VERSION 5.8 ;
BUSBITCHARS "[]" ;
DIVIDERCHAR "/" ;
UNITS
    DATABASE MICRONS 1000 ;
END UNITS

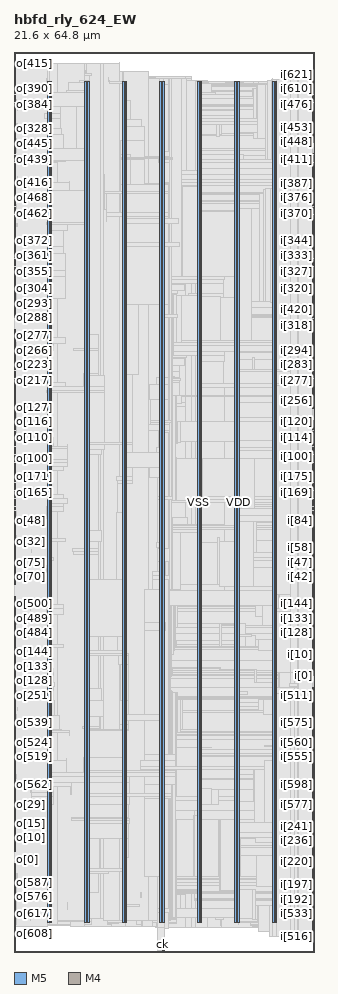
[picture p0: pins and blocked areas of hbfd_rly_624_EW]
MACRO hbfd_rly_624_EW
  FOREIGN hbfd_rly_624_EW 0 0 ;
  CLASS BLOCK ;
  SIZE 21.6 BY 64.8 ;
  PIN ck
    DIRECTION INPUT ;
    USE SIGNAL ;
    PORT
      LAYER M5 ;
        RECT  10.704 0 10.728 0.084 ;
    END
  END ck
  PIN i[0]
    DIRECTION INPUT ;
    USE SIGNAL ;
    PORT
      LAYER M4 ;
        RECT  21.516 19.92 21.6 19.944 ;
    END
  END i[0]
  PIN i[100]
    DIRECTION INPUT ;
    USE SIGNAL ;
    PORT
      LAYER M4 ;
        RECT  21.516 35.664 21.6 35.688 ;
    END
  END i[100]
  PIN i[101]
    DIRECTION INPUT ;
    USE SIGNAL ;
    PORT
      LAYER M4 ;
        RECT  21.516 35.76 21.6 35.784 ;
    END
  END i[101]
  PIN i[102]
    DIRECTION INPUT ;
    USE SIGNAL ;
    PORT
      LAYER M4 ;
        RECT  21.516 35.856 21.6 35.88 ;
    END
  END i[102]
  PIN i[103]
    DIRECTION INPUT ;
    USE SIGNAL ;
    PORT
      LAYER M4 ;
        RECT  21.516 35.952 21.6 35.976 ;
    END
  END i[103]
  PIN i[104]
    DIRECTION INPUT ;
    USE SIGNAL ;
    PORT
      LAYER M4 ;
        RECT  21.516 36.048 21.6 36.072 ;
    END
  END i[104]
  PIN i[105]
    DIRECTION INPUT ;
    USE SIGNAL ;
    PORT
      LAYER M4 ;
        RECT  21.516 36.144 21.6 36.168 ;
    END
  END i[105]
  PIN i[106]
    DIRECTION INPUT ;
    USE SIGNAL ;
    PORT
      LAYER M4 ;
        RECT  21.516 36.24 21.6 36.264 ;
    END
  END i[106]
  PIN i[107]
    DIRECTION INPUT ;
    USE SIGNAL ;
    PORT
      LAYER M4 ;
        RECT  21.516 36.336 21.6 36.36 ;
    END
  END i[107]
  PIN i[108]
    DIRECTION INPUT ;
    USE SIGNAL ;
    PORT
      LAYER M4 ;
        RECT  21.516 36.432 21.6 36.456 ;
    END
  END i[108]
  PIN i[109]
    DIRECTION INPUT ;
    USE SIGNAL ;
    PORT
      LAYER M4 ;
        RECT  21.516 36.528 21.6 36.552 ;
    END
  END i[109]
  PIN i[10]
    DIRECTION INPUT ;
    USE SIGNAL ;
    PORT
      LAYER M4 ;
        RECT  21.516 20.88 21.6 20.904 ;
    END
  END i[10]
  PIN i[110]
    DIRECTION INPUT ;
    USE SIGNAL ;
    PORT
      LAYER M4 ;
        RECT  21.516 36.624 21.6 36.648 ;
    END
  END i[110]
  PIN i[111]
    DIRECTION INPUT ;
    USE SIGNAL ;
    PORT
      LAYER M4 ;
        RECT  21.516 36.72 21.6 36.744 ;
    END
  END i[111]
  PIN i[112]
    DIRECTION INPUT ;
    USE SIGNAL ;
    PORT
      LAYER M4 ;
        RECT  21.516 36.816 21.6 36.84 ;
    END
  END i[112]
  PIN i[113]
    DIRECTION INPUT ;
    USE SIGNAL ;
    PORT
      LAYER M4 ;
        RECT  21.516 36.912 21.6 36.936 ;
    END
  END i[113]
  PIN i[114]
    DIRECTION INPUT ;
    USE SIGNAL ;
    PORT
      LAYER M4 ;
        RECT  21.516 37.008 21.6 37.032 ;
    END
  END i[114]
  PIN i[115]
    DIRECTION INPUT ;
    USE SIGNAL ;
    PORT
      LAYER M4 ;
        RECT  21.516 37.104 21.6 37.128 ;
    END
  END i[115]
  PIN i[116]
    DIRECTION INPUT ;
    USE SIGNAL ;
    PORT
      LAYER M4 ;
        RECT  21.516 37.2 21.6 37.224 ;
    END
  END i[116]
  PIN i[117]
    DIRECTION INPUT ;
    USE SIGNAL ;
    PORT
      LAYER M4 ;
        RECT  21.516 37.296 21.6 37.32 ;
    END
  END i[117]
  PIN i[118]
    DIRECTION INPUT ;
    USE SIGNAL ;
    PORT
      LAYER M4 ;
        RECT  21.516 37.392 21.6 37.416 ;
    END
  END i[118]
  PIN i[119]
    DIRECTION INPUT ;
    USE SIGNAL ;
    PORT
      LAYER M4 ;
        RECT  21.516 37.488 21.6 37.512 ;
    END
  END i[119]
  PIN i[11]
    DIRECTION INPUT ;
    USE SIGNAL ;
    PORT
      LAYER M4 ;
        RECT  21.516 20.976 21.6 21 ;
    END
  END i[11]
  PIN i[120]
    DIRECTION INPUT ;
    USE SIGNAL ;
    PORT
      LAYER M4 ;
        RECT  21.516 37.584 21.6 37.608 ;
    END
  END i[120]
  PIN i[121]
    DIRECTION INPUT ;
    USE SIGNAL ;
    PORT
      LAYER M4 ;
        RECT  21.516 37.68 21.6 37.704 ;
    END
  END i[121]
  PIN i[122]
    DIRECTION INPUT ;
    USE SIGNAL ;
    PORT
      LAYER M4 ;
        RECT  21.516 37.776 21.6 37.8 ;
    END
  END i[122]
  PIN i[123]
    DIRECTION INPUT ;
    USE SIGNAL ;
    PORT
      LAYER M4 ;
        RECT  21.516 37.872 21.6 37.896 ;
    END
  END i[123]
  PIN i[124]
    DIRECTION INPUT ;
    USE SIGNAL ;
    PORT
      LAYER M4 ;
        RECT  21.516 37.968 21.6 37.992 ;
    END
  END i[124]
  PIN i[125]
    DIRECTION INPUT ;
    USE SIGNAL ;
    PORT
      LAYER M4 ;
        RECT  21.516 38.064 21.6 38.088 ;
    END
  END i[125]
  PIN i[126]
    DIRECTION INPUT ;
    USE SIGNAL ;
    PORT
      LAYER M4 ;
        RECT  21.516 38.16 21.6 38.184 ;
    END
  END i[126]
  PIN i[127]
    DIRECTION INPUT ;
    USE SIGNAL ;
    PORT
      LAYER M4 ;
        RECT  21.516 38.256 21.6 38.28 ;
    END
  END i[127]
  PIN i[128]
    DIRECTION INPUT ;
    USE SIGNAL ;
    PORT
      LAYER M4 ;
        RECT  21.516 22.992 21.6 23.016 ;
    END
  END i[128]
  PIN i[129]
    DIRECTION INPUT ;
    USE SIGNAL ;
    PORT
      LAYER M4 ;
        RECT  21.516 23.088 21.6 23.112 ;
    END
  END i[129]
  PIN i[12]
    DIRECTION INPUT ;
    USE SIGNAL ;
    PORT
      LAYER M4 ;
        RECT  21.516 21.072 21.6 21.096 ;
    END
  END i[12]
  PIN i[130]
    DIRECTION INPUT ;
    USE SIGNAL ;
    PORT
      LAYER M4 ;
        RECT  21.516 23.184 21.6 23.208 ;
    END
  END i[130]
  PIN i[131]
    DIRECTION INPUT ;
    USE SIGNAL ;
    PORT
      LAYER M4 ;
        RECT  21.516 23.28 21.6 23.304 ;
    END
  END i[131]
  PIN i[132]
    DIRECTION INPUT ;
    USE SIGNAL ;
    PORT
      LAYER M4 ;
        RECT  21.516 23.376 21.6 23.4 ;
    END
  END i[132]
  PIN i[133]
    DIRECTION INPUT ;
    USE SIGNAL ;
    PORT
      LAYER M4 ;
        RECT  21.516 23.472 21.6 23.496 ;
    END
  END i[133]
  PIN i[134]
    DIRECTION INPUT ;
    USE SIGNAL ;
    PORT
      LAYER M4 ;
        RECT  21.516 23.568 21.6 23.592 ;
    END
  END i[134]
  PIN i[135]
    DIRECTION INPUT ;
    USE SIGNAL ;
    PORT
      LAYER M4 ;
        RECT  21.516 23.664 21.6 23.688 ;
    END
  END i[135]
  PIN i[136]
    DIRECTION INPUT ;
    USE SIGNAL ;
    PORT
      LAYER M4 ;
        RECT  21.516 23.76 21.6 23.784 ;
    END
  END i[136]
  PIN i[137]
    DIRECTION INPUT ;
    USE SIGNAL ;
    PORT
      LAYER M4 ;
        RECT  21.516 23.856 21.6 23.88 ;
    END
  END i[137]
  PIN i[138]
    DIRECTION INPUT ;
    USE SIGNAL ;
    PORT
      LAYER M4 ;
        RECT  21.516 23.952 21.6 23.976 ;
    END
  END i[138]
  PIN i[139]
    DIRECTION INPUT ;
    USE SIGNAL ;
    PORT
      LAYER M4 ;
        RECT  21.516 24.048 21.6 24.072 ;
    END
  END i[139]
  PIN i[13]
    DIRECTION INPUT ;
    USE SIGNAL ;
    PORT
      LAYER M4 ;
        RECT  21.516 21.168 21.6 21.192 ;
    END
  END i[13]
  PIN i[140]
    DIRECTION INPUT ;
    USE SIGNAL ;
    PORT
      LAYER M4 ;
        RECT  21.516 24.144 21.6 24.168 ;
    END
  END i[140]
  PIN i[141]
    DIRECTION INPUT ;
    USE SIGNAL ;
    PORT
      LAYER M4 ;
        RECT  21.516 24.24 21.6 24.264 ;
    END
  END i[141]
  PIN i[142]
    DIRECTION INPUT ;
    USE SIGNAL ;
    PORT
      LAYER M4 ;
        RECT  21.516 24.336 21.6 24.36 ;
    END
  END i[142]
  PIN i[143]
    DIRECTION INPUT ;
    USE SIGNAL ;
    PORT
      LAYER M4 ;
        RECT  21.516 24.432 21.6 24.456 ;
    END
  END i[143]
  PIN i[144]
    DIRECTION INPUT ;
    USE SIGNAL ;
    PORT
      LAYER M4 ;
        RECT  21.516 24.528 21.6 24.552 ;
    END
  END i[144]
  PIN i[145]
    DIRECTION INPUT ;
    USE SIGNAL ;
    PORT
      LAYER M4 ;
        RECT  21.516 24.624 21.6 24.648 ;
    END
  END i[145]
  PIN i[146]
    DIRECTION INPUT ;
    USE SIGNAL ;
    PORT
      LAYER M4 ;
        RECT  21.516 24.72 21.6 24.744 ;
    END
  END i[146]
  PIN i[147]
    DIRECTION INPUT ;
    USE SIGNAL ;
    PORT
      LAYER M4 ;
        RECT  21.516 24.816 21.6 24.84 ;
    END
  END i[147]
  PIN i[148]
    DIRECTION INPUT ;
    USE SIGNAL ;
    PORT
      LAYER M4 ;
        RECT  21.516 24.912 21.6 24.936 ;
    END
  END i[148]
  PIN i[149]
    DIRECTION INPUT ;
    USE SIGNAL ;
    PORT
      LAYER M4 ;
        RECT  21.516 25.008 21.6 25.032 ;
    END
  END i[149]
  PIN i[14]
    DIRECTION INPUT ;
    USE SIGNAL ;
    PORT
      LAYER M4 ;
        RECT  21.516 21.264 21.6 21.288 ;
    END
  END i[14]
  PIN i[150]
    DIRECTION INPUT ;
    USE SIGNAL ;
    PORT
      LAYER M4 ;
        RECT  21.516 25.104 21.6 25.128 ;
    END
  END i[150]
  PIN i[151]
    DIRECTION INPUT ;
    USE SIGNAL ;
    PORT
      LAYER M4 ;
        RECT  21.516 25.2 21.6 25.224 ;
    END
  END i[151]
  PIN i[152]
    DIRECTION INPUT ;
    USE SIGNAL ;
    PORT
      LAYER M4 ;
        RECT  21.516 25.296 21.6 25.32 ;
    END
  END i[152]
  PIN i[153]
    DIRECTION INPUT ;
    USE SIGNAL ;
    PORT
      LAYER M4 ;
        RECT  21.516 25.392 21.6 25.416 ;
    END
  END i[153]
  PIN i[154]
    DIRECTION INPUT ;
    USE SIGNAL ;
    PORT
      LAYER M4 ;
        RECT  21.516 25.488 21.6 25.512 ;
    END
  END i[154]
  PIN i[155]
    DIRECTION INPUT ;
    USE SIGNAL ;
    PORT
      LAYER M4 ;
        RECT  21.516 25.584 21.6 25.608 ;
    END
  END i[155]
  PIN i[156]
    DIRECTION INPUT ;
    USE SIGNAL ;
    PORT
      LAYER M4 ;
        RECT  21.516 25.68 21.6 25.704 ;
    END
  END i[156]
  PIN i[157]
    DIRECTION INPUT ;
    USE SIGNAL ;
    PORT
      LAYER M4 ;
        RECT  21.516 25.776 21.6 25.8 ;
    END
  END i[157]
  PIN i[158]
    DIRECTION INPUT ;
    USE SIGNAL ;
    PORT
      LAYER M4 ;
        RECT  21.516 25.872 21.6 25.896 ;
    END
  END i[158]
  PIN i[159]
    DIRECTION INPUT ;
    USE SIGNAL ;
    PORT
      LAYER M4 ;
        RECT  21.516 25.968 21.6 25.992 ;
    END
  END i[159]
  PIN i[15]
    DIRECTION INPUT ;
    USE SIGNAL ;
    PORT
      LAYER M4 ;
        RECT  21.516 21.36 21.6 21.384 ;
    END
  END i[15]
  PIN i[160]
    DIRECTION INPUT ;
    USE SIGNAL ;
    PORT
      LAYER M4 ;
        RECT  21.516 32.208 21.6 32.232 ;
    END
  END i[160]
  PIN i[161]
    DIRECTION INPUT ;
    USE SIGNAL ;
    PORT
      LAYER M4 ;
        RECT  21.516 32.304 21.6 32.328 ;
    END
  END i[161]
  PIN i[162]
    DIRECTION INPUT ;
    USE SIGNAL ;
    PORT
      LAYER M4 ;
        RECT  21.516 32.4 21.6 32.424 ;
    END
  END i[162]
  PIN i[163]
    DIRECTION INPUT ;
    USE SIGNAL ;
    PORT
      LAYER M4 ;
        RECT  21.516 32.496 21.6 32.52 ;
    END
  END i[163]
  PIN i[164]
    DIRECTION INPUT ;
    USE SIGNAL ;
    PORT
      LAYER M4 ;
        RECT  21.516 32.592 21.6 32.616 ;
    END
  END i[164]
  PIN i[165]
    DIRECTION INPUT ;
    USE SIGNAL ;
    PORT
      LAYER M4 ;
        RECT  21.516 32.688 21.6 32.712 ;
    END
  END i[165]
  PIN i[166]
    DIRECTION INPUT ;
    USE SIGNAL ;
    PORT
      LAYER M4 ;
        RECT  21.516 32.784 21.6 32.808 ;
    END
  END i[166]
  PIN i[167]
    DIRECTION INPUT ;
    USE SIGNAL ;
    PORT
      LAYER M4 ;
        RECT  21.516 32.88 21.6 32.904 ;
    END
  END i[167]
  PIN i[168]
    DIRECTION INPUT ;
    USE SIGNAL ;
    PORT
      LAYER M4 ;
        RECT  21.516 32.976 21.6 33 ;
    END
  END i[168]
  PIN i[169]
    DIRECTION INPUT ;
    USE SIGNAL ;
    PORT
      LAYER M4 ;
        RECT  21.516 33.072 21.6 33.096 ;
    END
  END i[169]
  PIN i[16]
    DIRECTION INPUT ;
    USE SIGNAL ;
    PORT
      LAYER M4 ;
        RECT  21.516 21.456 21.6 21.48 ;
    END
  END i[16]
  PIN i[170]
    DIRECTION INPUT ;
    USE SIGNAL ;
    PORT
      LAYER M4 ;
        RECT  21.516 33.168 21.6 33.192 ;
    END
  END i[170]
  PIN i[171]
    DIRECTION INPUT ;
    USE SIGNAL ;
    PORT
      LAYER M4 ;
        RECT  21.516 33.264 21.6 33.288 ;
    END
  END i[171]
  PIN i[172]
    DIRECTION INPUT ;
    USE SIGNAL ;
    PORT
      LAYER M4 ;
        RECT  21.516 33.36 21.6 33.384 ;
    END
  END i[172]
  PIN i[173]
    DIRECTION INPUT ;
    USE SIGNAL ;
    PORT
      LAYER M4 ;
        RECT  21.516 33.456 21.6 33.48 ;
    END
  END i[173]
  PIN i[174]
    DIRECTION INPUT ;
    USE SIGNAL ;
    PORT
      LAYER M4 ;
        RECT  21.516 33.552 21.6 33.576 ;
    END
  END i[174]
  PIN i[175]
    DIRECTION INPUT ;
    USE SIGNAL ;
    PORT
      LAYER M4 ;
        RECT  21.516 33.648 21.6 33.672 ;
    END
  END i[175]
  PIN i[176]
    DIRECTION INPUT ;
    USE SIGNAL ;
    PORT
      LAYER M4 ;
        RECT  21.516 33.744 21.6 33.768 ;
    END
  END i[176]
  PIN i[177]
    DIRECTION INPUT ;
    USE SIGNAL ;
    PORT
      LAYER M4 ;
        RECT  21.516 33.84 21.6 33.864 ;
    END
  END i[177]
  PIN i[178]
    DIRECTION INPUT ;
    USE SIGNAL ;
    PORT
      LAYER M4 ;
        RECT  21.516 33.936 21.6 33.96 ;
    END
  END i[178]
  PIN i[179]
    DIRECTION INPUT ;
    USE SIGNAL ;
    PORT
      LAYER M4 ;
        RECT  21.516 34.032 21.6 34.056 ;
    END
  END i[179]
  PIN i[17]
    DIRECTION INPUT ;
    USE SIGNAL ;
    PORT
      LAYER M4 ;
        RECT  21.516 21.552 21.6 21.576 ;
    END
  END i[17]
  PIN i[180]
    DIRECTION INPUT ;
    USE SIGNAL ;
    PORT
      LAYER M4 ;
        RECT  21.516 34.128 21.6 34.152 ;
    END
  END i[180]
  PIN i[181]
    DIRECTION INPUT ;
    USE SIGNAL ;
    PORT
      LAYER M4 ;
        RECT  21.516 34.224 21.6 34.248 ;
    END
  END i[181]
  PIN i[182]
    DIRECTION INPUT ;
    USE SIGNAL ;
    PORT
      LAYER M4 ;
        RECT  21.516 34.32 21.6 34.344 ;
    END
  END i[182]
  PIN i[183]
    DIRECTION INPUT ;
    USE SIGNAL ;
    PORT
      LAYER M4 ;
        RECT  21.516 34.416 21.6 34.44 ;
    END
  END i[183]
  PIN i[184]
    DIRECTION INPUT ;
    USE SIGNAL ;
    PORT
      LAYER M4 ;
        RECT  21.516 34.512 21.6 34.536 ;
    END
  END i[184]
  PIN i[185]
    DIRECTION INPUT ;
    USE SIGNAL ;
    PORT
      LAYER M4 ;
        RECT  21.516 34.608 21.6 34.632 ;
    END
  END i[185]
  PIN i[186]
    DIRECTION INPUT ;
    USE SIGNAL ;
    PORT
      LAYER M4 ;
        RECT  21.516 34.704 21.6 34.728 ;
    END
  END i[186]
  PIN i[187]
    DIRECTION INPUT ;
    USE SIGNAL ;
    PORT
      LAYER M4 ;
        RECT  21.516 34.8 21.6 34.824 ;
    END
  END i[187]
  PIN i[188]
    DIRECTION INPUT ;
    USE SIGNAL ;
    PORT
      LAYER M4 ;
        RECT  21.516 34.896 21.6 34.92 ;
    END
  END i[188]
  PIN i[189]
    DIRECTION INPUT ;
    USE SIGNAL ;
    PORT
      LAYER M4 ;
        RECT  21.516 34.992 21.6 35.016 ;
    END
  END i[189]
  PIN i[18]
    DIRECTION INPUT ;
    USE SIGNAL ;
    PORT
      LAYER M4 ;
        RECT  21.516 21.648 21.6 21.672 ;
    END
  END i[18]
  PIN i[190]
    DIRECTION INPUT ;
    USE SIGNAL ;
    PORT
      LAYER M4 ;
        RECT  21.516 35.088 21.6 35.112 ;
    END
  END i[190]
  PIN i[191]
    DIRECTION INPUT ;
    USE SIGNAL ;
    PORT
      LAYER M4 ;
        RECT  21.516 35.184 21.6 35.208 ;
    END
  END i[191]
  PIN i[192]
    DIRECTION INPUT ;
    USE SIGNAL ;
    PORT
      LAYER M4 ;
        RECT  21.516 3.792 21.6 3.816 ;
    END
  END i[192]
  PIN i[193]
    DIRECTION INPUT ;
    USE SIGNAL ;
    PORT
      LAYER M4 ;
        RECT  21.516 3.888 21.6 3.912 ;
    END
  END i[193]
  PIN i[194]
    DIRECTION INPUT ;
    USE SIGNAL ;
    PORT
      LAYER M4 ;
        RECT  21.516 3.984 21.6 4.008 ;
    END
  END i[194]
  PIN i[195]
    DIRECTION INPUT ;
    USE SIGNAL ;
    PORT
      LAYER M4 ;
        RECT  21.516 4.08 21.6 4.104 ;
    END
  END i[195]
  PIN i[196]
    DIRECTION INPUT ;
    USE SIGNAL ;
    PORT
      LAYER M4 ;
        RECT  21.516 4.176 21.6 4.2 ;
    END
  END i[196]
  PIN i[197]
    DIRECTION INPUT ;
    USE SIGNAL ;
    PORT
      LAYER M4 ;
        RECT  21.516 4.272 21.6 4.296 ;
    END
  END i[197]
  PIN i[198]
    DIRECTION INPUT ;
    USE SIGNAL ;
    PORT
      LAYER M4 ;
        RECT  21.516 4.368 21.6 4.392 ;
    END
  END i[198]
  PIN i[199]
    DIRECTION INPUT ;
    USE SIGNAL ;
    PORT
      LAYER M4 ;
        RECT  21.516 4.464 21.6 4.488 ;
    END
  END i[199]
  PIN i[19]
    DIRECTION INPUT ;
    USE SIGNAL ;
    PORT
      LAYER M4 ;
        RECT  21.516 21.744 21.6 21.768 ;
    END
  END i[19]
  PIN i[1]
    DIRECTION INPUT ;
    USE SIGNAL ;
    PORT
      LAYER M4 ;
        RECT  21.516 20.016 21.6 20.04 ;
    END
  END i[1]
  PIN i[200]
    DIRECTION INPUT ;
    USE SIGNAL ;
    PORT
      LAYER M4 ;
        RECT  21.516 4.56 21.6 4.584 ;
    END
  END i[200]
  PIN i[201]
    DIRECTION INPUT ;
    USE SIGNAL ;
    PORT
      LAYER M4 ;
        RECT  21.516 4.656 21.6 4.68 ;
    END
  END i[201]
  PIN i[202]
    DIRECTION INPUT ;
    USE SIGNAL ;
    PORT
      LAYER M4 ;
        RECT  21.516 4.752 21.6 4.776 ;
    END
  END i[202]
  PIN i[203]
    DIRECTION INPUT ;
    USE SIGNAL ;
    PORT
      LAYER M4 ;
        RECT  21.516 4.848 21.6 4.872 ;
    END
  END i[203]
  PIN i[204]
    DIRECTION INPUT ;
    USE SIGNAL ;
    PORT
      LAYER M4 ;
        RECT  21.516 4.944 21.6 4.968 ;
    END
  END i[204]
  PIN i[205]
    DIRECTION INPUT ;
    USE SIGNAL ;
    PORT
      LAYER M4 ;
        RECT  21.516 5.04 21.6 5.064 ;
    END
  END i[205]
  PIN i[206]
    DIRECTION INPUT ;
    USE SIGNAL ;
    PORT
      LAYER M4 ;
        RECT  21.516 5.136 21.6 5.16 ;
    END
  END i[206]
  PIN i[207]
    DIRECTION INPUT ;
    USE SIGNAL ;
    PORT
      LAYER M4 ;
        RECT  21.516 5.232 21.6 5.256 ;
    END
  END i[207]
  PIN i[208]
    DIRECTION INPUT ;
    USE SIGNAL ;
    PORT
      LAYER M4 ;
        RECT  21.516 5.328 21.6 5.352 ;
    END
  END i[208]
  PIN i[209]
    DIRECTION INPUT ;
    USE SIGNAL ;
    PORT
      LAYER M4 ;
        RECT  21.516 5.424 21.6 5.448 ;
    END
  END i[209]
  PIN i[20]
    DIRECTION INPUT ;
    USE SIGNAL ;
    PORT
      LAYER M4 ;
        RECT  21.516 21.84 21.6 21.864 ;
    END
  END i[20]
  PIN i[210]
    DIRECTION INPUT ;
    USE SIGNAL ;
    PORT
      LAYER M4 ;
        RECT  21.516 5.52 21.6 5.544 ;
    END
  END i[210]
  PIN i[211]
    DIRECTION INPUT ;
    USE SIGNAL ;
    PORT
      LAYER M4 ;
        RECT  21.516 5.616 21.6 5.64 ;
    END
  END i[211]
  PIN i[212]
    DIRECTION INPUT ;
    USE SIGNAL ;
    PORT
      LAYER M4 ;
        RECT  21.516 5.712 21.6 5.736 ;
    END
  END i[212]
  PIN i[213]
    DIRECTION INPUT ;
    USE SIGNAL ;
    PORT
      LAYER M4 ;
        RECT  21.516 5.808 21.6 5.832 ;
    END
  END i[213]
  PIN i[214]
    DIRECTION INPUT ;
    USE SIGNAL ;
    PORT
      LAYER M4 ;
        RECT  21.516 5.904 21.6 5.928 ;
    END
  END i[214]
  PIN i[215]
    DIRECTION INPUT ;
    USE SIGNAL ;
    PORT
      LAYER M4 ;
        RECT  21.516 6 21.6 6.024 ;
    END
  END i[215]
  PIN i[216]
    DIRECTION INPUT ;
    USE SIGNAL ;
    PORT
      LAYER M4 ;
        RECT  21.516 6.096 21.6 6.12 ;
    END
  END i[216]
  PIN i[217]
    DIRECTION INPUT ;
    USE SIGNAL ;
    PORT
      LAYER M4 ;
        RECT  21.516 6.192 21.6 6.216 ;
    END
  END i[217]
  PIN i[218]
    DIRECTION INPUT ;
    USE SIGNAL ;
    PORT
      LAYER M4 ;
        RECT  21.516 6.288 21.6 6.312 ;
    END
  END i[218]
  PIN i[219]
    DIRECTION INPUT ;
    USE SIGNAL ;
    PORT
      LAYER M4 ;
        RECT  21.516 6.384 21.6 6.408 ;
    END
  END i[219]
  PIN i[21]
    DIRECTION INPUT ;
    USE SIGNAL ;
    PORT
      LAYER M4 ;
        RECT  21.516 21.936 21.6 21.96 ;
    END
  END i[21]
  PIN i[220]
    DIRECTION INPUT ;
    USE SIGNAL ;
    PORT
      LAYER M4 ;
        RECT  21.516 6.48 21.6 6.504 ;
    END
  END i[220]
  PIN i[221]
    DIRECTION INPUT ;
    USE SIGNAL ;
    PORT
      LAYER M4 ;
        RECT  21.516 6.576 21.6 6.6 ;
    END
  END i[221]
  PIN i[222]
    DIRECTION INPUT ;
    USE SIGNAL ;
    PORT
      LAYER M4 ;
        RECT  21.516 6.672 21.6 6.696 ;
    END
  END i[222]
  PIN i[223]
    DIRECTION INPUT ;
    USE SIGNAL ;
    PORT
      LAYER M4 ;
        RECT  21.516 6.768 21.6 6.792 ;
    END
  END i[223]
  PIN i[224]
    DIRECTION INPUT ;
    USE SIGNAL ;
    PORT
      LAYER M4 ;
        RECT  21.516 6.864 21.6 6.888 ;
    END
  END i[224]
  PIN i[225]
    DIRECTION INPUT ;
    USE SIGNAL ;
    PORT
      LAYER M4 ;
        RECT  21.516 6.96 21.6 6.984 ;
    END
  END i[225]
  PIN i[226]
    DIRECTION INPUT ;
    USE SIGNAL ;
    PORT
      LAYER M4 ;
        RECT  21.516 7.056 21.6 7.08 ;
    END
  END i[226]
  PIN i[227]
    DIRECTION INPUT ;
    USE SIGNAL ;
    PORT
      LAYER M4 ;
        RECT  21.516 7.152 21.6 7.176 ;
    END
  END i[227]
  PIN i[228]
    DIRECTION INPUT ;
    USE SIGNAL ;
    PORT
      LAYER M4 ;
        RECT  21.516 7.248 21.6 7.272 ;
    END
  END i[228]
  PIN i[229]
    DIRECTION INPUT ;
    USE SIGNAL ;
    PORT
      LAYER M4 ;
        RECT  21.516 7.344 21.6 7.368 ;
    END
  END i[229]
  PIN i[22]
    DIRECTION INPUT ;
    USE SIGNAL ;
    PORT
      LAYER M4 ;
        RECT  21.516 22.032 21.6 22.056 ;
    END
  END i[22]
  PIN i[230]
    DIRECTION INPUT ;
    USE SIGNAL ;
    PORT
      LAYER M4 ;
        RECT  21.516 7.44 21.6 7.464 ;
    END
  END i[230]
  PIN i[231]
    DIRECTION INPUT ;
    USE SIGNAL ;
    PORT
      LAYER M4 ;
        RECT  21.516 7.536 21.6 7.56 ;
    END
  END i[231]
  PIN i[232]
    DIRECTION INPUT ;
    USE SIGNAL ;
    PORT
      LAYER M4 ;
        RECT  21.516 7.632 21.6 7.656 ;
    END
  END i[232]
  PIN i[233]
    DIRECTION INPUT ;
    USE SIGNAL ;
    PORT
      LAYER M4 ;
        RECT  21.516 7.728 21.6 7.752 ;
    END
  END i[233]
  PIN i[234]
    DIRECTION INPUT ;
    USE SIGNAL ;
    PORT
      LAYER M4 ;
        RECT  21.516 7.824 21.6 7.848 ;
    END
  END i[234]
  PIN i[235]
    DIRECTION INPUT ;
    USE SIGNAL ;
    PORT
      LAYER M4 ;
        RECT  21.516 7.92 21.6 7.944 ;
    END
  END i[235]
  PIN i[236]
    DIRECTION INPUT ;
    USE SIGNAL ;
    PORT
      LAYER M4 ;
        RECT  21.516 8.016 21.6 8.04 ;
    END
  END i[236]
  PIN i[237]
    DIRECTION INPUT ;
    USE SIGNAL ;
    PORT
      LAYER M4 ;
        RECT  21.516 8.112 21.6 8.136 ;
    END
  END i[237]
  PIN i[238]
    DIRECTION INPUT ;
    USE SIGNAL ;
    PORT
      LAYER M4 ;
        RECT  21.516 8.208 21.6 8.232 ;
    END
  END i[238]
  PIN i[239]
    DIRECTION INPUT ;
    USE SIGNAL ;
    PORT
      LAYER M4 ;
        RECT  21.516 8.304 21.6 8.328 ;
    END
  END i[239]
  PIN i[23]
    DIRECTION INPUT ;
    USE SIGNAL ;
    PORT
      LAYER M4 ;
        RECT  21.516 22.128 21.6 22.152 ;
    END
  END i[23]
  PIN i[240]
    DIRECTION INPUT ;
    USE SIGNAL ;
    PORT
      LAYER M4 ;
        RECT  21.516 8.4 21.6 8.424 ;
    END
  END i[240]
  PIN i[241]
    DIRECTION INPUT ;
    USE SIGNAL ;
    PORT
      LAYER M4 ;
        RECT  21.516 8.496 21.6 8.52 ;
    END
  END i[241]
  PIN i[242]
    DIRECTION INPUT ;
    USE SIGNAL ;
    PORT
      LAYER M4 ;
        RECT  21.516 8.592 21.6 8.616 ;
    END
  END i[242]
  PIN i[243]
    DIRECTION INPUT ;
    USE SIGNAL ;
    PORT
      LAYER M4 ;
        RECT  21.516 8.688 21.6 8.712 ;
    END
  END i[243]
  PIN i[244]
    DIRECTION INPUT ;
    USE SIGNAL ;
    PORT
      LAYER M4 ;
        RECT  21.516 8.784 21.6 8.808 ;
    END
  END i[244]
  PIN i[245]
    DIRECTION INPUT ;
    USE SIGNAL ;
    PORT
      LAYER M4 ;
        RECT  21.516 8.88 21.6 8.904 ;
    END
  END i[245]
  PIN i[246]
    DIRECTION INPUT ;
    USE SIGNAL ;
    PORT
      LAYER M4 ;
        RECT  21.516 8.976 21.6 9 ;
    END
  END i[246]
  PIN i[247]
    DIRECTION INPUT ;
    USE SIGNAL ;
    PORT
      LAYER M4 ;
        RECT  21.516 9.072 21.6 9.096 ;
    END
  END i[247]
  PIN i[248]
    DIRECTION INPUT ;
    USE SIGNAL ;
    PORT
      LAYER M4 ;
        RECT  21.516 9.168 21.6 9.192 ;
    END
  END i[248]
  PIN i[249]
    DIRECTION INPUT ;
    USE SIGNAL ;
    PORT
      LAYER M4 ;
        RECT  21.516 9.264 21.6 9.288 ;
    END
  END i[249]
  PIN i[24]
    DIRECTION INPUT ;
    USE SIGNAL ;
    PORT
      LAYER M4 ;
        RECT  21.516 22.224 21.6 22.248 ;
    END
  END i[24]
  PIN i[250]
    DIRECTION INPUT ;
    USE SIGNAL ;
    PORT
      LAYER M4 ;
        RECT  21.516 9.36 21.6 9.384 ;
    END
  END i[250]
  PIN i[251]
    DIRECTION INPUT ;
    USE SIGNAL ;
    PORT
      LAYER M4 ;
        RECT  21.516 9.456 21.6 9.48 ;
    END
  END i[251]
  PIN i[252]
    DIRECTION INPUT ;
    USE SIGNAL ;
    PORT
      LAYER M4 ;
        RECT  21.516 9.552 21.6 9.576 ;
    END
  END i[252]
  PIN i[253]
    DIRECTION INPUT ;
    USE SIGNAL ;
    PORT
      LAYER M4 ;
        RECT  21.516 9.648 21.6 9.672 ;
    END
  END i[253]
  PIN i[254]
    DIRECTION INPUT ;
    USE SIGNAL ;
    PORT
      LAYER M4 ;
        RECT  21.516 9.744 21.6 9.768 ;
    END
  END i[254]
  PIN i[255]
    DIRECTION INPUT ;
    USE SIGNAL ;
    PORT
      LAYER M4 ;
        RECT  21.516 9.84 21.6 9.864 ;
    END
  END i[255]
  PIN i[256]
    DIRECTION INPUT ;
    USE SIGNAL ;
    PORT
      LAYER M4 ;
        RECT  21.516 39.12 21.6 39.144 ;
    END
  END i[256]
  PIN i[257]
    DIRECTION INPUT ;
    USE SIGNAL ;
    PORT
      LAYER M4 ;
        RECT  21.516 39.216 21.6 39.24 ;
    END
  END i[257]
  PIN i[258]
    DIRECTION INPUT ;
    USE SIGNAL ;
    PORT
      LAYER M4 ;
        RECT  21.516 39.312 21.6 39.336 ;
    END
  END i[258]
  PIN i[259]
    DIRECTION INPUT ;
    USE SIGNAL ;
    PORT
      LAYER M4 ;
        RECT  21.516 39.408 21.6 39.432 ;
    END
  END i[259]
  PIN i[25]
    DIRECTION INPUT ;
    USE SIGNAL ;
    PORT
      LAYER M4 ;
        RECT  21.516 22.32 21.6 22.344 ;
    END
  END i[25]
  PIN i[260]
    DIRECTION INPUT ;
    USE SIGNAL ;
    PORT
      LAYER M4 ;
        RECT  21.516 39.504 21.6 39.528 ;
    END
  END i[260]
  PIN i[261]
    DIRECTION INPUT ;
    USE SIGNAL ;
    PORT
      LAYER M4 ;
        RECT  21.516 39.6 21.6 39.624 ;
    END
  END i[261]
  PIN i[262]
    DIRECTION INPUT ;
    USE SIGNAL ;
    PORT
      LAYER M4 ;
        RECT  21.516 39.696 21.6 39.72 ;
    END
  END i[262]
  PIN i[263]
    DIRECTION INPUT ;
    USE SIGNAL ;
    PORT
      LAYER M4 ;
        RECT  21.516 39.792 21.6 39.816 ;
    END
  END i[263]
  PIN i[264]
    DIRECTION INPUT ;
    USE SIGNAL ;
    PORT
      LAYER M4 ;
        RECT  21.516 39.888 21.6 39.912 ;
    END
  END i[264]
  PIN i[265]
    DIRECTION INPUT ;
    USE SIGNAL ;
    PORT
      LAYER M4 ;
        RECT  21.516 39.984 21.6 40.008 ;
    END
  END i[265]
  PIN i[266]
    DIRECTION INPUT ;
    USE SIGNAL ;
    PORT
      LAYER M4 ;
        RECT  21.516 40.08 21.6 40.104 ;
    END
  END i[266]
  PIN i[267]
    DIRECTION INPUT ;
    USE SIGNAL ;
    PORT
      LAYER M4 ;
        RECT  21.516 40.176 21.6 40.2 ;
    END
  END i[267]
  PIN i[268]
    DIRECTION INPUT ;
    USE SIGNAL ;
    PORT
      LAYER M4 ;
        RECT  21.516 40.272 21.6 40.296 ;
    END
  END i[268]
  PIN i[269]
    DIRECTION INPUT ;
    USE SIGNAL ;
    PORT
      LAYER M4 ;
        RECT  21.516 40.368 21.6 40.392 ;
    END
  END i[269]
  PIN i[26]
    DIRECTION INPUT ;
    USE SIGNAL ;
    PORT
      LAYER M4 ;
        RECT  21.516 22.416 21.6 22.44 ;
    END
  END i[26]
  PIN i[270]
    DIRECTION INPUT ;
    USE SIGNAL ;
    PORT
      LAYER M4 ;
        RECT  21.516 40.464 21.6 40.488 ;
    END
  END i[270]
  PIN i[271]
    DIRECTION INPUT ;
    USE SIGNAL ;
    PORT
      LAYER M4 ;
        RECT  21.516 40.56 21.6 40.584 ;
    END
  END i[271]
  PIN i[272]
    DIRECTION INPUT ;
    USE SIGNAL ;
    PORT
      LAYER M4 ;
        RECT  21.516 40.656 21.6 40.68 ;
    END
  END i[272]
  PIN i[273]
    DIRECTION INPUT ;
    USE SIGNAL ;
    PORT
      LAYER M4 ;
        RECT  21.516 40.752 21.6 40.776 ;
    END
  END i[273]
  PIN i[274]
    DIRECTION INPUT ;
    USE SIGNAL ;
    PORT
      LAYER M4 ;
        RECT  21.516 40.848 21.6 40.872 ;
    END
  END i[274]
  PIN i[275]
    DIRECTION INPUT ;
    USE SIGNAL ;
    PORT
      LAYER M4 ;
        RECT  21.516 40.944 21.6 40.968 ;
    END
  END i[275]
  PIN i[276]
    DIRECTION INPUT ;
    USE SIGNAL ;
    PORT
      LAYER M4 ;
        RECT  21.516 41.04 21.6 41.064 ;
    END
  END i[276]
  PIN i[277]
    DIRECTION INPUT ;
    USE SIGNAL ;
    PORT
      LAYER M4 ;
        RECT  21.516 41.136 21.6 41.16 ;
    END
  END i[277]
  PIN i[278]
    DIRECTION INPUT ;
    USE SIGNAL ;
    PORT
      LAYER M4 ;
        RECT  21.516 41.232 21.6 41.256 ;
    END
  END i[278]
  PIN i[279]
    DIRECTION INPUT ;
    USE SIGNAL ;
    PORT
      LAYER M4 ;
        RECT  21.516 41.328 21.6 41.352 ;
    END
  END i[279]
  PIN i[27]
    DIRECTION INPUT ;
    USE SIGNAL ;
    PORT
      LAYER M4 ;
        RECT  21.516 22.512 21.6 22.536 ;
    END
  END i[27]
  PIN i[280]
    DIRECTION INPUT ;
    USE SIGNAL ;
    PORT
      LAYER M4 ;
        RECT  21.516 41.424 21.6 41.448 ;
    END
  END i[280]
  PIN i[281]
    DIRECTION INPUT ;
    USE SIGNAL ;
    PORT
      LAYER M4 ;
        RECT  21.516 41.52 21.6 41.544 ;
    END
  END i[281]
  PIN i[282]
    DIRECTION INPUT ;
    USE SIGNAL ;
    PORT
      LAYER M4 ;
        RECT  21.516 41.616 21.6 41.64 ;
    END
  END i[282]
  PIN i[283]
    DIRECTION INPUT ;
    USE SIGNAL ;
    PORT
      LAYER M4 ;
        RECT  21.516 41.712 21.6 41.736 ;
    END
  END i[283]
  PIN i[284]
    DIRECTION INPUT ;
    USE SIGNAL ;
    PORT
      LAYER M4 ;
        RECT  21.516 41.808 21.6 41.832 ;
    END
  END i[284]
  PIN i[285]
    DIRECTION INPUT ;
    USE SIGNAL ;
    PORT
      LAYER M4 ;
        RECT  21.516 41.904 21.6 41.928 ;
    END
  END i[285]
  PIN i[286]
    DIRECTION INPUT ;
    USE SIGNAL ;
    PORT
      LAYER M4 ;
        RECT  21.516 42 21.6 42.024 ;
    END
  END i[286]
  PIN i[287]
    DIRECTION INPUT ;
    USE SIGNAL ;
    PORT
      LAYER M4 ;
        RECT  21.516 42.096 21.6 42.12 ;
    END
  END i[287]
  PIN i[288]
    DIRECTION INPUT ;
    USE SIGNAL ;
    PORT
      LAYER M4 ;
        RECT  21.516 42.192 21.6 42.216 ;
    END
  END i[288]
  PIN i[289]
    DIRECTION INPUT ;
    USE SIGNAL ;
    PORT
      LAYER M4 ;
        RECT  21.516 42.288 21.6 42.312 ;
    END
  END i[289]
  PIN i[28]
    DIRECTION INPUT ;
    USE SIGNAL ;
    PORT
      LAYER M4 ;
        RECT  21.516 22.608 21.6 22.632 ;
    END
  END i[28]
  PIN i[290]
    DIRECTION INPUT ;
    USE SIGNAL ;
    PORT
      LAYER M4 ;
        RECT  21.516 42.384 21.6 42.408 ;
    END
  END i[290]
  PIN i[291]
    DIRECTION INPUT ;
    USE SIGNAL ;
    PORT
      LAYER M4 ;
        RECT  21.516 42.48 21.6 42.504 ;
    END
  END i[291]
  PIN i[292]
    DIRECTION INPUT ;
    USE SIGNAL ;
    PORT
      LAYER M4 ;
        RECT  21.516 42.576 21.6 42.6 ;
    END
  END i[292]
  PIN i[293]
    DIRECTION INPUT ;
    USE SIGNAL ;
    PORT
      LAYER M4 ;
        RECT  21.516 42.672 21.6 42.696 ;
    END
  END i[293]
  PIN i[294]
    DIRECTION INPUT ;
    USE SIGNAL ;
    PORT
      LAYER M4 ;
        RECT  21.516 42.768 21.6 42.792 ;
    END
  END i[294]
  PIN i[295]
    DIRECTION INPUT ;
    USE SIGNAL ;
    PORT
      LAYER M4 ;
        RECT  21.516 42.864 21.6 42.888 ;
    END
  END i[295]
  PIN i[296]
    DIRECTION INPUT ;
    USE SIGNAL ;
    PORT
      LAYER M4 ;
        RECT  21.516 42.96 21.6 42.984 ;
    END
  END i[296]
  PIN i[297]
    DIRECTION INPUT ;
    USE SIGNAL ;
    PORT
      LAYER M4 ;
        RECT  21.516 43.056 21.6 43.08 ;
    END
  END i[297]
  PIN i[298]
    DIRECTION INPUT ;
    USE SIGNAL ;
    PORT
      LAYER M4 ;
        RECT  21.516 43.152 21.6 43.176 ;
    END
  END i[298]
  PIN i[299]
    DIRECTION INPUT ;
    USE SIGNAL ;
    PORT
      LAYER M4 ;
        RECT  21.516 43.248 21.6 43.272 ;
    END
  END i[299]
  PIN i[29]
    DIRECTION INPUT ;
    USE SIGNAL ;
    PORT
      LAYER M4 ;
        RECT  21.516 22.704 21.6 22.728 ;
    END
  END i[29]
  PIN i[2]
    DIRECTION INPUT ;
    USE SIGNAL ;
    PORT
      LAYER M4 ;
        RECT  21.516 20.112 21.6 20.136 ;
    END
  END i[2]
  PIN i[300]
    DIRECTION INPUT ;
    USE SIGNAL ;
    PORT
      LAYER M4 ;
        RECT  21.516 43.344 21.6 43.368 ;
    END
  END i[300]
  PIN i[301]
    DIRECTION INPUT ;
    USE SIGNAL ;
    PORT
      LAYER M4 ;
        RECT  21.516 43.44 21.6 43.464 ;
    END
  END i[301]
  PIN i[302]
    DIRECTION INPUT ;
    USE SIGNAL ;
    PORT
      LAYER M4 ;
        RECT  21.516 43.536 21.6 43.56 ;
    END
  END i[302]
  PIN i[303]
    DIRECTION INPUT ;
    USE SIGNAL ;
    PORT
      LAYER M4 ;
        RECT  21.516 43.632 21.6 43.656 ;
    END
  END i[303]
  PIN i[304]
    DIRECTION INPUT ;
    USE SIGNAL ;
    PORT
      LAYER M4 ;
        RECT  21.516 43.728 21.6 43.752 ;
    END
  END i[304]
  PIN i[305]
    DIRECTION INPUT ;
    USE SIGNAL ;
    PORT
      LAYER M4 ;
        RECT  21.516 43.824 21.6 43.848 ;
    END
  END i[305]
  PIN i[306]
    DIRECTION INPUT ;
    USE SIGNAL ;
    PORT
      LAYER M4 ;
        RECT  21.516 43.92 21.6 43.944 ;
    END
  END i[306]
  PIN i[307]
    DIRECTION INPUT ;
    USE SIGNAL ;
    PORT
      LAYER M4 ;
        RECT  21.516 44.016 21.6 44.04 ;
    END
  END i[307]
  PIN i[308]
    DIRECTION INPUT ;
    USE SIGNAL ;
    PORT
      LAYER M4 ;
        RECT  21.516 44.112 21.6 44.136 ;
    END
  END i[308]
  PIN i[309]
    DIRECTION INPUT ;
    USE SIGNAL ;
    PORT
      LAYER M4 ;
        RECT  21.516 44.208 21.6 44.232 ;
    END
  END i[309]
  PIN i[30]
    DIRECTION INPUT ;
    USE SIGNAL ;
    PORT
      LAYER M4 ;
        RECT  21.516 22.8 21.6 22.824 ;
    END
  END i[30]
  PIN i[310]
    DIRECTION INPUT ;
    USE SIGNAL ;
    PORT
      LAYER M4 ;
        RECT  21.516 44.304 21.6 44.328 ;
    END
  END i[310]
  PIN i[311]
    DIRECTION INPUT ;
    USE SIGNAL ;
    PORT
      LAYER M4 ;
        RECT  21.516 44.4 21.6 44.424 ;
    END
  END i[311]
  PIN i[312]
    DIRECTION INPUT ;
    USE SIGNAL ;
    PORT
      LAYER M4 ;
        RECT  21.516 44.496 21.6 44.52 ;
    END
  END i[312]
  PIN i[313]
    DIRECTION INPUT ;
    USE SIGNAL ;
    PORT
      LAYER M4 ;
        RECT  21.516 44.592 21.6 44.616 ;
    END
  END i[313]
  PIN i[314]
    DIRECTION INPUT ;
    USE SIGNAL ;
    PORT
      LAYER M4 ;
        RECT  21.516 44.688 21.6 44.712 ;
    END
  END i[314]
  PIN i[315]
    DIRECTION INPUT ;
    USE SIGNAL ;
    PORT
      LAYER M4 ;
        RECT  21.516 44.784 21.6 44.808 ;
    END
  END i[315]
  PIN i[316]
    DIRECTION INPUT ;
    USE SIGNAL ;
    PORT
      LAYER M4 ;
        RECT  21.516 44.88 21.6 44.904 ;
    END
  END i[316]
  PIN i[317]
    DIRECTION INPUT ;
    USE SIGNAL ;
    PORT
      LAYER M4 ;
        RECT  21.516 44.976 21.6 45 ;
    END
  END i[317]
  PIN i[318]
    DIRECTION INPUT ;
    USE SIGNAL ;
    PORT
      LAYER M4 ;
        RECT  21.516 45.072 21.6 45.096 ;
    END
  END i[318]
  PIN i[319]
    DIRECTION INPUT ;
    USE SIGNAL ;
    PORT
      LAYER M4 ;
        RECT  21.516 45.168 21.6 45.192 ;
    END
  END i[319]
  PIN i[31]
    DIRECTION INPUT ;
    USE SIGNAL ;
    PORT
      LAYER M4 ;
        RECT  21.516 22.896 21.6 22.92 ;
    END
  END i[31]
  PIN i[320]
    DIRECTION INPUT ;
    USE SIGNAL ;
    PORT
      LAYER M4 ;
        RECT  21.516 48.336 21.6 48.36 ;
    END
  END i[320]
  PIN i[321]
    DIRECTION INPUT ;
    USE SIGNAL ;
    PORT
      LAYER M4 ;
        RECT  21.516 48.432 21.6 48.456 ;
    END
  END i[321]
  PIN i[322]
    DIRECTION INPUT ;
    USE SIGNAL ;
    PORT
      LAYER M4 ;
        RECT  21.516 48.528 21.6 48.552 ;
    END
  END i[322]
  PIN i[323]
    DIRECTION INPUT ;
    USE SIGNAL ;
    PORT
      LAYER M4 ;
        RECT  21.516 48.624 21.6 48.648 ;
    END
  END i[323]
  PIN i[324]
    DIRECTION INPUT ;
    USE SIGNAL ;
    PORT
      LAYER M4 ;
        RECT  21.516 48.72 21.6 48.744 ;
    END
  END i[324]
  PIN i[325]
    DIRECTION INPUT ;
    USE SIGNAL ;
    PORT
      LAYER M4 ;
        RECT  21.516 48.816 21.6 48.84 ;
    END
  END i[325]
  PIN i[326]
    DIRECTION INPUT ;
    USE SIGNAL ;
    PORT
      LAYER M4 ;
        RECT  21.516 48.912 21.6 48.936 ;
    END
  END i[326]
  PIN i[327]
    DIRECTION INPUT ;
    USE SIGNAL ;
    PORT
      LAYER M4 ;
        RECT  21.516 49.008 21.6 49.032 ;
    END
  END i[327]
  PIN i[328]
    DIRECTION INPUT ;
    USE SIGNAL ;
    PORT
      LAYER M4 ;
        RECT  21.516 49.104 21.6 49.128 ;
    END
  END i[328]
  PIN i[329]
    DIRECTION INPUT ;
    USE SIGNAL ;
    PORT
      LAYER M4 ;
        RECT  21.516 49.2 21.6 49.224 ;
    END
  END i[329]
  PIN i[32]
    DIRECTION INPUT ;
    USE SIGNAL ;
    PORT
      LAYER M4 ;
        RECT  21.516 26.064 21.6 26.088 ;
    END
  END i[32]
  PIN i[330]
    DIRECTION INPUT ;
    USE SIGNAL ;
    PORT
      LAYER M4 ;
        RECT  21.516 49.296 21.6 49.32 ;
    END
  END i[330]
  PIN i[331]
    DIRECTION INPUT ;
    USE SIGNAL ;
    PORT
      LAYER M4 ;
        RECT  21.516 49.392 21.6 49.416 ;
    END
  END i[331]
  PIN i[332]
    DIRECTION INPUT ;
    USE SIGNAL ;
    PORT
      LAYER M4 ;
        RECT  21.516 49.488 21.6 49.512 ;
    END
  END i[332]
  PIN i[333]
    DIRECTION INPUT ;
    USE SIGNAL ;
    PORT
      LAYER M4 ;
        RECT  21.516 49.584 21.6 49.608 ;
    END
  END i[333]
  PIN i[334]
    DIRECTION INPUT ;
    USE SIGNAL ;
    PORT
      LAYER M4 ;
        RECT  21.516 49.68 21.6 49.704 ;
    END
  END i[334]
  PIN i[335]
    DIRECTION INPUT ;
    USE SIGNAL ;
    PORT
      LAYER M4 ;
        RECT  21.516 49.776 21.6 49.8 ;
    END
  END i[335]
  PIN i[336]
    DIRECTION INPUT ;
    USE SIGNAL ;
    PORT
      LAYER M4 ;
        RECT  21.516 49.872 21.6 49.896 ;
    END
  END i[336]
  PIN i[337]
    DIRECTION INPUT ;
    USE SIGNAL ;
    PORT
      LAYER M4 ;
        RECT  21.516 49.968 21.6 49.992 ;
    END
  END i[337]
  PIN i[338]
    DIRECTION INPUT ;
    USE SIGNAL ;
    PORT
      LAYER M4 ;
        RECT  21.516 50.064 21.6 50.088 ;
    END
  END i[338]
  PIN i[339]
    DIRECTION INPUT ;
    USE SIGNAL ;
    PORT
      LAYER M4 ;
        RECT  21.516 50.16 21.6 50.184 ;
    END
  END i[339]
  PIN i[33]
    DIRECTION INPUT ;
    USE SIGNAL ;
    PORT
      LAYER M4 ;
        RECT  21.516 26.16 21.6 26.184 ;
    END
  END i[33]
  PIN i[340]
    DIRECTION INPUT ;
    USE SIGNAL ;
    PORT
      LAYER M4 ;
        RECT  21.516 50.256 21.6 50.28 ;
    END
  END i[340]
  PIN i[341]
    DIRECTION INPUT ;
    USE SIGNAL ;
    PORT
      LAYER M4 ;
        RECT  21.516 50.352 21.6 50.376 ;
    END
  END i[341]
  PIN i[342]
    DIRECTION INPUT ;
    USE SIGNAL ;
    PORT
      LAYER M4 ;
        RECT  21.516 50.448 21.6 50.472 ;
    END
  END i[342]
  PIN i[343]
    DIRECTION INPUT ;
    USE SIGNAL ;
    PORT
      LAYER M4 ;
        RECT  21.516 50.544 21.6 50.568 ;
    END
  END i[343]
  PIN i[344]
    DIRECTION INPUT ;
    USE SIGNAL ;
    PORT
      LAYER M4 ;
        RECT  21.516 50.64 21.6 50.664 ;
    END
  END i[344]
  PIN i[345]
    DIRECTION INPUT ;
    USE SIGNAL ;
    PORT
      LAYER M4 ;
        RECT  21.516 50.736 21.6 50.76 ;
    END
  END i[345]
  PIN i[346]
    DIRECTION INPUT ;
    USE SIGNAL ;
    PORT
      LAYER M4 ;
        RECT  21.516 50.832 21.6 50.856 ;
    END
  END i[346]
  PIN i[347]
    DIRECTION INPUT ;
    USE SIGNAL ;
    PORT
      LAYER M4 ;
        RECT  21.516 50.928 21.6 50.952 ;
    END
  END i[347]
  PIN i[348]
    DIRECTION INPUT ;
    USE SIGNAL ;
    PORT
      LAYER M4 ;
        RECT  21.516 51.024 21.6 51.048 ;
    END
  END i[348]
  PIN i[349]
    DIRECTION INPUT ;
    USE SIGNAL ;
    PORT
      LAYER M4 ;
        RECT  21.516 51.12 21.6 51.144 ;
    END
  END i[349]
  PIN i[34]
    DIRECTION INPUT ;
    USE SIGNAL ;
    PORT
      LAYER M4 ;
        RECT  21.516 26.256 21.6 26.28 ;
    END
  END i[34]
  PIN i[350]
    DIRECTION INPUT ;
    USE SIGNAL ;
    PORT
      LAYER M4 ;
        RECT  21.516 51.216 21.6 51.24 ;
    END
  END i[350]
  PIN i[351]
    DIRECTION INPUT ;
    USE SIGNAL ;
    PORT
      LAYER M4 ;
        RECT  21.516 51.312 21.6 51.336 ;
    END
  END i[351]
  PIN i[352]
    DIRECTION INPUT ;
    USE SIGNAL ;
    PORT
      LAYER M4 ;
        RECT  21.516 51.408 21.6 51.432 ;
    END
  END i[352]
  PIN i[353]
    DIRECTION INPUT ;
    USE SIGNAL ;
    PORT
      LAYER M4 ;
        RECT  21.516 51.504 21.6 51.528 ;
    END
  END i[353]
  PIN i[354]
    DIRECTION INPUT ;
    USE SIGNAL ;
    PORT
      LAYER M4 ;
        RECT  21.516 51.6 21.6 51.624 ;
    END
  END i[354]
  PIN i[355]
    DIRECTION INPUT ;
    USE SIGNAL ;
    PORT
      LAYER M4 ;
        RECT  21.516 51.696 21.6 51.72 ;
    END
  END i[355]
  PIN i[356]
    DIRECTION INPUT ;
    USE SIGNAL ;
    PORT
      LAYER M4 ;
        RECT  21.516 51.792 21.6 51.816 ;
    END
  END i[356]
  PIN i[357]
    DIRECTION INPUT ;
    USE SIGNAL ;
    PORT
      LAYER M4 ;
        RECT  21.516 51.888 21.6 51.912 ;
    END
  END i[357]
  PIN i[358]
    DIRECTION INPUT ;
    USE SIGNAL ;
    PORT
      LAYER M4 ;
        RECT  21.516 51.984 21.6 52.008 ;
    END
  END i[358]
  PIN i[359]
    DIRECTION INPUT ;
    USE SIGNAL ;
    PORT
      LAYER M4 ;
        RECT  21.516 52.08 21.6 52.104 ;
    END
  END i[359]
  PIN i[35]
    DIRECTION INPUT ;
    USE SIGNAL ;
    PORT
      LAYER M4 ;
        RECT  21.516 26.352 21.6 26.376 ;
    END
  END i[35]
  PIN i[360]
    DIRECTION INPUT ;
    USE SIGNAL ;
    PORT
      LAYER M4 ;
        RECT  21.516 52.176 21.6 52.2 ;
    END
  END i[360]
  PIN i[361]
    DIRECTION INPUT ;
    USE SIGNAL ;
    PORT
      LAYER M4 ;
        RECT  21.516 52.272 21.6 52.296 ;
    END
  END i[361]
  PIN i[362]
    DIRECTION INPUT ;
    USE SIGNAL ;
    PORT
      LAYER M4 ;
        RECT  21.516 52.368 21.6 52.392 ;
    END
  END i[362]
  PIN i[363]
    DIRECTION INPUT ;
    USE SIGNAL ;
    PORT
      LAYER M4 ;
        RECT  21.516 52.464 21.6 52.488 ;
    END
  END i[363]
  PIN i[364]
    DIRECTION INPUT ;
    USE SIGNAL ;
    PORT
      LAYER M4 ;
        RECT  21.516 52.56 21.6 52.584 ;
    END
  END i[364]
  PIN i[365]
    DIRECTION INPUT ;
    USE SIGNAL ;
    PORT
      LAYER M4 ;
        RECT  21.516 52.656 21.6 52.68 ;
    END
  END i[365]
  PIN i[366]
    DIRECTION INPUT ;
    USE SIGNAL ;
    PORT
      LAYER M4 ;
        RECT  21.516 52.752 21.6 52.776 ;
    END
  END i[366]
  PIN i[367]
    DIRECTION INPUT ;
    USE SIGNAL ;
    PORT
      LAYER M4 ;
        RECT  21.516 52.848 21.6 52.872 ;
    END
  END i[367]
  PIN i[368]
    DIRECTION INPUT ;
    USE SIGNAL ;
    PORT
      LAYER M4 ;
        RECT  21.516 52.944 21.6 52.968 ;
    END
  END i[368]
  PIN i[369]
    DIRECTION INPUT ;
    USE SIGNAL ;
    PORT
      LAYER M4 ;
        RECT  21.516 53.04 21.6 53.064 ;
    END
  END i[369]
  PIN i[36]
    DIRECTION INPUT ;
    USE SIGNAL ;
    PORT
      LAYER M4 ;
        RECT  21.516 26.448 21.6 26.472 ;
    END
  END i[36]
  PIN i[370]
    DIRECTION INPUT ;
    USE SIGNAL ;
    PORT
      LAYER M4 ;
        RECT  21.516 53.136 21.6 53.16 ;
    END
  END i[370]
  PIN i[371]
    DIRECTION INPUT ;
    USE SIGNAL ;
    PORT
      LAYER M4 ;
        RECT  21.516 53.232 21.6 53.256 ;
    END
  END i[371]
  PIN i[372]
    DIRECTION INPUT ;
    USE SIGNAL ;
    PORT
      LAYER M4 ;
        RECT  21.516 53.328 21.6 53.352 ;
    END
  END i[372]
  PIN i[373]
    DIRECTION INPUT ;
    USE SIGNAL ;
    PORT
      LAYER M4 ;
        RECT  21.516 53.424 21.6 53.448 ;
    END
  END i[373]
  PIN i[374]
    DIRECTION INPUT ;
    USE SIGNAL ;
    PORT
      LAYER M4 ;
        RECT  21.516 53.52 21.6 53.544 ;
    END
  END i[374]
  PIN i[375]
    DIRECTION INPUT ;
    USE SIGNAL ;
    PORT
      LAYER M4 ;
        RECT  21.516 53.616 21.6 53.64 ;
    END
  END i[375]
  PIN i[376]
    DIRECTION INPUT ;
    USE SIGNAL ;
    PORT
      LAYER M4 ;
        RECT  21.516 53.712 21.6 53.736 ;
    END
  END i[376]
  PIN i[377]
    DIRECTION INPUT ;
    USE SIGNAL ;
    PORT
      LAYER M4 ;
        RECT  21.516 53.808 21.6 53.832 ;
    END
  END i[377]
  PIN i[378]
    DIRECTION INPUT ;
    USE SIGNAL ;
    PORT
      LAYER M4 ;
        RECT  21.516 53.904 21.6 53.928 ;
    END
  END i[378]
  PIN i[379]
    DIRECTION INPUT ;
    USE SIGNAL ;
    PORT
      LAYER M4 ;
        RECT  21.516 54 21.6 54.024 ;
    END
  END i[379]
  PIN i[37]
    DIRECTION INPUT ;
    USE SIGNAL ;
    PORT
      LAYER M4 ;
        RECT  21.516 26.544 21.6 26.568 ;
    END
  END i[37]
  PIN i[380]
    DIRECTION INPUT ;
    USE SIGNAL ;
    PORT
      LAYER M4 ;
        RECT  21.516 54.096 21.6 54.12 ;
    END
  END i[380]
  PIN i[381]
    DIRECTION INPUT ;
    USE SIGNAL ;
    PORT
      LAYER M4 ;
        RECT  21.516 54.192 21.6 54.216 ;
    END
  END i[381]
  PIN i[382]
    DIRECTION INPUT ;
    USE SIGNAL ;
    PORT
      LAYER M4 ;
        RECT  21.516 54.288 21.6 54.312 ;
    END
  END i[382]
  PIN i[383]
    DIRECTION INPUT ;
    USE SIGNAL ;
    PORT
      LAYER M4 ;
        RECT  21.516 54.384 21.6 54.408 ;
    END
  END i[383]
  PIN i[384]
    DIRECTION INPUT ;
    USE SIGNAL ;
    PORT
      LAYER M4 ;
        RECT  21.516 54.48 21.6 54.504 ;
    END
  END i[384]
  PIN i[385]
    DIRECTION INPUT ;
    USE SIGNAL ;
    PORT
      LAYER M4 ;
        RECT  21.516 54.576 21.6 54.6 ;
    END
  END i[385]
  PIN i[386]
    DIRECTION INPUT ;
    USE SIGNAL ;
    PORT
      LAYER M4 ;
        RECT  21.516 54.672 21.6 54.696 ;
    END
  END i[386]
  PIN i[387]
    DIRECTION INPUT ;
    USE SIGNAL ;
    PORT
      LAYER M4 ;
        RECT  21.516 54.768 21.6 54.792 ;
    END
  END i[387]
  PIN i[388]
    DIRECTION INPUT ;
    USE SIGNAL ;
    PORT
      LAYER M4 ;
        RECT  21.516 54.864 21.6 54.888 ;
    END
  END i[388]
  PIN i[389]
    DIRECTION INPUT ;
    USE SIGNAL ;
    PORT
      LAYER M4 ;
        RECT  21.516 54.96 21.6 54.984 ;
    END
  END i[389]
  PIN i[38]
    DIRECTION INPUT ;
    USE SIGNAL ;
    PORT
      LAYER M4 ;
        RECT  21.516 26.64 21.6 26.664 ;
    END
  END i[38]
  PIN i[390]
    DIRECTION INPUT ;
    USE SIGNAL ;
    PORT
      LAYER M4 ;
        RECT  21.516 55.056 21.6 55.08 ;
    END
  END i[390]
  PIN i[391]
    DIRECTION INPUT ;
    USE SIGNAL ;
    PORT
      LAYER M4 ;
        RECT  21.516 55.152 21.6 55.176 ;
    END
  END i[391]
  PIN i[392]
    DIRECTION INPUT ;
    USE SIGNAL ;
    PORT
      LAYER M4 ;
        RECT  21.516 55.248 21.6 55.272 ;
    END
  END i[392]
  PIN i[393]
    DIRECTION INPUT ;
    USE SIGNAL ;
    PORT
      LAYER M4 ;
        RECT  21.516 55.344 21.6 55.368 ;
    END
  END i[393]
  PIN i[394]
    DIRECTION INPUT ;
    USE SIGNAL ;
    PORT
      LAYER M4 ;
        RECT  21.516 55.44 21.6 55.464 ;
    END
  END i[394]
  PIN i[395]
    DIRECTION INPUT ;
    USE SIGNAL ;
    PORT
      LAYER M4 ;
        RECT  21.516 55.536 21.6 55.56 ;
    END
  END i[395]
  PIN i[396]
    DIRECTION INPUT ;
    USE SIGNAL ;
    PORT
      LAYER M4 ;
        RECT  21.516 55.632 21.6 55.656 ;
    END
  END i[396]
  PIN i[397]
    DIRECTION INPUT ;
    USE SIGNAL ;
    PORT
      LAYER M4 ;
        RECT  21.516 55.728 21.6 55.752 ;
    END
  END i[397]
  PIN i[398]
    DIRECTION INPUT ;
    USE SIGNAL ;
    PORT
      LAYER M4 ;
        RECT  21.516 55.824 21.6 55.848 ;
    END
  END i[398]
  PIN i[399]
    DIRECTION INPUT ;
    USE SIGNAL ;
    PORT
      LAYER M4 ;
        RECT  21.516 55.92 21.6 55.944 ;
    END
  END i[399]
  PIN i[39]
    DIRECTION INPUT ;
    USE SIGNAL ;
    PORT
      LAYER M4 ;
        RECT  21.516 26.736 21.6 26.76 ;
    END
  END i[39]
  PIN i[3]
    DIRECTION INPUT ;
    USE SIGNAL ;
    PORT
      LAYER M4 ;
        RECT  21.516 20.208 21.6 20.232 ;
    END
  END i[3]
  PIN i[400]
    DIRECTION INPUT ;
    USE SIGNAL ;
    PORT
      LAYER M4 ;
        RECT  21.516 56.016 21.6 56.04 ;
    END
  END i[400]
  PIN i[401]
    DIRECTION INPUT ;
    USE SIGNAL ;
    PORT
      LAYER M4 ;
        RECT  21.516 56.112 21.6 56.136 ;
    END
  END i[401]
  PIN i[402]
    DIRECTION INPUT ;
    USE SIGNAL ;
    PORT
      LAYER M4 ;
        RECT  21.516 56.208 21.6 56.232 ;
    END
  END i[402]
  PIN i[403]
    DIRECTION INPUT ;
    USE SIGNAL ;
    PORT
      LAYER M4 ;
        RECT  21.516 56.304 21.6 56.328 ;
    END
  END i[403]
  PIN i[404]
    DIRECTION INPUT ;
    USE SIGNAL ;
    PORT
      LAYER M4 ;
        RECT  21.516 56.4 21.6 56.424 ;
    END
  END i[404]
  PIN i[405]
    DIRECTION INPUT ;
    USE SIGNAL ;
    PORT
      LAYER M4 ;
        RECT  21.516 56.496 21.6 56.52 ;
    END
  END i[405]
  PIN i[406]
    DIRECTION INPUT ;
    USE SIGNAL ;
    PORT
      LAYER M4 ;
        RECT  21.516 56.592 21.6 56.616 ;
    END
  END i[406]
  PIN i[407]
    DIRECTION INPUT ;
    USE SIGNAL ;
    PORT
      LAYER M4 ;
        RECT  21.516 56.688 21.6 56.712 ;
    END
  END i[407]
  PIN i[408]
    DIRECTION INPUT ;
    USE SIGNAL ;
    PORT
      LAYER M4 ;
        RECT  21.516 56.784 21.6 56.808 ;
    END
  END i[408]
  PIN i[409]
    DIRECTION INPUT ;
    USE SIGNAL ;
    PORT
      LAYER M4 ;
        RECT  21.516 56.88 21.6 56.904 ;
    END
  END i[409]
  PIN i[40]
    DIRECTION INPUT ;
    USE SIGNAL ;
    PORT
      LAYER M4 ;
        RECT  21.516 26.832 21.6 26.856 ;
    END
  END i[40]
  PIN i[410]
    DIRECTION INPUT ;
    USE SIGNAL ;
    PORT
      LAYER M4 ;
        RECT  21.516 56.976 21.6 57 ;
    END
  END i[410]
  PIN i[411]
    DIRECTION INPUT ;
    USE SIGNAL ;
    PORT
      LAYER M4 ;
        RECT  21.516 57.072 21.6 57.096 ;
    END
  END i[411]
  PIN i[412]
    DIRECTION INPUT ;
    USE SIGNAL ;
    PORT
      LAYER M4 ;
        RECT  21.516 57.168 21.6 57.192 ;
    END
  END i[412]
  PIN i[413]
    DIRECTION INPUT ;
    USE SIGNAL ;
    PORT
      LAYER M4 ;
        RECT  21.516 57.264 21.6 57.288 ;
    END
  END i[413]
  PIN i[414]
    DIRECTION INPUT ;
    USE SIGNAL ;
    PORT
      LAYER M4 ;
        RECT  21.516 57.36 21.6 57.384 ;
    END
  END i[414]
  PIN i[415]
    DIRECTION INPUT ;
    USE SIGNAL ;
    PORT
      LAYER M4 ;
        RECT  21.516 57.456 21.6 57.48 ;
    END
  END i[415]
  PIN i[416]
    DIRECTION INPUT ;
    USE SIGNAL ;
    PORT
      LAYER M4 ;
        RECT  21.516 45.264 21.6 45.288 ;
    END
  END i[416]
  PIN i[417]
    DIRECTION INPUT ;
    USE SIGNAL ;
    PORT
      LAYER M4 ;
        RECT  21.516 45.36 21.6 45.384 ;
    END
  END i[417]
  PIN i[418]
    DIRECTION INPUT ;
    USE SIGNAL ;
    PORT
      LAYER M4 ;
        RECT  21.516 45.456 21.6 45.48 ;
    END
  END i[418]
  PIN i[419]
    DIRECTION INPUT ;
    USE SIGNAL ;
    PORT
      LAYER M4 ;
        RECT  21.516 45.552 21.6 45.576 ;
    END
  END i[419]
  PIN i[41]
    DIRECTION INPUT ;
    USE SIGNAL ;
    PORT
      LAYER M4 ;
        RECT  21.516 26.928 21.6 26.952 ;
    END
  END i[41]
  PIN i[420]
    DIRECTION INPUT ;
    USE SIGNAL ;
    PORT
      LAYER M4 ;
        RECT  21.516 45.648 21.6 45.672 ;
    END
  END i[420]
  PIN i[421]
    DIRECTION INPUT ;
    USE SIGNAL ;
    PORT
      LAYER M4 ;
        RECT  21.516 45.744 21.6 45.768 ;
    END
  END i[421]
  PIN i[422]
    DIRECTION INPUT ;
    USE SIGNAL ;
    PORT
      LAYER M4 ;
        RECT  21.516 45.84 21.6 45.864 ;
    END
  END i[422]
  PIN i[423]
    DIRECTION INPUT ;
    USE SIGNAL ;
    PORT
      LAYER M4 ;
        RECT  21.516 45.936 21.6 45.96 ;
    END
  END i[423]
  PIN i[424]
    DIRECTION INPUT ;
    USE SIGNAL ;
    PORT
      LAYER M4 ;
        RECT  21.516 46.032 21.6 46.056 ;
    END
  END i[424]
  PIN i[425]
    DIRECTION INPUT ;
    USE SIGNAL ;
    PORT
      LAYER M4 ;
        RECT  21.516 46.128 21.6 46.152 ;
    END
  END i[425]
  PIN i[426]
    DIRECTION INPUT ;
    USE SIGNAL ;
    PORT
      LAYER M4 ;
        RECT  21.516 46.224 21.6 46.248 ;
    END
  END i[426]
  PIN i[427]
    DIRECTION INPUT ;
    USE SIGNAL ;
    PORT
      LAYER M4 ;
        RECT  21.516 46.32 21.6 46.344 ;
    END
  END i[427]
  PIN i[428]
    DIRECTION INPUT ;
    USE SIGNAL ;
    PORT
      LAYER M4 ;
        RECT  21.516 46.416 21.6 46.44 ;
    END
  END i[428]
  PIN i[429]
    DIRECTION INPUT ;
    USE SIGNAL ;
    PORT
      LAYER M4 ;
        RECT  21.516 46.512 21.6 46.536 ;
    END
  END i[429]
  PIN i[42]
    DIRECTION INPUT ;
    USE SIGNAL ;
    PORT
      LAYER M4 ;
        RECT  21.516 27.024 21.6 27.048 ;
    END
  END i[42]
  PIN i[430]
    DIRECTION INPUT ;
    USE SIGNAL ;
    PORT
      LAYER M4 ;
        RECT  21.516 46.608 21.6 46.632 ;
    END
  END i[430]
  PIN i[431]
    DIRECTION INPUT ;
    USE SIGNAL ;
    PORT
      LAYER M4 ;
        RECT  21.516 46.704 21.6 46.728 ;
    END
  END i[431]
  PIN i[432]
    DIRECTION INPUT ;
    USE SIGNAL ;
    PORT
      LAYER M4 ;
        RECT  21.516 46.8 21.6 46.824 ;
    END
  END i[432]
  PIN i[433]
    DIRECTION INPUT ;
    USE SIGNAL ;
    PORT
      LAYER M4 ;
        RECT  21.516 46.896 21.6 46.92 ;
    END
  END i[433]
  PIN i[434]
    DIRECTION INPUT ;
    USE SIGNAL ;
    PORT
      LAYER M4 ;
        RECT  21.516 46.992 21.6 47.016 ;
    END
  END i[434]
  PIN i[435]
    DIRECTION INPUT ;
    USE SIGNAL ;
    PORT
      LAYER M4 ;
        RECT  21.516 47.088 21.6 47.112 ;
    END
  END i[435]
  PIN i[436]
    DIRECTION INPUT ;
    USE SIGNAL ;
    PORT
      LAYER M4 ;
        RECT  21.516 47.184 21.6 47.208 ;
    END
  END i[436]
  PIN i[437]
    DIRECTION INPUT ;
    USE SIGNAL ;
    PORT
      LAYER M4 ;
        RECT  21.516 47.28 21.6 47.304 ;
    END
  END i[437]
  PIN i[438]
    DIRECTION INPUT ;
    USE SIGNAL ;
    PORT
      LAYER M4 ;
        RECT  21.516 47.376 21.6 47.4 ;
    END
  END i[438]
  PIN i[439]
    DIRECTION INPUT ;
    USE SIGNAL ;
    PORT
      LAYER M4 ;
        RECT  21.516 47.472 21.6 47.496 ;
    END
  END i[439]
  PIN i[43]
    DIRECTION INPUT ;
    USE SIGNAL ;
    PORT
      LAYER M4 ;
        RECT  21.516 27.12 21.6 27.144 ;
    END
  END i[43]
  PIN i[440]
    DIRECTION INPUT ;
    USE SIGNAL ;
    PORT
      LAYER M4 ;
        RECT  21.516 47.568 21.6 47.592 ;
    END
  END i[440]
  PIN i[441]
    DIRECTION INPUT ;
    USE SIGNAL ;
    PORT
      LAYER M4 ;
        RECT  21.516 47.664 21.6 47.688 ;
    END
  END i[441]
  PIN i[442]
    DIRECTION INPUT ;
    USE SIGNAL ;
    PORT
      LAYER M4 ;
        RECT  21.516 47.76 21.6 47.784 ;
    END
  END i[442]
  PIN i[443]
    DIRECTION INPUT ;
    USE SIGNAL ;
    PORT
      LAYER M4 ;
        RECT  21.516 47.856 21.6 47.88 ;
    END
  END i[443]
  PIN i[444]
    DIRECTION INPUT ;
    USE SIGNAL ;
    PORT
      LAYER M4 ;
        RECT  21.516 47.952 21.6 47.976 ;
    END
  END i[444]
  PIN i[445]
    DIRECTION INPUT ;
    USE SIGNAL ;
    PORT
      LAYER M4 ;
        RECT  21.516 48.048 21.6 48.072 ;
    END
  END i[445]
  PIN i[446]
    DIRECTION INPUT ;
    USE SIGNAL ;
    PORT
      LAYER M4 ;
        RECT  21.516 48.144 21.6 48.168 ;
    END
  END i[446]
  PIN i[447]
    DIRECTION INPUT ;
    USE SIGNAL ;
    PORT
      LAYER M4 ;
        RECT  21.516 48.24 21.6 48.264 ;
    END
  END i[447]
  PIN i[448]
    DIRECTION INPUT ;
    USE SIGNAL ;
    PORT
      LAYER M4 ;
        RECT  21.516 58.32 21.6 58.344 ;
    END
  END i[448]
  PIN i[449]
    DIRECTION INPUT ;
    USE SIGNAL ;
    PORT
      LAYER M4 ;
        RECT  21.516 58.416 21.6 58.44 ;
    END
  END i[449]
  PIN i[44]
    DIRECTION INPUT ;
    USE SIGNAL ;
    PORT
      LAYER M4 ;
        RECT  21.516 27.216 21.6 27.24 ;
    END
  END i[44]
  PIN i[450]
    DIRECTION INPUT ;
    USE SIGNAL ;
    PORT
      LAYER M4 ;
        RECT  21.516 58.512 21.6 58.536 ;
    END
  END i[450]
  PIN i[451]
    DIRECTION INPUT ;
    USE SIGNAL ;
    PORT
      LAYER M4 ;
        RECT  21.516 58.608 21.6 58.632 ;
    END
  END i[451]
  PIN i[452]
    DIRECTION INPUT ;
    USE SIGNAL ;
    PORT
      LAYER M4 ;
        RECT  21.516 58.704 21.6 58.728 ;
    END
  END i[452]
  PIN i[453]
    DIRECTION INPUT ;
    USE SIGNAL ;
    PORT
      LAYER M4 ;
        RECT  21.516 58.8 21.6 58.824 ;
    END
  END i[453]
  PIN i[454]
    DIRECTION INPUT ;
    USE SIGNAL ;
    PORT
      LAYER M4 ;
        RECT  21.516 58.896 21.6 58.92 ;
    END
  END i[454]
  PIN i[455]
    DIRECTION INPUT ;
    USE SIGNAL ;
    PORT
      LAYER M4 ;
        RECT  21.516 58.992 21.6 59.016 ;
    END
  END i[455]
  PIN i[456]
    DIRECTION INPUT ;
    USE SIGNAL ;
    PORT
      LAYER M4 ;
        RECT  21.516 59.088 21.6 59.112 ;
    END
  END i[456]
  PIN i[457]
    DIRECTION INPUT ;
    USE SIGNAL ;
    PORT
      LAYER M4 ;
        RECT  21.516 59.184 21.6 59.208 ;
    END
  END i[457]
  PIN i[458]
    DIRECTION INPUT ;
    USE SIGNAL ;
    PORT
      LAYER M4 ;
        RECT  21.516 59.28 21.6 59.304 ;
    END
  END i[458]
  PIN i[459]
    DIRECTION INPUT ;
    USE SIGNAL ;
    PORT
      LAYER M4 ;
        RECT  21.516 59.376 21.6 59.4 ;
    END
  END i[459]
  PIN i[45]
    DIRECTION INPUT ;
    USE SIGNAL ;
    PORT
      LAYER M4 ;
        RECT  21.516 27.312 21.6 27.336 ;
    END
  END i[45]
  PIN i[460]
    DIRECTION INPUT ;
    USE SIGNAL ;
    PORT
      LAYER M4 ;
        RECT  21.516 59.472 21.6 59.496 ;
    END
  END i[460]
  PIN i[461]
    DIRECTION INPUT ;
    USE SIGNAL ;
    PORT
      LAYER M4 ;
        RECT  21.516 59.568 21.6 59.592 ;
    END
  END i[461]
  PIN i[462]
    DIRECTION INPUT ;
    USE SIGNAL ;
    PORT
      LAYER M4 ;
        RECT  21.516 59.664 21.6 59.688 ;
    END
  END i[462]
  PIN i[463]
    DIRECTION INPUT ;
    USE SIGNAL ;
    PORT
      LAYER M4 ;
        RECT  21.516 59.76 21.6 59.784 ;
    END
  END i[463]
  PIN i[464]
    DIRECTION INPUT ;
    USE SIGNAL ;
    PORT
      LAYER M4 ;
        RECT  21.516 59.856 21.6 59.88 ;
    END
  END i[464]
  PIN i[465]
    DIRECTION INPUT ;
    USE SIGNAL ;
    PORT
      LAYER M4 ;
        RECT  21.516 59.952 21.6 59.976 ;
    END
  END i[465]
  PIN i[466]
    DIRECTION INPUT ;
    USE SIGNAL ;
    PORT
      LAYER M4 ;
        RECT  21.516 60.048 21.6 60.072 ;
    END
  END i[466]
  PIN i[467]
    DIRECTION INPUT ;
    USE SIGNAL ;
    PORT
      LAYER M4 ;
        RECT  21.516 60.144 21.6 60.168 ;
    END
  END i[467]
  PIN i[468]
    DIRECTION INPUT ;
    USE SIGNAL ;
    PORT
      LAYER M4 ;
        RECT  21.516 60.24 21.6 60.264 ;
    END
  END i[468]
  PIN i[469]
    DIRECTION INPUT ;
    USE SIGNAL ;
    PORT
      LAYER M4 ;
        RECT  21.516 60.336 21.6 60.36 ;
    END
  END i[469]
  PIN i[46]
    DIRECTION INPUT ;
    USE SIGNAL ;
    PORT
      LAYER M4 ;
        RECT  21.516 27.408 21.6 27.432 ;
    END
  END i[46]
  PIN i[470]
    DIRECTION INPUT ;
    USE SIGNAL ;
    PORT
      LAYER M4 ;
        RECT  21.516 60.432 21.6 60.456 ;
    END
  END i[470]
  PIN i[471]
    DIRECTION INPUT ;
    USE SIGNAL ;
    PORT
      LAYER M4 ;
        RECT  21.516 60.528 21.6 60.552 ;
    END
  END i[471]
  PIN i[472]
    DIRECTION INPUT ;
    USE SIGNAL ;
    PORT
      LAYER M4 ;
        RECT  21.516 60.624 21.6 60.648 ;
    END
  END i[472]
  PIN i[473]
    DIRECTION INPUT ;
    USE SIGNAL ;
    PORT
      LAYER M4 ;
        RECT  21.516 60.72 21.6 60.744 ;
    END
  END i[473]
  PIN i[474]
    DIRECTION INPUT ;
    USE SIGNAL ;
    PORT
      LAYER M4 ;
        RECT  21.516 60.816 21.6 60.84 ;
    END
  END i[474]
  PIN i[475]
    DIRECTION INPUT ;
    USE SIGNAL ;
    PORT
      LAYER M4 ;
        RECT  21.516 60.912 21.6 60.936 ;
    END
  END i[475]
  PIN i[476]
    DIRECTION INPUT ;
    USE SIGNAL ;
    PORT
      LAYER M4 ;
        RECT  21.516 61.008 21.6 61.032 ;
    END
  END i[476]
  PIN i[477]
    DIRECTION INPUT ;
    USE SIGNAL ;
    PORT
      LAYER M4 ;
        RECT  21.516 61.104 21.6 61.128 ;
    END
  END i[477]
  PIN i[478]
    DIRECTION INPUT ;
    USE SIGNAL ;
    PORT
      LAYER M4 ;
        RECT  21.516 61.2 21.6 61.224 ;
    END
  END i[478]
  PIN i[479]
    DIRECTION INPUT ;
    USE SIGNAL ;
    PORT
      LAYER M4 ;
        RECT  21.516 61.296 21.6 61.32 ;
    END
  END i[479]
  PIN i[47]
    DIRECTION INPUT ;
    USE SIGNAL ;
    PORT
      LAYER M4 ;
        RECT  21.516 27.504 21.6 27.528 ;
    END
  END i[47]
  PIN i[480]
    DIRECTION INPUT ;
    USE SIGNAL ;
    PORT
      LAYER M4 ;
        RECT  21.516 16.08 21.6 16.104 ;
    END
  END i[480]
  PIN i[481]
    DIRECTION INPUT ;
    USE SIGNAL ;
    PORT
      LAYER M4 ;
        RECT  21.516 16.176 21.6 16.2 ;
    END
  END i[481]
  PIN i[482]
    DIRECTION INPUT ;
    USE SIGNAL ;
    PORT
      LAYER M4 ;
        RECT  21.516 16.272 21.6 16.296 ;
    END
  END i[482]
  PIN i[483]
    DIRECTION INPUT ;
    USE SIGNAL ;
    PORT
      LAYER M4 ;
        RECT  21.516 16.368 21.6 16.392 ;
    END
  END i[483]
  PIN i[484]
    DIRECTION INPUT ;
    USE SIGNAL ;
    PORT
      LAYER M4 ;
        RECT  21.516 16.464 21.6 16.488 ;
    END
  END i[484]
  PIN i[485]
    DIRECTION INPUT ;
    USE SIGNAL ;
    PORT
      LAYER M4 ;
        RECT  21.516 16.56 21.6 16.584 ;
    END
  END i[485]
  PIN i[486]
    DIRECTION INPUT ;
    USE SIGNAL ;
    PORT
      LAYER M4 ;
        RECT  21.516 16.656 21.6 16.68 ;
    END
  END i[486]
  PIN i[487]
    DIRECTION INPUT ;
    USE SIGNAL ;
    PORT
      LAYER M4 ;
        RECT  21.516 16.752 21.6 16.776 ;
    END
  END i[487]
  PIN i[488]
    DIRECTION INPUT ;
    USE SIGNAL ;
    PORT
      LAYER M4 ;
        RECT  21.516 16.848 21.6 16.872 ;
    END
  END i[488]
  PIN i[489]
    DIRECTION INPUT ;
    USE SIGNAL ;
    PORT
      LAYER M4 ;
        RECT  21.516 16.944 21.6 16.968 ;
    END
  END i[489]
  PIN i[48]
    DIRECTION INPUT ;
    USE SIGNAL ;
    PORT
      LAYER M4 ;
        RECT  21.516 27.6 21.6 27.624 ;
    END
  END i[48]
  PIN i[490]
    DIRECTION INPUT ;
    USE SIGNAL ;
    PORT
      LAYER M4 ;
        RECT  21.516 17.04 21.6 17.064 ;
    END
  END i[490]
  PIN i[491]
    DIRECTION INPUT ;
    USE SIGNAL ;
    PORT
      LAYER M4 ;
        RECT  21.516 17.136 21.6 17.16 ;
    END
  END i[491]
  PIN i[492]
    DIRECTION INPUT ;
    USE SIGNAL ;
    PORT
      LAYER M4 ;
        RECT  21.516 17.232 21.6 17.256 ;
    END
  END i[492]
  PIN i[493]
    DIRECTION INPUT ;
    USE SIGNAL ;
    PORT
      LAYER M4 ;
        RECT  21.516 17.328 21.6 17.352 ;
    END
  END i[493]
  PIN i[494]
    DIRECTION INPUT ;
    USE SIGNAL ;
    PORT
      LAYER M4 ;
        RECT  21.516 17.424 21.6 17.448 ;
    END
  END i[494]
  PIN i[495]
    DIRECTION INPUT ;
    USE SIGNAL ;
    PORT
      LAYER M4 ;
        RECT  21.516 17.52 21.6 17.544 ;
    END
  END i[495]
  PIN i[496]
    DIRECTION INPUT ;
    USE SIGNAL ;
    PORT
      LAYER M4 ;
        RECT  21.516 17.616 21.6 17.64 ;
    END
  END i[496]
  PIN i[497]
    DIRECTION INPUT ;
    USE SIGNAL ;
    PORT
      LAYER M4 ;
        RECT  21.516 17.712 21.6 17.736 ;
    END
  END i[497]
  PIN i[498]
    DIRECTION INPUT ;
    USE SIGNAL ;
    PORT
      LAYER M4 ;
        RECT  21.516 17.808 21.6 17.832 ;
    END
  END i[498]
  PIN i[499]
    DIRECTION INPUT ;
    USE SIGNAL ;
    PORT
      LAYER M4 ;
        RECT  21.516 17.904 21.6 17.928 ;
    END
  END i[499]
  PIN i[49]
    DIRECTION INPUT ;
    USE SIGNAL ;
    PORT
      LAYER M4 ;
        RECT  21.516 27.696 21.6 27.72 ;
    END
  END i[49]
  PIN i[4]
    DIRECTION INPUT ;
    USE SIGNAL ;
    PORT
      LAYER M4 ;
        RECT  21.516 20.304 21.6 20.328 ;
    END
  END i[4]
  PIN i[500]
    DIRECTION INPUT ;
    USE SIGNAL ;
    PORT
      LAYER M4 ;
        RECT  21.516 18 21.6 18.024 ;
    END
  END i[500]
  PIN i[501]
    DIRECTION INPUT ;
    USE SIGNAL ;
    PORT
      LAYER M4 ;
        RECT  21.516 18.096 21.6 18.12 ;
    END
  END i[501]
  PIN i[502]
    DIRECTION INPUT ;
    USE SIGNAL ;
    PORT
      LAYER M4 ;
        RECT  21.516 18.192 21.6 18.216 ;
    END
  END i[502]
  PIN i[503]
    DIRECTION INPUT ;
    USE SIGNAL ;
    PORT
      LAYER M4 ;
        RECT  21.516 18.288 21.6 18.312 ;
    END
  END i[503]
  PIN i[504]
    DIRECTION INPUT ;
    USE SIGNAL ;
    PORT
      LAYER M4 ;
        RECT  21.516 18.384 21.6 18.408 ;
    END
  END i[504]
  PIN i[505]
    DIRECTION INPUT ;
    USE SIGNAL ;
    PORT
      LAYER M4 ;
        RECT  21.516 18.48 21.6 18.504 ;
    END
  END i[505]
  PIN i[506]
    DIRECTION INPUT ;
    USE SIGNAL ;
    PORT
      LAYER M4 ;
        RECT  21.516 18.576 21.6 18.6 ;
    END
  END i[506]
  PIN i[507]
    DIRECTION INPUT ;
    USE SIGNAL ;
    PORT
      LAYER M4 ;
        RECT  21.516 18.672 21.6 18.696 ;
    END
  END i[507]
  PIN i[508]
    DIRECTION INPUT ;
    USE SIGNAL ;
    PORT
      LAYER M4 ;
        RECT  21.516 18.768 21.6 18.792 ;
    END
  END i[508]
  PIN i[509]
    DIRECTION INPUT ;
    USE SIGNAL ;
    PORT
      LAYER M4 ;
        RECT  21.516 18.864 21.6 18.888 ;
    END
  END i[509]
  PIN i[50]
    DIRECTION INPUT ;
    USE SIGNAL ;
    PORT
      LAYER M4 ;
        RECT  21.516 27.792 21.6 27.816 ;
    END
  END i[50]
  PIN i[510]
    DIRECTION INPUT ;
    USE SIGNAL ;
    PORT
      LAYER M4 ;
        RECT  21.516 18.96 21.6 18.984 ;
    END
  END i[510]
  PIN i[511]
    DIRECTION INPUT ;
    USE SIGNAL ;
    PORT
      LAYER M4 ;
        RECT  21.516 19.056 21.6 19.08 ;
    END
  END i[511]
  PIN i[512]
    DIRECTION INPUT ;
    USE SIGNAL ;
    PORT
      LAYER M4 ;
        RECT  21.516 0.72 21.6 0.744 ;
    END
  END i[512]
  PIN i[513]
    DIRECTION INPUT ;
    USE SIGNAL ;
    PORT
      LAYER M4 ;
        RECT  21.516 0.816 21.6 0.84 ;
    END
  END i[513]
  PIN i[514]
    DIRECTION INPUT ;
    USE SIGNAL ;
    PORT
      LAYER M4 ;
        RECT  21.516 0.912 21.6 0.936 ;
    END
  END i[514]
  PIN i[515]
    DIRECTION INPUT ;
    USE SIGNAL ;
    PORT
      LAYER M4 ;
        RECT  21.516 1.008 21.6 1.032 ;
    END
  END i[515]
  PIN i[516]
    DIRECTION INPUT ;
    USE SIGNAL ;
    PORT
      LAYER M4 ;
        RECT  21.516 1.104 21.6 1.128 ;
    END
  END i[516]
  PIN i[517]
    DIRECTION INPUT ;
    USE SIGNAL ;
    PORT
      LAYER M4 ;
        RECT  21.516 1.2 21.6 1.224 ;
    END
  END i[517]
  PIN i[518]
    DIRECTION INPUT ;
    USE SIGNAL ;
    PORT
      LAYER M4 ;
        RECT  21.516 1.296 21.6 1.32 ;
    END
  END i[518]
  PIN i[519]
    DIRECTION INPUT ;
    USE SIGNAL ;
    PORT
      LAYER M4 ;
        RECT  21.516 1.392 21.6 1.416 ;
    END
  END i[519]
  PIN i[51]
    DIRECTION INPUT ;
    USE SIGNAL ;
    PORT
      LAYER M4 ;
        RECT  21.516 27.888 21.6 27.912 ;
    END
  END i[51]
  PIN i[520]
    DIRECTION INPUT ;
    USE SIGNAL ;
    PORT
      LAYER M4 ;
        RECT  21.516 1.488 21.6 1.512 ;
    END
  END i[520]
  PIN i[521]
    DIRECTION INPUT ;
    USE SIGNAL ;
    PORT
      LAYER M4 ;
        RECT  21.516 1.584 21.6 1.608 ;
    END
  END i[521]
  PIN i[522]
    DIRECTION INPUT ;
    USE SIGNAL ;
    PORT
      LAYER M4 ;
        RECT  21.516 1.68 21.6 1.704 ;
    END
  END i[522]
  PIN i[523]
    DIRECTION INPUT ;
    USE SIGNAL ;
    PORT
      LAYER M4 ;
        RECT  21.516 1.776 21.6 1.8 ;
    END
  END i[523]
  PIN i[524]
    DIRECTION INPUT ;
    USE SIGNAL ;
    PORT
      LAYER M4 ;
        RECT  21.516 1.872 21.6 1.896 ;
    END
  END i[524]
  PIN i[525]
    DIRECTION INPUT ;
    USE SIGNAL ;
    PORT
      LAYER M4 ;
        RECT  21.516 1.968 21.6 1.992 ;
    END
  END i[525]
  PIN i[526]
    DIRECTION INPUT ;
    USE SIGNAL ;
    PORT
      LAYER M4 ;
        RECT  21.516 2.064 21.6 2.088 ;
    END
  END i[526]
  PIN i[527]
    DIRECTION INPUT ;
    USE SIGNAL ;
    PORT
      LAYER M4 ;
        RECT  21.516 2.16 21.6 2.184 ;
    END
  END i[527]
  PIN i[528]
    DIRECTION INPUT ;
    USE SIGNAL ;
    PORT
      LAYER M4 ;
        RECT  21.516 2.256 21.6 2.28 ;
    END
  END i[528]
  PIN i[529]
    DIRECTION INPUT ;
    USE SIGNAL ;
    PORT
      LAYER M4 ;
        RECT  21.516 2.352 21.6 2.376 ;
    END
  END i[529]
  PIN i[52]
    DIRECTION INPUT ;
    USE SIGNAL ;
    PORT
      LAYER M4 ;
        RECT  21.516 27.984 21.6 28.008 ;
    END
  END i[52]
  PIN i[530]
    DIRECTION INPUT ;
    USE SIGNAL ;
    PORT
      LAYER M4 ;
        RECT  21.516 2.448 21.6 2.472 ;
    END
  END i[530]
  PIN i[531]
    DIRECTION INPUT ;
    USE SIGNAL ;
    PORT
      LAYER M4 ;
        RECT  21.516 2.544 21.6 2.568 ;
    END
  END i[531]
  PIN i[532]
    DIRECTION INPUT ;
    USE SIGNAL ;
    PORT
      LAYER M4 ;
        RECT  21.516 2.64 21.6 2.664 ;
    END
  END i[532]
  PIN i[533]
    DIRECTION INPUT ;
    USE SIGNAL ;
    PORT
      LAYER M4 ;
        RECT  21.516 2.736 21.6 2.76 ;
    END
  END i[533]
  PIN i[534]
    DIRECTION INPUT ;
    USE SIGNAL ;
    PORT
      LAYER M4 ;
        RECT  21.516 2.832 21.6 2.856 ;
    END
  END i[534]
  PIN i[535]
    DIRECTION INPUT ;
    USE SIGNAL ;
    PORT
      LAYER M4 ;
        RECT  21.516 2.928 21.6 2.952 ;
    END
  END i[535]
  PIN i[536]
    DIRECTION INPUT ;
    USE SIGNAL ;
    PORT
      LAYER M4 ;
        RECT  21.516 3.024 21.6 3.048 ;
    END
  END i[536]
  PIN i[537]
    DIRECTION INPUT ;
    USE SIGNAL ;
    PORT
      LAYER M4 ;
        RECT  21.516 3.12 21.6 3.144 ;
    END
  END i[537]
  PIN i[538]
    DIRECTION INPUT ;
    USE SIGNAL ;
    PORT
      LAYER M4 ;
        RECT  21.516 3.216 21.6 3.24 ;
    END
  END i[538]
  PIN i[539]
    DIRECTION INPUT ;
    USE SIGNAL ;
    PORT
      LAYER M4 ;
        RECT  21.516 3.312 21.6 3.336 ;
    END
  END i[539]
  PIN i[53]
    DIRECTION INPUT ;
    USE SIGNAL ;
    PORT
      LAYER M4 ;
        RECT  21.516 28.08 21.6 28.104 ;
    END
  END i[53]
  PIN i[540]
    DIRECTION INPUT ;
    USE SIGNAL ;
    PORT
      LAYER M4 ;
        RECT  21.516 3.408 21.6 3.432 ;
    END
  END i[540]
  PIN i[541]
    DIRECTION INPUT ;
    USE SIGNAL ;
    PORT
      LAYER M4 ;
        RECT  21.516 3.504 21.6 3.528 ;
    END
  END i[541]
  PIN i[542]
    DIRECTION INPUT ;
    USE SIGNAL ;
    PORT
      LAYER M4 ;
        RECT  21.516 3.6 21.6 3.624 ;
    END
  END i[542]
  PIN i[543]
    DIRECTION INPUT ;
    USE SIGNAL ;
    PORT
      LAYER M4 ;
        RECT  21.516 3.696 21.6 3.72 ;
    END
  END i[543]
  PIN i[544]
    DIRECTION INPUT ;
    USE SIGNAL ;
    PORT
      LAYER M4 ;
        RECT  21.516 13.008 21.6 13.032 ;
    END
  END i[544]
  PIN i[545]
    DIRECTION INPUT ;
    USE SIGNAL ;
    PORT
      LAYER M4 ;
        RECT  21.516 13.104 21.6 13.128 ;
    END
  END i[545]
  PIN i[546]
    DIRECTION INPUT ;
    USE SIGNAL ;
    PORT
      LAYER M4 ;
        RECT  21.516 13.2 21.6 13.224 ;
    END
  END i[546]
  PIN i[547]
    DIRECTION INPUT ;
    USE SIGNAL ;
    PORT
      LAYER M4 ;
        RECT  21.516 13.296 21.6 13.32 ;
    END
  END i[547]
  PIN i[548]
    DIRECTION INPUT ;
    USE SIGNAL ;
    PORT
      LAYER M4 ;
        RECT  21.516 13.392 21.6 13.416 ;
    END
  END i[548]
  PIN i[549]
    DIRECTION INPUT ;
    USE SIGNAL ;
    PORT
      LAYER M4 ;
        RECT  21.516 13.488 21.6 13.512 ;
    END
  END i[549]
  PIN i[54]
    DIRECTION INPUT ;
    USE SIGNAL ;
    PORT
      LAYER M4 ;
        RECT  21.516 28.176 21.6 28.2 ;
    END
  END i[54]
  PIN i[550]
    DIRECTION INPUT ;
    USE SIGNAL ;
    PORT
      LAYER M4 ;
        RECT  21.516 13.584 21.6 13.608 ;
    END
  END i[550]
  PIN i[551]
    DIRECTION INPUT ;
    USE SIGNAL ;
    PORT
      LAYER M4 ;
        RECT  21.516 13.68 21.6 13.704 ;
    END
  END i[551]
  PIN i[552]
    DIRECTION INPUT ;
    USE SIGNAL ;
    PORT
      LAYER M4 ;
        RECT  21.516 13.776 21.6 13.8 ;
    END
  END i[552]
  PIN i[553]
    DIRECTION INPUT ;
    USE SIGNAL ;
    PORT
      LAYER M4 ;
        RECT  21.516 13.872 21.6 13.896 ;
    END
  END i[553]
  PIN i[554]
    DIRECTION INPUT ;
    USE SIGNAL ;
    PORT
      LAYER M4 ;
        RECT  21.516 13.968 21.6 13.992 ;
    END
  END i[554]
  PIN i[555]
    DIRECTION INPUT ;
    USE SIGNAL ;
    PORT
      LAYER M4 ;
        RECT  21.516 14.064 21.6 14.088 ;
    END
  END i[555]
  PIN i[556]
    DIRECTION INPUT ;
    USE SIGNAL ;
    PORT
      LAYER M4 ;
        RECT  21.516 14.16 21.6 14.184 ;
    END
  END i[556]
  PIN i[557]
    DIRECTION INPUT ;
    USE SIGNAL ;
    PORT
      LAYER M4 ;
        RECT  21.516 14.256 21.6 14.28 ;
    END
  END i[557]
  PIN i[558]
    DIRECTION INPUT ;
    USE SIGNAL ;
    PORT
      LAYER M4 ;
        RECT  21.516 14.352 21.6 14.376 ;
    END
  END i[558]
  PIN i[559]
    DIRECTION INPUT ;
    USE SIGNAL ;
    PORT
      LAYER M4 ;
        RECT  21.516 14.448 21.6 14.472 ;
    END
  END i[559]
  PIN i[55]
    DIRECTION INPUT ;
    USE SIGNAL ;
    PORT
      LAYER M4 ;
        RECT  21.516 28.272 21.6 28.296 ;
    END
  END i[55]
  PIN i[560]
    DIRECTION INPUT ;
    USE SIGNAL ;
    PORT
      LAYER M4 ;
        RECT  21.516 14.544 21.6 14.568 ;
    END
  END i[560]
  PIN i[561]
    DIRECTION INPUT ;
    USE SIGNAL ;
    PORT
      LAYER M4 ;
        RECT  21.516 14.64 21.6 14.664 ;
    END
  END i[561]
  PIN i[562]
    DIRECTION INPUT ;
    USE SIGNAL ;
    PORT
      LAYER M4 ;
        RECT  21.516 14.736 21.6 14.76 ;
    END
  END i[562]
  PIN i[563]
    DIRECTION INPUT ;
    USE SIGNAL ;
    PORT
      LAYER M4 ;
        RECT  21.516 14.832 21.6 14.856 ;
    END
  END i[563]
  PIN i[564]
    DIRECTION INPUT ;
    USE SIGNAL ;
    PORT
      LAYER M4 ;
        RECT  21.516 14.928 21.6 14.952 ;
    END
  END i[564]
  PIN i[565]
    DIRECTION INPUT ;
    USE SIGNAL ;
    PORT
      LAYER M4 ;
        RECT  21.516 15.024 21.6 15.048 ;
    END
  END i[565]
  PIN i[566]
    DIRECTION INPUT ;
    USE SIGNAL ;
    PORT
      LAYER M4 ;
        RECT  21.516 15.12 21.6 15.144 ;
    END
  END i[566]
  PIN i[567]
    DIRECTION INPUT ;
    USE SIGNAL ;
    PORT
      LAYER M4 ;
        RECT  21.516 15.216 21.6 15.24 ;
    END
  END i[567]
  PIN i[568]
    DIRECTION INPUT ;
    USE SIGNAL ;
    PORT
      LAYER M4 ;
        RECT  21.516 15.312 21.6 15.336 ;
    END
  END i[568]
  PIN i[569]
    DIRECTION INPUT ;
    USE SIGNAL ;
    PORT
      LAYER M4 ;
        RECT  21.516 15.408 21.6 15.432 ;
    END
  END i[569]
  PIN i[56]
    DIRECTION INPUT ;
    USE SIGNAL ;
    PORT
      LAYER M4 ;
        RECT  21.516 28.368 21.6 28.392 ;
    END
  END i[56]
  PIN i[570]
    DIRECTION INPUT ;
    USE SIGNAL ;
    PORT
      LAYER M4 ;
        RECT  21.516 15.504 21.6 15.528 ;
    END
  END i[570]
  PIN i[571]
    DIRECTION INPUT ;
    USE SIGNAL ;
    PORT
      LAYER M4 ;
        RECT  21.516 15.6 21.6 15.624 ;
    END
  END i[571]
  PIN i[572]
    DIRECTION INPUT ;
    USE SIGNAL ;
    PORT
      LAYER M4 ;
        RECT  21.516 15.696 21.6 15.72 ;
    END
  END i[572]
  PIN i[573]
    DIRECTION INPUT ;
    USE SIGNAL ;
    PORT
      LAYER M4 ;
        RECT  21.516 15.792 21.6 15.816 ;
    END
  END i[573]
  PIN i[574]
    DIRECTION INPUT ;
    USE SIGNAL ;
    PORT
      LAYER M4 ;
        RECT  21.516 15.888 21.6 15.912 ;
    END
  END i[574]
  PIN i[575]
    DIRECTION INPUT ;
    USE SIGNAL ;
    PORT
      LAYER M4 ;
        RECT  21.516 15.984 21.6 16.008 ;
    END
  END i[575]
  PIN i[576]
    DIRECTION INPUT ;
    USE SIGNAL ;
    PORT
      LAYER M4 ;
        RECT  21.516 9.936 21.6 9.96 ;
    END
  END i[576]
  PIN i[577]
    DIRECTION INPUT ;
    USE SIGNAL ;
    PORT
      LAYER M4 ;
        RECT  21.516 10.032 21.6 10.056 ;
    END
  END i[577]
  PIN i[578]
    DIRECTION INPUT ;
    USE SIGNAL ;
    PORT
      LAYER M4 ;
        RECT  21.516 10.128 21.6 10.152 ;
    END
  END i[578]
  PIN i[579]
    DIRECTION INPUT ;
    USE SIGNAL ;
    PORT
      LAYER M4 ;
        RECT  21.516 10.224 21.6 10.248 ;
    END
  END i[579]
  PIN i[57]
    DIRECTION INPUT ;
    USE SIGNAL ;
    PORT
      LAYER M4 ;
        RECT  21.516 28.464 21.6 28.488 ;
    END
  END i[57]
  PIN i[580]
    DIRECTION INPUT ;
    USE SIGNAL ;
    PORT
      LAYER M4 ;
        RECT  21.516 10.32 21.6 10.344 ;
    END
  END i[580]
  PIN i[581]
    DIRECTION INPUT ;
    USE SIGNAL ;
    PORT
      LAYER M4 ;
        RECT  21.516 10.416 21.6 10.44 ;
    END
  END i[581]
  PIN i[582]
    DIRECTION INPUT ;
    USE SIGNAL ;
    PORT
      LAYER M4 ;
        RECT  21.516 10.512 21.6 10.536 ;
    END
  END i[582]
  PIN i[583]
    DIRECTION INPUT ;
    USE SIGNAL ;
    PORT
      LAYER M4 ;
        RECT  21.516 10.608 21.6 10.632 ;
    END
  END i[583]
  PIN i[584]
    DIRECTION INPUT ;
    USE SIGNAL ;
    PORT
      LAYER M4 ;
        RECT  21.516 10.704 21.6 10.728 ;
    END
  END i[584]
  PIN i[585]
    DIRECTION INPUT ;
    USE SIGNAL ;
    PORT
      LAYER M4 ;
        RECT  21.516 10.8 21.6 10.824 ;
    END
  END i[585]
  PIN i[586]
    DIRECTION INPUT ;
    USE SIGNAL ;
    PORT
      LAYER M4 ;
        RECT  21.516 10.896 21.6 10.92 ;
    END
  END i[586]
  PIN i[587]
    DIRECTION INPUT ;
    USE SIGNAL ;
    PORT
      LAYER M4 ;
        RECT  21.516 10.992 21.6 11.016 ;
    END
  END i[587]
  PIN i[588]
    DIRECTION INPUT ;
    USE SIGNAL ;
    PORT
      LAYER M4 ;
        RECT  21.516 11.088 21.6 11.112 ;
    END
  END i[588]
  PIN i[589]
    DIRECTION INPUT ;
    USE SIGNAL ;
    PORT
      LAYER M4 ;
        RECT  21.516 11.184 21.6 11.208 ;
    END
  END i[589]
  PIN i[58]
    DIRECTION INPUT ;
    USE SIGNAL ;
    PORT
      LAYER M4 ;
        RECT  21.516 28.56 21.6 28.584 ;
    END
  END i[58]
  PIN i[590]
    DIRECTION INPUT ;
    USE SIGNAL ;
    PORT
      LAYER M4 ;
        RECT  21.516 11.28 21.6 11.304 ;
    END
  END i[590]
  PIN i[591]
    DIRECTION INPUT ;
    USE SIGNAL ;
    PORT
      LAYER M4 ;
        RECT  21.516 11.376 21.6 11.4 ;
    END
  END i[591]
  PIN i[592]
    DIRECTION INPUT ;
    USE SIGNAL ;
    PORT
      LAYER M4 ;
        RECT  21.516 11.472 21.6 11.496 ;
    END
  END i[592]
  PIN i[593]
    DIRECTION INPUT ;
    USE SIGNAL ;
    PORT
      LAYER M4 ;
        RECT  21.516 11.568 21.6 11.592 ;
    END
  END i[593]
  PIN i[594]
    DIRECTION INPUT ;
    USE SIGNAL ;
    PORT
      LAYER M4 ;
        RECT  21.516 11.664 21.6 11.688 ;
    END
  END i[594]
  PIN i[595]
    DIRECTION INPUT ;
    USE SIGNAL ;
    PORT
      LAYER M4 ;
        RECT  21.516 11.76 21.6 11.784 ;
    END
  END i[595]
  PIN i[596]
    DIRECTION INPUT ;
    USE SIGNAL ;
    PORT
      LAYER M4 ;
        RECT  21.516 11.856 21.6 11.88 ;
    END
  END i[596]
  PIN i[597]
    DIRECTION INPUT ;
    USE SIGNAL ;
    PORT
      LAYER M4 ;
        RECT  21.516 11.952 21.6 11.976 ;
    END
  END i[597]
  PIN i[598]
    DIRECTION INPUT ;
    USE SIGNAL ;
    PORT
      LAYER M4 ;
        RECT  21.516 12.048 21.6 12.072 ;
    END
  END i[598]
  PIN i[599]
    DIRECTION INPUT ;
    USE SIGNAL ;
    PORT
      LAYER M4 ;
        RECT  21.516 12.144 21.6 12.168 ;
    END
  END i[599]
  PIN i[59]
    DIRECTION INPUT ;
    USE SIGNAL ;
    PORT
      LAYER M4 ;
        RECT  21.516 28.656 21.6 28.68 ;
    END
  END i[59]
  PIN i[5]
    DIRECTION INPUT ;
    USE SIGNAL ;
    PORT
      LAYER M4 ;
        RECT  21.516 20.4 21.6 20.424 ;
    END
  END i[5]
  PIN i[600]
    DIRECTION INPUT ;
    USE SIGNAL ;
    PORT
      LAYER M4 ;
        RECT  21.516 12.24 21.6 12.264 ;
    END
  END i[600]
  PIN i[601]
    DIRECTION INPUT ;
    USE SIGNAL ;
    PORT
      LAYER M4 ;
        RECT  21.516 12.336 21.6 12.36 ;
    END
  END i[601]
  PIN i[602]
    DIRECTION INPUT ;
    USE SIGNAL ;
    PORT
      LAYER M4 ;
        RECT  21.516 12.432 21.6 12.456 ;
    END
  END i[602]
  PIN i[603]
    DIRECTION INPUT ;
    USE SIGNAL ;
    PORT
      LAYER M4 ;
        RECT  21.516 12.528 21.6 12.552 ;
    END
  END i[603]
  PIN i[604]
    DIRECTION INPUT ;
    USE SIGNAL ;
    PORT
      LAYER M4 ;
        RECT  21.516 12.624 21.6 12.648 ;
    END
  END i[604]
  PIN i[605]
    DIRECTION INPUT ;
    USE SIGNAL ;
    PORT
      LAYER M4 ;
        RECT  21.516 12.72 21.6 12.744 ;
    END
  END i[605]
  PIN i[606]
    DIRECTION INPUT ;
    USE SIGNAL ;
    PORT
      LAYER M4 ;
        RECT  21.516 12.816 21.6 12.84 ;
    END
  END i[606]
  PIN i[607]
    DIRECTION INPUT ;
    USE SIGNAL ;
    PORT
      LAYER M4 ;
        RECT  21.516 12.912 21.6 12.936 ;
    END
  END i[607]
  PIN i[608]
    DIRECTION INPUT ;
    USE SIGNAL ;
    PORT
      LAYER M4 ;
        RECT  21.516 61.392 21.6 61.416 ;
    END
  END i[608]
  PIN i[609]
    DIRECTION INPUT ;
    USE SIGNAL ;
    PORT
      LAYER M4 ;
        RECT  21.516 61.488 21.6 61.512 ;
    END
  END i[609]
  PIN i[60]
    DIRECTION INPUT ;
    USE SIGNAL ;
    PORT
      LAYER M4 ;
        RECT  21.516 28.752 21.6 28.776 ;
    END
  END i[60]
  PIN i[610]
    DIRECTION INPUT ;
    USE SIGNAL ;
    PORT
      LAYER M4 ;
        RECT  21.516 61.584 21.6 61.608 ;
    END
  END i[610]
  PIN i[611]
    DIRECTION INPUT ;
    USE SIGNAL ;
    PORT
      LAYER M4 ;
        RECT  21.516 61.68 21.6 61.704 ;
    END
  END i[611]
  PIN i[612]
    DIRECTION INPUT ;
    USE SIGNAL ;
    PORT
      LAYER M4 ;
        RECT  21.516 61.776 21.6 61.8 ;
    END
  END i[612]
  PIN i[613]
    DIRECTION INPUT ;
    USE SIGNAL ;
    PORT
      LAYER M4 ;
        RECT  21.516 61.872 21.6 61.896 ;
    END
  END i[613]
  PIN i[614]
    DIRECTION INPUT ;
    USE SIGNAL ;
    PORT
      LAYER M4 ;
        RECT  21.516 61.968 21.6 61.992 ;
    END
  END i[614]
  PIN i[615]
    DIRECTION INPUT ;
    USE SIGNAL ;
    PORT
      LAYER M4 ;
        RECT  21.516 62.064 21.6 62.088 ;
    END
  END i[615]
  PIN i[616]
    DIRECTION INPUT ;
    USE SIGNAL ;
    PORT
      LAYER M4 ;
        RECT  21.516 62.16 21.6 62.184 ;
    END
  END i[616]
  PIN i[617]
    DIRECTION INPUT ;
    USE SIGNAL ;
    PORT
      LAYER M4 ;
        RECT  21.516 62.256 21.6 62.28 ;
    END
  END i[617]
  PIN i[618]
    DIRECTION INPUT ;
    USE SIGNAL ;
    PORT
      LAYER M4 ;
        RECT  21.516 62.352 21.6 62.376 ;
    END
  END i[618]
  PIN i[619]
    DIRECTION INPUT ;
    USE SIGNAL ;
    PORT
      LAYER M4 ;
        RECT  21.516 62.448 21.6 62.472 ;
    END
  END i[619]
  PIN i[61]
    DIRECTION INPUT ;
    USE SIGNAL ;
    PORT
      LAYER M4 ;
        RECT  21.516 28.848 21.6 28.872 ;
    END
  END i[61]
  PIN i[620]
    DIRECTION INPUT ;
    USE SIGNAL ;
    PORT
      LAYER M4 ;
        RECT  21.516 62.544 21.6 62.568 ;
    END
  END i[620]
  PIN i[621]
    DIRECTION INPUT ;
    USE SIGNAL ;
    PORT
      LAYER M4 ;
        RECT  21.516 62.64 21.6 62.664 ;
    END
  END i[621]
  PIN i[622]
    DIRECTION INPUT ;
    USE SIGNAL ;
    PORT
      LAYER M4 ;
        RECT  21.516 62.736 21.6 62.76 ;
    END
  END i[622]
  PIN i[623]
    DIRECTION INPUT ;
    USE SIGNAL ;
    PORT
      LAYER M4 ;
        RECT  21.516 62.832 21.6 62.856 ;
    END
  END i[623]
  PIN i[62]
    DIRECTION INPUT ;
    USE SIGNAL ;
    PORT
      LAYER M4 ;
        RECT  21.516 28.944 21.6 28.968 ;
    END
  END i[62]
  PIN i[63]
    DIRECTION INPUT ;
    USE SIGNAL ;
    PORT
      LAYER M4 ;
        RECT  21.516 29.04 21.6 29.064 ;
    END
  END i[63]
  PIN i[64]
    DIRECTION INPUT ;
    USE SIGNAL ;
    PORT
      LAYER M4 ;
        RECT  21.516 29.136 21.6 29.16 ;
    END
  END i[64]
  PIN i[65]
    DIRECTION INPUT ;
    USE SIGNAL ;
    PORT
      LAYER M4 ;
        RECT  21.516 29.232 21.6 29.256 ;
    END
  END i[65]
  PIN i[66]
    DIRECTION INPUT ;
    USE SIGNAL ;
    PORT
      LAYER M4 ;
        RECT  21.516 29.328 21.6 29.352 ;
    END
  END i[66]
  PIN i[67]
    DIRECTION INPUT ;
    USE SIGNAL ;
    PORT
      LAYER M4 ;
        RECT  21.516 29.424 21.6 29.448 ;
    END
  END i[67]
  PIN i[68]
    DIRECTION INPUT ;
    USE SIGNAL ;
    PORT
      LAYER M4 ;
        RECT  21.516 29.52 21.6 29.544 ;
    END
  END i[68]
  PIN i[69]
    DIRECTION INPUT ;
    USE SIGNAL ;
    PORT
      LAYER M4 ;
        RECT  21.516 29.616 21.6 29.64 ;
    END
  END i[69]
  PIN i[6]
    DIRECTION INPUT ;
    USE SIGNAL ;
    PORT
      LAYER M4 ;
        RECT  21.516 20.496 21.6 20.52 ;
    END
  END i[6]
  PIN i[70]
    DIRECTION INPUT ;
    USE SIGNAL ;
    PORT
      LAYER M4 ;
        RECT  21.516 29.712 21.6 29.736 ;
    END
  END i[70]
  PIN i[71]
    DIRECTION INPUT ;
    USE SIGNAL ;
    PORT
      LAYER M4 ;
        RECT  21.516 29.808 21.6 29.832 ;
    END
  END i[71]
  PIN i[72]
    DIRECTION INPUT ;
    USE SIGNAL ;
    PORT
      LAYER M4 ;
        RECT  21.516 29.904 21.6 29.928 ;
    END
  END i[72]
  PIN i[73]
    DIRECTION INPUT ;
    USE SIGNAL ;
    PORT
      LAYER M4 ;
        RECT  21.516 30 21.6 30.024 ;
    END
  END i[73]
  PIN i[74]
    DIRECTION INPUT ;
    USE SIGNAL ;
    PORT
      LAYER M4 ;
        RECT  21.516 30.096 21.6 30.12 ;
    END
  END i[74]
  PIN i[75]
    DIRECTION INPUT ;
    USE SIGNAL ;
    PORT
      LAYER M4 ;
        RECT  21.516 30.192 21.6 30.216 ;
    END
  END i[75]
  PIN i[76]
    DIRECTION INPUT ;
    USE SIGNAL ;
    PORT
      LAYER M4 ;
        RECT  21.516 30.288 21.6 30.312 ;
    END
  END i[76]
  PIN i[77]
    DIRECTION INPUT ;
    USE SIGNAL ;
    PORT
      LAYER M4 ;
        RECT  21.516 30.384 21.6 30.408 ;
    END
  END i[77]
  PIN i[78]
    DIRECTION INPUT ;
    USE SIGNAL ;
    PORT
      LAYER M4 ;
        RECT  21.516 30.48 21.6 30.504 ;
    END
  END i[78]
  PIN i[79]
    DIRECTION INPUT ;
    USE SIGNAL ;
    PORT
      LAYER M4 ;
        RECT  21.516 30.576 21.6 30.6 ;
    END
  END i[79]
  PIN i[7]
    DIRECTION INPUT ;
    USE SIGNAL ;
    PORT
      LAYER M4 ;
        RECT  21.516 20.592 21.6 20.616 ;
    END
  END i[7]
  PIN i[80]
    DIRECTION INPUT ;
    USE SIGNAL ;
    PORT
      LAYER M4 ;
        RECT  21.516 30.672 21.6 30.696 ;
    END
  END i[80]
  PIN i[81]
    DIRECTION INPUT ;
    USE SIGNAL ;
    PORT
      LAYER M4 ;
        RECT  21.516 30.768 21.6 30.792 ;
    END
  END i[81]
  PIN i[82]
    DIRECTION INPUT ;
    USE SIGNAL ;
    PORT
      LAYER M4 ;
        RECT  21.516 30.864 21.6 30.888 ;
    END
  END i[82]
  PIN i[83]
    DIRECTION INPUT ;
    USE SIGNAL ;
    PORT
      LAYER M4 ;
        RECT  21.516 30.96 21.6 30.984 ;
    END
  END i[83]
  PIN i[84]
    DIRECTION INPUT ;
    USE SIGNAL ;
    PORT
      LAYER M4 ;
        RECT  21.516 31.056 21.6 31.08 ;
    END
  END i[84]
  PIN i[85]
    DIRECTION INPUT ;
    USE SIGNAL ;
    PORT
      LAYER M4 ;
        RECT  21.516 31.152 21.6 31.176 ;
    END
  END i[85]
  PIN i[86]
    DIRECTION INPUT ;
    USE SIGNAL ;
    PORT
      LAYER M4 ;
        RECT  21.516 31.248 21.6 31.272 ;
    END
  END i[86]
  PIN i[87]
    DIRECTION INPUT ;
    USE SIGNAL ;
    PORT
      LAYER M4 ;
        RECT  21.516 31.344 21.6 31.368 ;
    END
  END i[87]
  PIN i[88]
    DIRECTION INPUT ;
    USE SIGNAL ;
    PORT
      LAYER M4 ;
        RECT  21.516 31.44 21.6 31.464 ;
    END
  END i[88]
  PIN i[89]
    DIRECTION INPUT ;
    USE SIGNAL ;
    PORT
      LAYER M4 ;
        RECT  21.516 31.536 21.6 31.56 ;
    END
  END i[89]
  PIN i[8]
    DIRECTION INPUT ;
    USE SIGNAL ;
    PORT
      LAYER M4 ;
        RECT  21.516 20.688 21.6 20.712 ;
    END
  END i[8]
  PIN i[90]
    DIRECTION INPUT ;
    USE SIGNAL ;
    PORT
      LAYER M4 ;
        RECT  21.516 31.632 21.6 31.656 ;
    END
  END i[90]
  PIN i[91]
    DIRECTION INPUT ;
    USE SIGNAL ;
    PORT
      LAYER M4 ;
        RECT  21.516 31.728 21.6 31.752 ;
    END
  END i[91]
  PIN i[92]
    DIRECTION INPUT ;
    USE SIGNAL ;
    PORT
      LAYER M4 ;
        RECT  21.516 31.824 21.6 31.848 ;
    END
  END i[92]
  PIN i[93]
    DIRECTION INPUT ;
    USE SIGNAL ;
    PORT
      LAYER M4 ;
        RECT  21.516 31.92 21.6 31.944 ;
    END
  END i[93]
  PIN i[94]
    DIRECTION INPUT ;
    USE SIGNAL ;
    PORT
      LAYER M4 ;
        RECT  21.516 32.016 21.6 32.04 ;
    END
  END i[94]
  PIN i[95]
    DIRECTION INPUT ;
    USE SIGNAL ;
    PORT
      LAYER M4 ;
        RECT  21.516 32.112 21.6 32.136 ;
    END
  END i[95]
  PIN i[96]
    DIRECTION INPUT ;
    USE SIGNAL ;
    PORT
      LAYER M4 ;
        RECT  21.516 35.28 21.6 35.304 ;
    END
  END i[96]
  PIN i[97]
    DIRECTION INPUT ;
    USE SIGNAL ;
    PORT
      LAYER M4 ;
        RECT  21.516 35.376 21.6 35.4 ;
    END
  END i[97]
  PIN i[98]
    DIRECTION INPUT ;
    USE SIGNAL ;
    PORT
      LAYER M4 ;
        RECT  21.516 35.472 21.6 35.496 ;
    END
  END i[98]
  PIN i[99]
    DIRECTION INPUT ;
    USE SIGNAL ;
    PORT
      LAYER M4 ;
        RECT  21.516 35.568 21.6 35.592 ;
    END
  END i[99]
  PIN i[9]
    DIRECTION INPUT ;
    USE SIGNAL ;
    PORT
      LAYER M4 ;
        RECT  21.516 20.784 21.6 20.808 ;
    END
  END i[9]
  PIN o[0]
    DIRECTION OUTPUT ;
    USE SIGNAL ;
    PORT
      LAYER M4 ;
        RECT  0 7.248 0.084 7.272 ;
    END
  END o[0]
  PIN o[100]
    DIRECTION OUTPUT ;
    USE SIGNAL ;
    PORT
      LAYER M4 ;
        RECT  0 36.048 0.084 36.072 ;
    END
  END o[100]
  PIN o[101]
    DIRECTION OUTPUT ;
    USE SIGNAL ;
    PORT
      LAYER M4 ;
        RECT  0 36.144 0.084 36.168 ;
    END
  END o[101]
  PIN o[102]
    DIRECTION OUTPUT ;
    USE SIGNAL ;
    PORT
      LAYER M4 ;
        RECT  0 36.24 0.084 36.264 ;
    END
  END o[102]
  PIN o[103]
    DIRECTION OUTPUT ;
    USE SIGNAL ;
    PORT
      LAYER M4 ;
        RECT  0 36.336 0.084 36.36 ;
    END
  END o[103]
  PIN o[104]
    DIRECTION OUTPUT ;
    USE SIGNAL ;
    PORT
      LAYER M4 ;
        RECT  0 36.432 0.084 36.456 ;
    END
  END o[104]
  PIN o[105]
    DIRECTION OUTPUT ;
    USE SIGNAL ;
    PORT
      LAYER M4 ;
        RECT  0 36.528 0.084 36.552 ;
    END
  END o[105]
  PIN o[106]
    DIRECTION OUTPUT ;
    USE SIGNAL ;
    PORT
      LAYER M4 ;
        RECT  0 36.624 0.084 36.648 ;
    END
  END o[106]
  PIN o[107]
    DIRECTION OUTPUT ;
    USE SIGNAL ;
    PORT
      LAYER M4 ;
        RECT  0 36.72 0.084 36.744 ;
    END
  END o[107]
  PIN o[108]
    DIRECTION OUTPUT ;
    USE SIGNAL ;
    PORT
      LAYER M4 ;
        RECT  0 36.816 0.084 36.84 ;
    END
  END o[108]
  PIN o[109]
    DIRECTION OUTPUT ;
    USE SIGNAL ;
    PORT
      LAYER M4 ;
        RECT  0 36.912 0.084 36.936 ;
    END
  END o[109]
  PIN o[10]
    DIRECTION OUTPUT ;
    USE SIGNAL ;
    PORT
      LAYER M4 ;
        RECT  0 8.208 0.084 8.232 ;
    END
  END o[10]
  PIN o[110]
    DIRECTION OUTPUT ;
    USE SIGNAL ;
    PORT
      LAYER M4 ;
        RECT  0 37.008 0.084 37.032 ;
    END
  END o[110]
  PIN o[111]
    DIRECTION OUTPUT ;
    USE SIGNAL ;
    PORT
      LAYER M4 ;
        RECT  0 37.104 0.084 37.128 ;
    END
  END o[111]
  PIN o[112]
    DIRECTION OUTPUT ;
    USE SIGNAL ;
    PORT
      LAYER M4 ;
        RECT  0 37.2 0.084 37.224 ;
    END
  END o[112]
  PIN o[113]
    DIRECTION OUTPUT ;
    USE SIGNAL ;
    PORT
      LAYER M4 ;
        RECT  0 37.296 0.084 37.32 ;
    END
  END o[113]
  PIN o[114]
    DIRECTION OUTPUT ;
    USE SIGNAL ;
    PORT
      LAYER M4 ;
        RECT  0 37.392 0.084 37.416 ;
    END
  END o[114]
  PIN o[115]
    DIRECTION OUTPUT ;
    USE SIGNAL ;
    PORT
      LAYER M4 ;
        RECT  0 37.488 0.084 37.512 ;
    END
  END o[115]
  PIN o[116]
    DIRECTION OUTPUT ;
    USE SIGNAL ;
    PORT
      LAYER M4 ;
        RECT  0 37.584 0.084 37.608 ;
    END
  END o[116]
  PIN o[117]
    DIRECTION OUTPUT ;
    USE SIGNAL ;
    PORT
      LAYER M4 ;
        RECT  0 37.68 0.084 37.704 ;
    END
  END o[117]
  PIN o[118]
    DIRECTION OUTPUT ;
    USE SIGNAL ;
    PORT
      LAYER M4 ;
        RECT  0 37.776 0.084 37.8 ;
    END
  END o[118]
  PIN o[119]
    DIRECTION OUTPUT ;
    USE SIGNAL ;
    PORT
      LAYER M4 ;
        RECT  0 37.872 0.084 37.896 ;
    END
  END o[119]
  PIN o[11]
    DIRECTION OUTPUT ;
    USE SIGNAL ;
    PORT
      LAYER M4 ;
        RECT  0 8.304 0.084 8.328 ;
    END
  END o[11]
  PIN o[120]
    DIRECTION OUTPUT ;
    USE SIGNAL ;
    PORT
      LAYER M4 ;
        RECT  0 37.968 0.084 37.992 ;
    END
  END o[120]
  PIN o[121]
    DIRECTION OUTPUT ;
    USE SIGNAL ;
    PORT
      LAYER M4 ;
        RECT  0 38.064 0.084 38.088 ;
    END
  END o[121]
  PIN o[122]
    DIRECTION OUTPUT ;
    USE SIGNAL ;
    PORT
      LAYER M4 ;
        RECT  0 38.16 0.084 38.184 ;
    END
  END o[122]
  PIN o[123]
    DIRECTION OUTPUT ;
    USE SIGNAL ;
    PORT
      LAYER M4 ;
        RECT  0 38.256 0.084 38.28 ;
    END
  END o[123]
  PIN o[124]
    DIRECTION OUTPUT ;
    USE SIGNAL ;
    PORT
      LAYER M4 ;
        RECT  0 38.352 0.084 38.376 ;
    END
  END o[124]
  PIN o[125]
    DIRECTION OUTPUT ;
    USE SIGNAL ;
    PORT
      LAYER M4 ;
        RECT  0 38.448 0.084 38.472 ;
    END
  END o[125]
  PIN o[126]
    DIRECTION OUTPUT ;
    USE SIGNAL ;
    PORT
      LAYER M4 ;
        RECT  0 38.544 0.084 38.568 ;
    END
  END o[126]
  PIN o[127]
    DIRECTION OUTPUT ;
    USE SIGNAL ;
    PORT
      LAYER M4 ;
        RECT  0 38.64 0.084 38.664 ;
    END
  END o[127]
  PIN o[128]
    DIRECTION OUTPUT ;
    USE SIGNAL ;
    PORT
      LAYER M4 ;
        RECT  0 19.536 0.084 19.56 ;
    END
  END o[128]
  PIN o[129]
    DIRECTION OUTPUT ;
    USE SIGNAL ;
    PORT
      LAYER M4 ;
        RECT  0 19.632 0.084 19.656 ;
    END
  END o[129]
  PIN o[12]
    DIRECTION OUTPUT ;
    USE SIGNAL ;
    PORT
      LAYER M4 ;
        RECT  0 8.4 0.084 8.424 ;
    END
  END o[12]
  PIN o[130]
    DIRECTION OUTPUT ;
    USE SIGNAL ;
    PORT
      LAYER M4 ;
        RECT  0 19.728 0.084 19.752 ;
    END
  END o[130]
  PIN o[131]
    DIRECTION OUTPUT ;
    USE SIGNAL ;
    PORT
      LAYER M4 ;
        RECT  0 19.824 0.084 19.848 ;
    END
  END o[131]
  PIN o[132]
    DIRECTION OUTPUT ;
    USE SIGNAL ;
    PORT
      LAYER M4 ;
        RECT  0 19.92 0.084 19.944 ;
    END
  END o[132]
  PIN o[133]
    DIRECTION OUTPUT ;
    USE SIGNAL ;
    PORT
      LAYER M4 ;
        RECT  0 20.016 0.084 20.04 ;
    END
  END o[133]
  PIN o[134]
    DIRECTION OUTPUT ;
    USE SIGNAL ;
    PORT
      LAYER M4 ;
        RECT  0 20.112 0.084 20.136 ;
    END
  END o[134]
  PIN o[135]
    DIRECTION OUTPUT ;
    USE SIGNAL ;
    PORT
      LAYER M4 ;
        RECT  0 20.208 0.084 20.232 ;
    END
  END o[135]
  PIN o[136]
    DIRECTION OUTPUT ;
    USE SIGNAL ;
    PORT
      LAYER M4 ;
        RECT  0 20.304 0.084 20.328 ;
    END
  END o[136]
  PIN o[137]
    DIRECTION OUTPUT ;
    USE SIGNAL ;
    PORT
      LAYER M4 ;
        RECT  0 20.4 0.084 20.424 ;
    END
  END o[137]
  PIN o[138]
    DIRECTION OUTPUT ;
    USE SIGNAL ;
    PORT
      LAYER M4 ;
        RECT  0 20.496 0.084 20.52 ;
    END
  END o[138]
  PIN o[139]
    DIRECTION OUTPUT ;
    USE SIGNAL ;
    PORT
      LAYER M4 ;
        RECT  0 20.592 0.084 20.616 ;
    END
  END o[139]
  PIN o[13]
    DIRECTION OUTPUT ;
    USE SIGNAL ;
    PORT
      LAYER M4 ;
        RECT  0 8.496 0.084 8.52 ;
    END
  END o[13]
  PIN o[140]
    DIRECTION OUTPUT ;
    USE SIGNAL ;
    PORT
      LAYER M4 ;
        RECT  0 20.688 0.084 20.712 ;
    END
  END o[140]
  PIN o[141]
    DIRECTION OUTPUT ;
    USE SIGNAL ;
    PORT
      LAYER M4 ;
        RECT  0 20.784 0.084 20.808 ;
    END
  END o[141]
  PIN o[142]
    DIRECTION OUTPUT ;
    USE SIGNAL ;
    PORT
      LAYER M4 ;
        RECT  0 20.88 0.084 20.904 ;
    END
  END o[142]
  PIN o[143]
    DIRECTION OUTPUT ;
    USE SIGNAL ;
    PORT
      LAYER M4 ;
        RECT  0 20.976 0.084 21 ;
    END
  END o[143]
  PIN o[144]
    DIRECTION OUTPUT ;
    USE SIGNAL ;
    PORT
      LAYER M4 ;
        RECT  0 21.072 0.084 21.096 ;
    END
  END o[144]
  PIN o[145]
    DIRECTION OUTPUT ;
    USE SIGNAL ;
    PORT
      LAYER M4 ;
        RECT  0 21.168 0.084 21.192 ;
    END
  END o[145]
  PIN o[146]
    DIRECTION OUTPUT ;
    USE SIGNAL ;
    PORT
      LAYER M4 ;
        RECT  0 21.264 0.084 21.288 ;
    END
  END o[146]
  PIN o[147]
    DIRECTION OUTPUT ;
    USE SIGNAL ;
    PORT
      LAYER M4 ;
        RECT  0 21.36 0.084 21.384 ;
    END
  END o[147]
  PIN o[148]
    DIRECTION OUTPUT ;
    USE SIGNAL ;
    PORT
      LAYER M4 ;
        RECT  0 21.456 0.084 21.48 ;
    END
  END o[148]
  PIN o[149]
    DIRECTION OUTPUT ;
    USE SIGNAL ;
    PORT
      LAYER M4 ;
        RECT  0 21.552 0.084 21.576 ;
    END
  END o[149]
  PIN o[14]
    DIRECTION OUTPUT ;
    USE SIGNAL ;
    PORT
      LAYER M4 ;
        RECT  0 8.592 0.084 8.616 ;
    END
  END o[14]
  PIN o[150]
    DIRECTION OUTPUT ;
    USE SIGNAL ;
    PORT
      LAYER M4 ;
        RECT  0 21.648 0.084 21.672 ;
    END
  END o[150]
  PIN o[151]
    DIRECTION OUTPUT ;
    USE SIGNAL ;
    PORT
      LAYER M4 ;
        RECT  0 21.744 0.084 21.768 ;
    END
  END o[151]
  PIN o[152]
    DIRECTION OUTPUT ;
    USE SIGNAL ;
    PORT
      LAYER M4 ;
        RECT  0 21.84 0.084 21.864 ;
    END
  END o[152]
  PIN o[153]
    DIRECTION OUTPUT ;
    USE SIGNAL ;
    PORT
      LAYER M4 ;
        RECT  0 21.936 0.084 21.96 ;
    END
  END o[153]
  PIN o[154]
    DIRECTION OUTPUT ;
    USE SIGNAL ;
    PORT
      LAYER M4 ;
        RECT  0 22.032 0.084 22.056 ;
    END
  END o[154]
  PIN o[155]
    DIRECTION OUTPUT ;
    USE SIGNAL ;
    PORT
      LAYER M4 ;
        RECT  0 22.128 0.084 22.152 ;
    END
  END o[155]
  PIN o[156]
    DIRECTION OUTPUT ;
    USE SIGNAL ;
    PORT
      LAYER M4 ;
        RECT  0 22.224 0.084 22.248 ;
    END
  END o[156]
  PIN o[157]
    DIRECTION OUTPUT ;
    USE SIGNAL ;
    PORT
      LAYER M4 ;
        RECT  0 22.32 0.084 22.344 ;
    END
  END o[157]
  PIN o[158]
    DIRECTION OUTPUT ;
    USE SIGNAL ;
    PORT
      LAYER M4 ;
        RECT  0 22.416 0.084 22.44 ;
    END
  END o[158]
  PIN o[159]
    DIRECTION OUTPUT ;
    USE SIGNAL ;
    PORT
      LAYER M4 ;
        RECT  0 22.512 0.084 22.536 ;
    END
  END o[159]
  PIN o[15]
    DIRECTION OUTPUT ;
    USE SIGNAL ;
    PORT
      LAYER M4 ;
        RECT  0 8.688 0.084 8.712 ;
    END
  END o[15]
  PIN o[160]
    DIRECTION OUTPUT ;
    USE SIGNAL ;
    PORT
      LAYER M4 ;
        RECT  0 32.592 0.084 32.616 ;
    END
  END o[160]
  PIN o[161]
    DIRECTION OUTPUT ;
    USE SIGNAL ;
    PORT
      LAYER M4 ;
        RECT  0 32.688 0.084 32.712 ;
    END
  END o[161]
  PIN o[162]
    DIRECTION OUTPUT ;
    USE SIGNAL ;
    PORT
      LAYER M4 ;
        RECT  0 32.784 0.084 32.808 ;
    END
  END o[162]
  PIN o[163]
    DIRECTION OUTPUT ;
    USE SIGNAL ;
    PORT
      LAYER M4 ;
        RECT  0 32.88 0.084 32.904 ;
    END
  END o[163]
  PIN o[164]
    DIRECTION OUTPUT ;
    USE SIGNAL ;
    PORT
      LAYER M4 ;
        RECT  0 32.976 0.084 33 ;
    END
  END o[164]
  PIN o[165]
    DIRECTION OUTPUT ;
    USE SIGNAL ;
    PORT
      LAYER M4 ;
        RECT  0 33.072 0.084 33.096 ;
    END
  END o[165]
  PIN o[166]
    DIRECTION OUTPUT ;
    USE SIGNAL ;
    PORT
      LAYER M4 ;
        RECT  0 33.168 0.084 33.192 ;
    END
  END o[166]
  PIN o[167]
    DIRECTION OUTPUT ;
    USE SIGNAL ;
    PORT
      LAYER M4 ;
        RECT  0 33.264 0.084 33.288 ;
    END
  END o[167]
  PIN o[168]
    DIRECTION OUTPUT ;
    USE SIGNAL ;
    PORT
      LAYER M4 ;
        RECT  0 33.36 0.084 33.384 ;
    END
  END o[168]
  PIN o[169]
    DIRECTION OUTPUT ;
    USE SIGNAL ;
    PORT
      LAYER M4 ;
        RECT  0 33.456 0.084 33.48 ;
    END
  END o[169]
  PIN o[16]
    DIRECTION OUTPUT ;
    USE SIGNAL ;
    PORT
      LAYER M4 ;
        RECT  0 8.784 0.084 8.808 ;
    END
  END o[16]
  PIN o[170]
    DIRECTION OUTPUT ;
    USE SIGNAL ;
    PORT
      LAYER M4 ;
        RECT  0 33.552 0.084 33.576 ;
    END
  END o[170]
  PIN o[171]
    DIRECTION OUTPUT ;
    USE SIGNAL ;
    PORT
      LAYER M4 ;
        RECT  0 33.648 0.084 33.672 ;
    END
  END o[171]
  PIN o[172]
    DIRECTION OUTPUT ;
    USE SIGNAL ;
    PORT
      LAYER M4 ;
        RECT  0 33.744 0.084 33.768 ;
    END
  END o[172]
  PIN o[173]
    DIRECTION OUTPUT ;
    USE SIGNAL ;
    PORT
      LAYER M4 ;
        RECT  0 33.84 0.084 33.864 ;
    END
  END o[173]
  PIN o[174]
    DIRECTION OUTPUT ;
    USE SIGNAL ;
    PORT
      LAYER M4 ;
        RECT  0 33.936 0.084 33.96 ;
    END
  END o[174]
  PIN o[175]
    DIRECTION OUTPUT ;
    USE SIGNAL ;
    PORT
      LAYER M4 ;
        RECT  0 34.032 0.084 34.056 ;
    END
  END o[175]
  PIN o[176]
    DIRECTION OUTPUT ;
    USE SIGNAL ;
    PORT
      LAYER M4 ;
        RECT  0 34.128 0.084 34.152 ;
    END
  END o[176]
  PIN o[177]
    DIRECTION OUTPUT ;
    USE SIGNAL ;
    PORT
      LAYER M4 ;
        RECT  0 34.224 0.084 34.248 ;
    END
  END o[177]
  PIN o[178]
    DIRECTION OUTPUT ;
    USE SIGNAL ;
    PORT
      LAYER M4 ;
        RECT  0 34.32 0.084 34.344 ;
    END
  END o[178]
  PIN o[179]
    DIRECTION OUTPUT ;
    USE SIGNAL ;
    PORT
      LAYER M4 ;
        RECT  0 34.416 0.084 34.44 ;
    END
  END o[179]
  PIN o[17]
    DIRECTION OUTPUT ;
    USE SIGNAL ;
    PORT
      LAYER M4 ;
        RECT  0 8.88 0.084 8.904 ;
    END
  END o[17]
  PIN o[180]
    DIRECTION OUTPUT ;
    USE SIGNAL ;
    PORT
      LAYER M4 ;
        RECT  0 34.512 0.084 34.536 ;
    END
  END o[180]
  PIN o[181]
    DIRECTION OUTPUT ;
    USE SIGNAL ;
    PORT
      LAYER M4 ;
        RECT  0 34.608 0.084 34.632 ;
    END
  END o[181]
  PIN o[182]
    DIRECTION OUTPUT ;
    USE SIGNAL ;
    PORT
      LAYER M4 ;
        RECT  0 34.704 0.084 34.728 ;
    END
  END o[182]
  PIN o[183]
    DIRECTION OUTPUT ;
    USE SIGNAL ;
    PORT
      LAYER M4 ;
        RECT  0 34.8 0.084 34.824 ;
    END
  END o[183]
  PIN o[184]
    DIRECTION OUTPUT ;
    USE SIGNAL ;
    PORT
      LAYER M4 ;
        RECT  0 34.896 0.084 34.92 ;
    END
  END o[184]
  PIN o[185]
    DIRECTION OUTPUT ;
    USE SIGNAL ;
    PORT
      LAYER M4 ;
        RECT  0 34.992 0.084 35.016 ;
    END
  END o[185]
  PIN o[186]
    DIRECTION OUTPUT ;
    USE SIGNAL ;
    PORT
      LAYER M4 ;
        RECT  0 35.088 0.084 35.112 ;
    END
  END o[186]
  PIN o[187]
    DIRECTION OUTPUT ;
    USE SIGNAL ;
    PORT
      LAYER M4 ;
        RECT  0 35.184 0.084 35.208 ;
    END
  END o[187]
  PIN o[188]
    DIRECTION OUTPUT ;
    USE SIGNAL ;
    PORT
      LAYER M4 ;
        RECT  0 35.28 0.084 35.304 ;
    END
  END o[188]
  PIN o[189]
    DIRECTION OUTPUT ;
    USE SIGNAL ;
    PORT
      LAYER M4 ;
        RECT  0 35.376 0.084 35.4 ;
    END
  END o[189]
  PIN o[18]
    DIRECTION OUTPUT ;
    USE SIGNAL ;
    PORT
      LAYER M4 ;
        RECT  0 8.976 0.084 9 ;
    END
  END o[18]
  PIN o[190]
    DIRECTION OUTPUT ;
    USE SIGNAL ;
    PORT
      LAYER M4 ;
        RECT  0 35.472 0.084 35.496 ;
    END
  END o[190]
  PIN o[191]
    DIRECTION OUTPUT ;
    USE SIGNAL ;
    PORT
      LAYER M4 ;
        RECT  0 35.568 0.084 35.592 ;
    END
  END o[191]
  PIN o[192]
    DIRECTION OUTPUT ;
    USE SIGNAL ;
    PORT
      LAYER M4 ;
        RECT  0 38.736 0.084 38.76 ;
    END
  END o[192]
  PIN o[193]
    DIRECTION OUTPUT ;
    USE SIGNAL ;
    PORT
      LAYER M4 ;
        RECT  0 38.832 0.084 38.856 ;
    END
  END o[193]
  PIN o[194]
    DIRECTION OUTPUT ;
    USE SIGNAL ;
    PORT
      LAYER M4 ;
        RECT  0 38.928 0.084 38.952 ;
    END
  END o[194]
  PIN o[195]
    DIRECTION OUTPUT ;
    USE SIGNAL ;
    PORT
      LAYER M4 ;
        RECT  0 39.024 0.084 39.048 ;
    END
  END o[195]
  PIN o[196]
    DIRECTION OUTPUT ;
    USE SIGNAL ;
    PORT
      LAYER M4 ;
        RECT  0 39.12 0.084 39.144 ;
    END
  END o[196]
  PIN o[197]
    DIRECTION OUTPUT ;
    USE SIGNAL ;
    PORT
      LAYER M4 ;
        RECT  0 39.216 0.084 39.24 ;
    END
  END o[197]
  PIN o[198]
    DIRECTION OUTPUT ;
    USE SIGNAL ;
    PORT
      LAYER M4 ;
        RECT  0 39.312 0.084 39.336 ;
    END
  END o[198]
  PIN o[199]
    DIRECTION OUTPUT ;
    USE SIGNAL ;
    PORT
      LAYER M4 ;
        RECT  0 39.408 0.084 39.432 ;
    END
  END o[199]
  PIN o[19]
    DIRECTION OUTPUT ;
    USE SIGNAL ;
    PORT
      LAYER M4 ;
        RECT  0 9.072 0.084 9.096 ;
    END
  END o[19]
  PIN o[1]
    DIRECTION OUTPUT ;
    USE SIGNAL ;
    PORT
      LAYER M4 ;
        RECT  0 7.344 0.084 7.368 ;
    END
  END o[1]
  PIN o[200]
    DIRECTION OUTPUT ;
    USE SIGNAL ;
    PORT
      LAYER M4 ;
        RECT  0 39.504 0.084 39.528 ;
    END
  END o[200]
  PIN o[201]
    DIRECTION OUTPUT ;
    USE SIGNAL ;
    PORT
      LAYER M4 ;
        RECT  0 39.6 0.084 39.624 ;
    END
  END o[201]
  PIN o[202]
    DIRECTION OUTPUT ;
    USE SIGNAL ;
    PORT
      LAYER M4 ;
        RECT  0 39.696 0.084 39.72 ;
    END
  END o[202]
  PIN o[203]
    DIRECTION OUTPUT ;
    USE SIGNAL ;
    PORT
      LAYER M4 ;
        RECT  0 39.792 0.084 39.816 ;
    END
  END o[203]
  PIN o[204]
    DIRECTION OUTPUT ;
    USE SIGNAL ;
    PORT
      LAYER M4 ;
        RECT  0 39.888 0.084 39.912 ;
    END
  END o[204]
  PIN o[205]
    DIRECTION OUTPUT ;
    USE SIGNAL ;
    PORT
      LAYER M4 ;
        RECT  0 39.984 0.084 40.008 ;
    END
  END o[205]
  PIN o[206]
    DIRECTION OUTPUT ;
    USE SIGNAL ;
    PORT
      LAYER M4 ;
        RECT  0 40.08 0.084 40.104 ;
    END
  END o[206]
  PIN o[207]
    DIRECTION OUTPUT ;
    USE SIGNAL ;
    PORT
      LAYER M4 ;
        RECT  0 40.176 0.084 40.2 ;
    END
  END o[207]
  PIN o[208]
    DIRECTION OUTPUT ;
    USE SIGNAL ;
    PORT
      LAYER M4 ;
        RECT  0 40.272 0.084 40.296 ;
    END
  END o[208]
  PIN o[209]
    DIRECTION OUTPUT ;
    USE SIGNAL ;
    PORT
      LAYER M4 ;
        RECT  0 40.368 0.084 40.392 ;
    END
  END o[209]
  PIN o[20]
    DIRECTION OUTPUT ;
    USE SIGNAL ;
    PORT
      LAYER M4 ;
        RECT  0 9.168 0.084 9.192 ;
    END
  END o[20]
  PIN o[210]
    DIRECTION OUTPUT ;
    USE SIGNAL ;
    PORT
      LAYER M4 ;
        RECT  0 40.464 0.084 40.488 ;
    END
  END o[210]
  PIN o[211]
    DIRECTION OUTPUT ;
    USE SIGNAL ;
    PORT
      LAYER M4 ;
        RECT  0 40.56 0.084 40.584 ;
    END
  END o[211]
  PIN o[212]
    DIRECTION OUTPUT ;
    USE SIGNAL ;
    PORT
      LAYER M4 ;
        RECT  0 40.656 0.084 40.68 ;
    END
  END o[212]
  PIN o[213]
    DIRECTION OUTPUT ;
    USE SIGNAL ;
    PORT
      LAYER M4 ;
        RECT  0 40.752 0.084 40.776 ;
    END
  END o[213]
  PIN o[214]
    DIRECTION OUTPUT ;
    USE SIGNAL ;
    PORT
      LAYER M4 ;
        RECT  0 40.848 0.084 40.872 ;
    END
  END o[214]
  PIN o[215]
    DIRECTION OUTPUT ;
    USE SIGNAL ;
    PORT
      LAYER M4 ;
        RECT  0 40.944 0.084 40.968 ;
    END
  END o[215]
  PIN o[216]
    DIRECTION OUTPUT ;
    USE SIGNAL ;
    PORT
      LAYER M4 ;
        RECT  0 41.04 0.084 41.064 ;
    END
  END o[216]
  PIN o[217]
    DIRECTION OUTPUT ;
    USE SIGNAL ;
    PORT
      LAYER M4 ;
        RECT  0 41.136 0.084 41.16 ;
    END
  END o[217]
  PIN o[218]
    DIRECTION OUTPUT ;
    USE SIGNAL ;
    PORT
      LAYER M4 ;
        RECT  0 41.232 0.084 41.256 ;
    END
  END o[218]
  PIN o[219]
    DIRECTION OUTPUT ;
    USE SIGNAL ;
    PORT
      LAYER M4 ;
        RECT  0 41.328 0.084 41.352 ;
    END
  END o[219]
  PIN o[21]
    DIRECTION OUTPUT ;
    USE SIGNAL ;
    PORT
      LAYER M4 ;
        RECT  0 9.264 0.084 9.288 ;
    END
  END o[21]
  PIN o[220]
    DIRECTION OUTPUT ;
    USE SIGNAL ;
    PORT
      LAYER M4 ;
        RECT  0 41.424 0.084 41.448 ;
    END
  END o[220]
  PIN o[221]
    DIRECTION OUTPUT ;
    USE SIGNAL ;
    PORT
      LAYER M4 ;
        RECT  0 41.52 0.084 41.544 ;
    END
  END o[221]
  PIN o[222]
    DIRECTION OUTPUT ;
    USE SIGNAL ;
    PORT
      LAYER M4 ;
        RECT  0 41.616 0.084 41.64 ;
    END
  END o[222]
  PIN o[223]
    DIRECTION OUTPUT ;
    USE SIGNAL ;
    PORT
      LAYER M4 ;
        RECT  0 41.712 0.084 41.736 ;
    END
  END o[223]
  PIN o[224]
    DIRECTION OUTPUT ;
    USE SIGNAL ;
    PORT
      LAYER M4 ;
        RECT  0 16.464 0.084 16.488 ;
    END
  END o[224]
  PIN o[225]
    DIRECTION OUTPUT ;
    USE SIGNAL ;
    PORT
      LAYER M4 ;
        RECT  0 16.56 0.084 16.584 ;
    END
  END o[225]
  PIN o[226]
    DIRECTION OUTPUT ;
    USE SIGNAL ;
    PORT
      LAYER M4 ;
        RECT  0 16.656 0.084 16.68 ;
    END
  END o[226]
  PIN o[227]
    DIRECTION OUTPUT ;
    USE SIGNAL ;
    PORT
      LAYER M4 ;
        RECT  0 16.752 0.084 16.776 ;
    END
  END o[227]
  PIN o[228]
    DIRECTION OUTPUT ;
    USE SIGNAL ;
    PORT
      LAYER M4 ;
        RECT  0 16.848 0.084 16.872 ;
    END
  END o[228]
  PIN o[229]
    DIRECTION OUTPUT ;
    USE SIGNAL ;
    PORT
      LAYER M4 ;
        RECT  0 16.944 0.084 16.968 ;
    END
  END o[229]
  PIN o[22]
    DIRECTION OUTPUT ;
    USE SIGNAL ;
    PORT
      LAYER M4 ;
        RECT  0 9.36 0.084 9.384 ;
    END
  END o[22]
  PIN o[230]
    DIRECTION OUTPUT ;
    USE SIGNAL ;
    PORT
      LAYER M4 ;
        RECT  0 17.04 0.084 17.064 ;
    END
  END o[230]
  PIN o[231]
    DIRECTION OUTPUT ;
    USE SIGNAL ;
    PORT
      LAYER M4 ;
        RECT  0 17.136 0.084 17.16 ;
    END
  END o[231]
  PIN o[232]
    DIRECTION OUTPUT ;
    USE SIGNAL ;
    PORT
      LAYER M4 ;
        RECT  0 17.232 0.084 17.256 ;
    END
  END o[232]
  PIN o[233]
    DIRECTION OUTPUT ;
    USE SIGNAL ;
    PORT
      LAYER M4 ;
        RECT  0 17.328 0.084 17.352 ;
    END
  END o[233]
  PIN o[234]
    DIRECTION OUTPUT ;
    USE SIGNAL ;
    PORT
      LAYER M4 ;
        RECT  0 17.424 0.084 17.448 ;
    END
  END o[234]
  PIN o[235]
    DIRECTION OUTPUT ;
    USE SIGNAL ;
    PORT
      LAYER M4 ;
        RECT  0 17.52 0.084 17.544 ;
    END
  END o[235]
  PIN o[236]
    DIRECTION OUTPUT ;
    USE SIGNAL ;
    PORT
      LAYER M4 ;
        RECT  0 17.616 0.084 17.64 ;
    END
  END o[236]
  PIN o[237]
    DIRECTION OUTPUT ;
    USE SIGNAL ;
    PORT
      LAYER M4 ;
        RECT  0 17.712 0.084 17.736 ;
    END
  END o[237]
  PIN o[238]
    DIRECTION OUTPUT ;
    USE SIGNAL ;
    PORT
      LAYER M4 ;
        RECT  0 17.808 0.084 17.832 ;
    END
  END o[238]
  PIN o[239]
    DIRECTION OUTPUT ;
    USE SIGNAL ;
    PORT
      LAYER M4 ;
        RECT  0 17.904 0.084 17.928 ;
    END
  END o[239]
  PIN o[23]
    DIRECTION OUTPUT ;
    USE SIGNAL ;
    PORT
      LAYER M4 ;
        RECT  0 9.456 0.084 9.48 ;
    END
  END o[23]
  PIN o[240]
    DIRECTION OUTPUT ;
    USE SIGNAL ;
    PORT
      LAYER M4 ;
        RECT  0 18 0.084 18.024 ;
    END
  END o[240]
  PIN o[241]
    DIRECTION OUTPUT ;
    USE SIGNAL ;
    PORT
      LAYER M4 ;
        RECT  0 18.096 0.084 18.12 ;
    END
  END o[241]
  PIN o[242]
    DIRECTION OUTPUT ;
    USE SIGNAL ;
    PORT
      LAYER M4 ;
        RECT  0 18.192 0.084 18.216 ;
    END
  END o[242]
  PIN o[243]
    DIRECTION OUTPUT ;
    USE SIGNAL ;
    PORT
      LAYER M4 ;
        RECT  0 18.288 0.084 18.312 ;
    END
  END o[243]
  PIN o[244]
    DIRECTION OUTPUT ;
    USE SIGNAL ;
    PORT
      LAYER M4 ;
        RECT  0 18.384 0.084 18.408 ;
    END
  END o[244]
  PIN o[245]
    DIRECTION OUTPUT ;
    USE SIGNAL ;
    PORT
      LAYER M4 ;
        RECT  0 18.48 0.084 18.504 ;
    END
  END o[245]
  PIN o[246]
    DIRECTION OUTPUT ;
    USE SIGNAL ;
    PORT
      LAYER M4 ;
        RECT  0 18.576 0.084 18.6 ;
    END
  END o[246]
  PIN o[247]
    DIRECTION OUTPUT ;
    USE SIGNAL ;
    PORT
      LAYER M4 ;
        RECT  0 18.672 0.084 18.696 ;
    END
  END o[247]
  PIN o[248]
    DIRECTION OUTPUT ;
    USE SIGNAL ;
    PORT
      LAYER M4 ;
        RECT  0 18.768 0.084 18.792 ;
    END
  END o[248]
  PIN o[249]
    DIRECTION OUTPUT ;
    USE SIGNAL ;
    PORT
      LAYER M4 ;
        RECT  0 18.864 0.084 18.888 ;
    END
  END o[249]
  PIN o[24]
    DIRECTION OUTPUT ;
    USE SIGNAL ;
    PORT
      LAYER M4 ;
        RECT  0 9.552 0.084 9.576 ;
    END
  END o[24]
  PIN o[250]
    DIRECTION OUTPUT ;
    USE SIGNAL ;
    PORT
      LAYER M4 ;
        RECT  0 18.96 0.084 18.984 ;
    END
  END o[250]
  PIN o[251]
    DIRECTION OUTPUT ;
    USE SIGNAL ;
    PORT
      LAYER M4 ;
        RECT  0 19.056 0.084 19.08 ;
    END
  END o[251]
  PIN o[252]
    DIRECTION OUTPUT ;
    USE SIGNAL ;
    PORT
      LAYER M4 ;
        RECT  0 19.152 0.084 19.176 ;
    END
  END o[252]
  PIN o[253]
    DIRECTION OUTPUT ;
    USE SIGNAL ;
    PORT
      LAYER M4 ;
        RECT  0 19.248 0.084 19.272 ;
    END
  END o[253]
  PIN o[254]
    DIRECTION OUTPUT ;
    USE SIGNAL ;
    PORT
      LAYER M4 ;
        RECT  0 19.344 0.084 19.368 ;
    END
  END o[254]
  PIN o[255]
    DIRECTION OUTPUT ;
    USE SIGNAL ;
    PORT
      LAYER M4 ;
        RECT  0 19.44 0.084 19.464 ;
    END
  END o[255]
  PIN o[256]
    DIRECTION OUTPUT ;
    USE SIGNAL ;
    PORT
      LAYER M4 ;
        RECT  0 41.808 0.084 41.832 ;
    END
  END o[256]
  PIN o[257]
    DIRECTION OUTPUT ;
    USE SIGNAL ;
    PORT
      LAYER M4 ;
        RECT  0 41.904 0.084 41.928 ;
    END
  END o[257]
  PIN o[258]
    DIRECTION OUTPUT ;
    USE SIGNAL ;
    PORT
      LAYER M4 ;
        RECT  0 42 0.084 42.024 ;
    END
  END o[258]
  PIN o[259]
    DIRECTION OUTPUT ;
    USE SIGNAL ;
    PORT
      LAYER M4 ;
        RECT  0 42.096 0.084 42.12 ;
    END
  END o[259]
  PIN o[25]
    DIRECTION OUTPUT ;
    USE SIGNAL ;
    PORT
      LAYER M4 ;
        RECT  0 9.648 0.084 9.672 ;
    END
  END o[25]
  PIN o[260]
    DIRECTION OUTPUT ;
    USE SIGNAL ;
    PORT
      LAYER M4 ;
        RECT  0 42.192 0.084 42.216 ;
    END
  END o[260]
  PIN o[261]
    DIRECTION OUTPUT ;
    USE SIGNAL ;
    PORT
      LAYER M4 ;
        RECT  0 42.288 0.084 42.312 ;
    END
  END o[261]
  PIN o[262]
    DIRECTION OUTPUT ;
    USE SIGNAL ;
    PORT
      LAYER M4 ;
        RECT  0 42.384 0.084 42.408 ;
    END
  END o[262]
  PIN o[263]
    DIRECTION OUTPUT ;
    USE SIGNAL ;
    PORT
      LAYER M4 ;
        RECT  0 42.48 0.084 42.504 ;
    END
  END o[263]
  PIN o[264]
    DIRECTION OUTPUT ;
    USE SIGNAL ;
    PORT
      LAYER M4 ;
        RECT  0 42.576 0.084 42.6 ;
    END
  END o[264]
  PIN o[265]
    DIRECTION OUTPUT ;
    USE SIGNAL ;
    PORT
      LAYER M4 ;
        RECT  0 42.672 0.084 42.696 ;
    END
  END o[265]
  PIN o[266]
    DIRECTION OUTPUT ;
    USE SIGNAL ;
    PORT
      LAYER M4 ;
        RECT  0 42.768 0.084 42.792 ;
    END
  END o[266]
  PIN o[267]
    DIRECTION OUTPUT ;
    USE SIGNAL ;
    PORT
      LAYER M4 ;
        RECT  0 42.864 0.084 42.888 ;
    END
  END o[267]
  PIN o[268]
    DIRECTION OUTPUT ;
    USE SIGNAL ;
    PORT
      LAYER M4 ;
        RECT  0 42.96 0.084 42.984 ;
    END
  END o[268]
  PIN o[269]
    DIRECTION OUTPUT ;
    USE SIGNAL ;
    PORT
      LAYER M4 ;
        RECT  0 43.056 0.084 43.08 ;
    END
  END o[269]
  PIN o[26]
    DIRECTION OUTPUT ;
    USE SIGNAL ;
    PORT
      LAYER M4 ;
        RECT  0 9.744 0.084 9.768 ;
    END
  END o[26]
  PIN o[270]
    DIRECTION OUTPUT ;
    USE SIGNAL ;
    PORT
      LAYER M4 ;
        RECT  0 43.152 0.084 43.176 ;
    END
  END o[270]
  PIN o[271]
    DIRECTION OUTPUT ;
    USE SIGNAL ;
    PORT
      LAYER M4 ;
        RECT  0 43.248 0.084 43.272 ;
    END
  END o[271]
  PIN o[272]
    DIRECTION OUTPUT ;
    USE SIGNAL ;
    PORT
      LAYER M4 ;
        RECT  0 43.344 0.084 43.368 ;
    END
  END o[272]
  PIN o[273]
    DIRECTION OUTPUT ;
    USE SIGNAL ;
    PORT
      LAYER M4 ;
        RECT  0 43.44 0.084 43.464 ;
    END
  END o[273]
  PIN o[274]
    DIRECTION OUTPUT ;
    USE SIGNAL ;
    PORT
      LAYER M4 ;
        RECT  0 43.536 0.084 43.56 ;
    END
  END o[274]
  PIN o[275]
    DIRECTION OUTPUT ;
    USE SIGNAL ;
    PORT
      LAYER M4 ;
        RECT  0 43.632 0.084 43.656 ;
    END
  END o[275]
  PIN o[276]
    DIRECTION OUTPUT ;
    USE SIGNAL ;
    PORT
      LAYER M4 ;
        RECT  0 43.728 0.084 43.752 ;
    END
  END o[276]
  PIN o[277]
    DIRECTION OUTPUT ;
    USE SIGNAL ;
    PORT
      LAYER M4 ;
        RECT  0 43.824 0.084 43.848 ;
    END
  END o[277]
  PIN o[278]
    DIRECTION OUTPUT ;
    USE SIGNAL ;
    PORT
      LAYER M4 ;
        RECT  0 43.92 0.084 43.944 ;
    END
  END o[278]
  PIN o[279]
    DIRECTION OUTPUT ;
    USE SIGNAL ;
    PORT
      LAYER M4 ;
        RECT  0 44.016 0.084 44.04 ;
    END
  END o[279]
  PIN o[27]
    DIRECTION OUTPUT ;
    USE SIGNAL ;
    PORT
      LAYER M4 ;
        RECT  0 9.84 0.084 9.864 ;
    END
  END o[27]
  PIN o[280]
    DIRECTION OUTPUT ;
    USE SIGNAL ;
    PORT
      LAYER M4 ;
        RECT  0 44.112 0.084 44.136 ;
    END
  END o[280]
  PIN o[281]
    DIRECTION OUTPUT ;
    USE SIGNAL ;
    PORT
      LAYER M4 ;
        RECT  0 44.208 0.084 44.232 ;
    END
  END o[281]
  PIN o[282]
    DIRECTION OUTPUT ;
    USE SIGNAL ;
    PORT
      LAYER M4 ;
        RECT  0 44.304 0.084 44.328 ;
    END
  END o[282]
  PIN o[283]
    DIRECTION OUTPUT ;
    USE SIGNAL ;
    PORT
      LAYER M4 ;
        RECT  0 44.4 0.084 44.424 ;
    END
  END o[283]
  PIN o[284]
    DIRECTION OUTPUT ;
    USE SIGNAL ;
    PORT
      LAYER M4 ;
        RECT  0 44.496 0.084 44.52 ;
    END
  END o[284]
  PIN o[285]
    DIRECTION OUTPUT ;
    USE SIGNAL ;
    PORT
      LAYER M4 ;
        RECT  0 44.592 0.084 44.616 ;
    END
  END o[285]
  PIN o[286]
    DIRECTION OUTPUT ;
    USE SIGNAL ;
    PORT
      LAYER M4 ;
        RECT  0 44.688 0.084 44.712 ;
    END
  END o[286]
  PIN o[287]
    DIRECTION OUTPUT ;
    USE SIGNAL ;
    PORT
      LAYER M4 ;
        RECT  0 44.784 0.084 44.808 ;
    END
  END o[287]
  PIN o[288]
    DIRECTION OUTPUT ;
    USE SIGNAL ;
    PORT
      LAYER M4 ;
        RECT  0 45.648 0.084 45.672 ;
    END
  END o[288]
  PIN o[289]
    DIRECTION OUTPUT ;
    USE SIGNAL ;
    PORT
      LAYER M4 ;
        RECT  0 45.744 0.084 45.768 ;
    END
  END o[289]
  PIN o[28]
    DIRECTION OUTPUT ;
    USE SIGNAL ;
    PORT
      LAYER M4 ;
        RECT  0 9.936 0.084 9.96 ;
    END
  END o[28]
  PIN o[290]
    DIRECTION OUTPUT ;
    USE SIGNAL ;
    PORT
      LAYER M4 ;
        RECT  0 45.84 0.084 45.864 ;
    END
  END o[290]
  PIN o[291]
    DIRECTION OUTPUT ;
    USE SIGNAL ;
    PORT
      LAYER M4 ;
        RECT  0 45.936 0.084 45.96 ;
    END
  END o[291]
  PIN o[292]
    DIRECTION OUTPUT ;
    USE SIGNAL ;
    PORT
      LAYER M4 ;
        RECT  0 46.032 0.084 46.056 ;
    END
  END o[292]
  PIN o[293]
    DIRECTION OUTPUT ;
    USE SIGNAL ;
    PORT
      LAYER M4 ;
        RECT  0 46.128 0.084 46.152 ;
    END
  END o[293]
  PIN o[294]
    DIRECTION OUTPUT ;
    USE SIGNAL ;
    PORT
      LAYER M4 ;
        RECT  0 46.224 0.084 46.248 ;
    END
  END o[294]
  PIN o[295]
    DIRECTION OUTPUT ;
    USE SIGNAL ;
    PORT
      LAYER M4 ;
        RECT  0 46.32 0.084 46.344 ;
    END
  END o[295]
  PIN o[296]
    DIRECTION OUTPUT ;
    USE SIGNAL ;
    PORT
      LAYER M4 ;
        RECT  0 46.416 0.084 46.44 ;
    END
  END o[296]
  PIN o[297]
    DIRECTION OUTPUT ;
    USE SIGNAL ;
    PORT
      LAYER M4 ;
        RECT  0 46.512 0.084 46.536 ;
    END
  END o[297]
  PIN o[298]
    DIRECTION OUTPUT ;
    USE SIGNAL ;
    PORT
      LAYER M4 ;
        RECT  0 46.608 0.084 46.632 ;
    END
  END o[298]
  PIN o[299]
    DIRECTION OUTPUT ;
    USE SIGNAL ;
    PORT
      LAYER M4 ;
        RECT  0 46.704 0.084 46.728 ;
    END
  END o[299]
  PIN o[29]
    DIRECTION OUTPUT ;
    USE SIGNAL ;
    PORT
      LAYER M4 ;
        RECT  0 10.032 0.084 10.056 ;
    END
  END o[29]
  PIN o[2]
    DIRECTION OUTPUT ;
    USE SIGNAL ;
    PORT
      LAYER M4 ;
        RECT  0 7.44 0.084 7.464 ;
    END
  END o[2]
  PIN o[300]
    DIRECTION OUTPUT ;
    USE SIGNAL ;
    PORT
      LAYER M4 ;
        RECT  0 46.8 0.084 46.824 ;
    END
  END o[300]
  PIN o[301]
    DIRECTION OUTPUT ;
    USE SIGNAL ;
    PORT
      LAYER M4 ;
        RECT  0 46.896 0.084 46.92 ;
    END
  END o[301]
  PIN o[302]
    DIRECTION OUTPUT ;
    USE SIGNAL ;
    PORT
      LAYER M4 ;
        RECT  0 46.992 0.084 47.016 ;
    END
  END o[302]
  PIN o[303]
    DIRECTION OUTPUT ;
    USE SIGNAL ;
    PORT
      LAYER M4 ;
        RECT  0 47.088 0.084 47.112 ;
    END
  END o[303]
  PIN o[304]
    DIRECTION OUTPUT ;
    USE SIGNAL ;
    PORT
      LAYER M4 ;
        RECT  0 47.184 0.084 47.208 ;
    END
  END o[304]
  PIN o[305]
    DIRECTION OUTPUT ;
    USE SIGNAL ;
    PORT
      LAYER M4 ;
        RECT  0 47.28 0.084 47.304 ;
    END
  END o[305]
  PIN o[306]
    DIRECTION OUTPUT ;
    USE SIGNAL ;
    PORT
      LAYER M4 ;
        RECT  0 47.376 0.084 47.4 ;
    END
  END o[306]
  PIN o[307]
    DIRECTION OUTPUT ;
    USE SIGNAL ;
    PORT
      LAYER M4 ;
        RECT  0 47.472 0.084 47.496 ;
    END
  END o[307]
  PIN o[308]
    DIRECTION OUTPUT ;
    USE SIGNAL ;
    PORT
      LAYER M4 ;
        RECT  0 47.568 0.084 47.592 ;
    END
  END o[308]
  PIN o[309]
    DIRECTION OUTPUT ;
    USE SIGNAL ;
    PORT
      LAYER M4 ;
        RECT  0 47.664 0.084 47.688 ;
    END
  END o[309]
  PIN o[30]
    DIRECTION OUTPUT ;
    USE SIGNAL ;
    PORT
      LAYER M4 ;
        RECT  0 10.128 0.084 10.152 ;
    END
  END o[30]
  PIN o[310]
    DIRECTION OUTPUT ;
    USE SIGNAL ;
    PORT
      LAYER M4 ;
        RECT  0 47.76 0.084 47.784 ;
    END
  END o[310]
  PIN o[311]
    DIRECTION OUTPUT ;
    USE SIGNAL ;
    PORT
      LAYER M4 ;
        RECT  0 47.856 0.084 47.88 ;
    END
  END o[311]
  PIN o[312]
    DIRECTION OUTPUT ;
    USE SIGNAL ;
    PORT
      LAYER M4 ;
        RECT  0 47.952 0.084 47.976 ;
    END
  END o[312]
  PIN o[313]
    DIRECTION OUTPUT ;
    USE SIGNAL ;
    PORT
      LAYER M4 ;
        RECT  0 48.048 0.084 48.072 ;
    END
  END o[313]
  PIN o[314]
    DIRECTION OUTPUT ;
    USE SIGNAL ;
    PORT
      LAYER M4 ;
        RECT  0 48.144 0.084 48.168 ;
    END
  END o[314]
  PIN o[315]
    DIRECTION OUTPUT ;
    USE SIGNAL ;
    PORT
      LAYER M4 ;
        RECT  0 48.24 0.084 48.264 ;
    END
  END o[315]
  PIN o[316]
    DIRECTION OUTPUT ;
    USE SIGNAL ;
    PORT
      LAYER M4 ;
        RECT  0 48.336 0.084 48.36 ;
    END
  END o[316]
  PIN o[317]
    DIRECTION OUTPUT ;
    USE SIGNAL ;
    PORT
      LAYER M4 ;
        RECT  0 48.432 0.084 48.456 ;
    END
  END o[317]
  PIN o[318]
    DIRECTION OUTPUT ;
    USE SIGNAL ;
    PORT
      LAYER M4 ;
        RECT  0 48.528 0.084 48.552 ;
    END
  END o[318]
  PIN o[319]
    DIRECTION OUTPUT ;
    USE SIGNAL ;
    PORT
      LAYER M4 ;
        RECT  0 48.624 0.084 48.648 ;
    END
  END o[319]
  PIN o[31]
    DIRECTION OUTPUT ;
    USE SIGNAL ;
    PORT
      LAYER M4 ;
        RECT  0 10.224 0.084 10.248 ;
    END
  END o[31]
  PIN o[320]
    DIRECTION OUTPUT ;
    USE SIGNAL ;
    PORT
      LAYER M4 ;
        RECT  0 57.936 0.084 57.96 ;
    END
  END o[320]
  PIN o[321]
    DIRECTION OUTPUT ;
    USE SIGNAL ;
    PORT
      LAYER M4 ;
        RECT  0 58.032 0.084 58.056 ;
    END
  END o[321]
  PIN o[322]
    DIRECTION OUTPUT ;
    USE SIGNAL ;
    PORT
      LAYER M4 ;
        RECT  0 58.128 0.084 58.152 ;
    END
  END o[322]
  PIN o[323]
    DIRECTION OUTPUT ;
    USE SIGNAL ;
    PORT
      LAYER M4 ;
        RECT  0 58.224 0.084 58.248 ;
    END
  END o[323]
  PIN o[324]
    DIRECTION OUTPUT ;
    USE SIGNAL ;
    PORT
      LAYER M4 ;
        RECT  0 58.32 0.084 58.344 ;
    END
  END o[324]
  PIN o[325]
    DIRECTION OUTPUT ;
    USE SIGNAL ;
    PORT
      LAYER M4 ;
        RECT  0 58.416 0.084 58.44 ;
    END
  END o[325]
  PIN o[326]
    DIRECTION OUTPUT ;
    USE SIGNAL ;
    PORT
      LAYER M4 ;
        RECT  0 58.512 0.084 58.536 ;
    END
  END o[326]
  PIN o[327]
    DIRECTION OUTPUT ;
    USE SIGNAL ;
    PORT
      LAYER M4 ;
        RECT  0 58.608 0.084 58.632 ;
    END
  END o[327]
  PIN o[328]
    DIRECTION OUTPUT ;
    USE SIGNAL ;
    PORT
      LAYER M4 ;
        RECT  0 58.704 0.084 58.728 ;
    END
  END o[328]
  PIN o[329]
    DIRECTION OUTPUT ;
    USE SIGNAL ;
    PORT
      LAYER M4 ;
        RECT  0 58.8 0.084 58.824 ;
    END
  END o[329]
  PIN o[32]
    DIRECTION OUTPUT ;
    USE SIGNAL ;
    PORT
      LAYER M4 ;
        RECT  0 29.52 0.084 29.544 ;
    END
  END o[32]
  PIN o[330]
    DIRECTION OUTPUT ;
    USE SIGNAL ;
    PORT
      LAYER M4 ;
        RECT  0 58.896 0.084 58.92 ;
    END
  END o[330]
  PIN o[331]
    DIRECTION OUTPUT ;
    USE SIGNAL ;
    PORT
      LAYER M4 ;
        RECT  0 58.992 0.084 59.016 ;
    END
  END o[331]
  PIN o[332]
    DIRECTION OUTPUT ;
    USE SIGNAL ;
    PORT
      LAYER M4 ;
        RECT  0 59.088 0.084 59.112 ;
    END
  END o[332]
  PIN o[333]
    DIRECTION OUTPUT ;
    USE SIGNAL ;
    PORT
      LAYER M4 ;
        RECT  0 59.184 0.084 59.208 ;
    END
  END o[333]
  PIN o[334]
    DIRECTION OUTPUT ;
    USE SIGNAL ;
    PORT
      LAYER M4 ;
        RECT  0 59.28 0.084 59.304 ;
    END
  END o[334]
  PIN o[335]
    DIRECTION OUTPUT ;
    USE SIGNAL ;
    PORT
      LAYER M4 ;
        RECT  0 59.376 0.084 59.4 ;
    END
  END o[335]
  PIN o[336]
    DIRECTION OUTPUT ;
    USE SIGNAL ;
    PORT
      LAYER M4 ;
        RECT  0 59.472 0.084 59.496 ;
    END
  END o[336]
  PIN o[337]
    DIRECTION OUTPUT ;
    USE SIGNAL ;
    PORT
      LAYER M4 ;
        RECT  0 59.568 0.084 59.592 ;
    END
  END o[337]
  PIN o[338]
    DIRECTION OUTPUT ;
    USE SIGNAL ;
    PORT
      LAYER M4 ;
        RECT  0 59.664 0.084 59.688 ;
    END
  END o[338]
  PIN o[339]
    DIRECTION OUTPUT ;
    USE SIGNAL ;
    PORT
      LAYER M4 ;
        RECT  0 59.76 0.084 59.784 ;
    END
  END o[339]
  PIN o[33]
    DIRECTION OUTPUT ;
    USE SIGNAL ;
    PORT
      LAYER M4 ;
        RECT  0 29.616 0.084 29.64 ;
    END
  END o[33]
  PIN o[340]
    DIRECTION OUTPUT ;
    USE SIGNAL ;
    PORT
      LAYER M4 ;
        RECT  0 59.856 0.084 59.88 ;
    END
  END o[340]
  PIN o[341]
    DIRECTION OUTPUT ;
    USE SIGNAL ;
    PORT
      LAYER M4 ;
        RECT  0 59.952 0.084 59.976 ;
    END
  END o[341]
  PIN o[342]
    DIRECTION OUTPUT ;
    USE SIGNAL ;
    PORT
      LAYER M4 ;
        RECT  0 60.048 0.084 60.072 ;
    END
  END o[342]
  PIN o[343]
    DIRECTION OUTPUT ;
    USE SIGNAL ;
    PORT
      LAYER M4 ;
        RECT  0 60.144 0.084 60.168 ;
    END
  END o[343]
  PIN o[344]
    DIRECTION OUTPUT ;
    USE SIGNAL ;
    PORT
      LAYER M4 ;
        RECT  0 60.24 0.084 60.264 ;
    END
  END o[344]
  PIN o[345]
    DIRECTION OUTPUT ;
    USE SIGNAL ;
    PORT
      LAYER M4 ;
        RECT  0 60.336 0.084 60.36 ;
    END
  END o[345]
  PIN o[346]
    DIRECTION OUTPUT ;
    USE SIGNAL ;
    PORT
      LAYER M4 ;
        RECT  0 60.432 0.084 60.456 ;
    END
  END o[346]
  PIN o[347]
    DIRECTION OUTPUT ;
    USE SIGNAL ;
    PORT
      LAYER M4 ;
        RECT  0 60.528 0.084 60.552 ;
    END
  END o[347]
  PIN o[348]
    DIRECTION OUTPUT ;
    USE SIGNAL ;
    PORT
      LAYER M4 ;
        RECT  0 60.624 0.084 60.648 ;
    END
  END o[348]
  PIN o[349]
    DIRECTION OUTPUT ;
    USE SIGNAL ;
    PORT
      LAYER M4 ;
        RECT  0 60.72 0.084 60.744 ;
    END
  END o[349]
  PIN o[34]
    DIRECTION OUTPUT ;
    USE SIGNAL ;
    PORT
      LAYER M4 ;
        RECT  0 29.712 0.084 29.736 ;
    END
  END o[34]
  PIN o[350]
    DIRECTION OUTPUT ;
    USE SIGNAL ;
    PORT
      LAYER M4 ;
        RECT  0 60.816 0.084 60.84 ;
    END
  END o[350]
  PIN o[351]
    DIRECTION OUTPUT ;
    USE SIGNAL ;
    PORT
      LAYER M4 ;
        RECT  0 60.912 0.084 60.936 ;
    END
  END o[351]
  PIN o[352]
    DIRECTION OUTPUT ;
    USE SIGNAL ;
    PORT
      LAYER M4 ;
        RECT  0 48.72 0.084 48.744 ;
    END
  END o[352]
  PIN o[353]
    DIRECTION OUTPUT ;
    USE SIGNAL ;
    PORT
      LAYER M4 ;
        RECT  0 48.816 0.084 48.84 ;
    END
  END o[353]
  PIN o[354]
    DIRECTION OUTPUT ;
    USE SIGNAL ;
    PORT
      LAYER M4 ;
        RECT  0 48.912 0.084 48.936 ;
    END
  END o[354]
  PIN o[355]
    DIRECTION OUTPUT ;
    USE SIGNAL ;
    PORT
      LAYER M4 ;
        RECT  0 49.008 0.084 49.032 ;
    END
  END o[355]
  PIN o[356]
    DIRECTION OUTPUT ;
    USE SIGNAL ;
    PORT
      LAYER M4 ;
        RECT  0 49.104 0.084 49.128 ;
    END
  END o[356]
  PIN o[357]
    DIRECTION OUTPUT ;
    USE SIGNAL ;
    PORT
      LAYER M4 ;
        RECT  0 49.2 0.084 49.224 ;
    END
  END o[357]
  PIN o[358]
    DIRECTION OUTPUT ;
    USE SIGNAL ;
    PORT
      LAYER M4 ;
        RECT  0 49.296 0.084 49.32 ;
    END
  END o[358]
  PIN o[359]
    DIRECTION OUTPUT ;
    USE SIGNAL ;
    PORT
      LAYER M4 ;
        RECT  0 49.392 0.084 49.416 ;
    END
  END o[359]
  PIN o[35]
    DIRECTION OUTPUT ;
    USE SIGNAL ;
    PORT
      LAYER M4 ;
        RECT  0 29.808 0.084 29.832 ;
    END
  END o[35]
  PIN o[360]
    DIRECTION OUTPUT ;
    USE SIGNAL ;
    PORT
      LAYER M4 ;
        RECT  0 49.488 0.084 49.512 ;
    END
  END o[360]
  PIN o[361]
    DIRECTION OUTPUT ;
    USE SIGNAL ;
    PORT
      LAYER M4 ;
        RECT  0 49.584 0.084 49.608 ;
    END
  END o[361]
  PIN o[362]
    DIRECTION OUTPUT ;
    USE SIGNAL ;
    PORT
      LAYER M4 ;
        RECT  0 49.68 0.084 49.704 ;
    END
  END o[362]
  PIN o[363]
    DIRECTION OUTPUT ;
    USE SIGNAL ;
    PORT
      LAYER M4 ;
        RECT  0 49.776 0.084 49.8 ;
    END
  END o[363]
  PIN o[364]
    DIRECTION OUTPUT ;
    USE SIGNAL ;
    PORT
      LAYER M4 ;
        RECT  0 49.872 0.084 49.896 ;
    END
  END o[364]
  PIN o[365]
    DIRECTION OUTPUT ;
    USE SIGNAL ;
    PORT
      LAYER M4 ;
        RECT  0 49.968 0.084 49.992 ;
    END
  END o[365]
  PIN o[366]
    DIRECTION OUTPUT ;
    USE SIGNAL ;
    PORT
      LAYER M4 ;
        RECT  0 50.064 0.084 50.088 ;
    END
  END o[366]
  PIN o[367]
    DIRECTION OUTPUT ;
    USE SIGNAL ;
    PORT
      LAYER M4 ;
        RECT  0 50.16 0.084 50.184 ;
    END
  END o[367]
  PIN o[368]
    DIRECTION OUTPUT ;
    USE SIGNAL ;
    PORT
      LAYER M4 ;
        RECT  0 50.256 0.084 50.28 ;
    END
  END o[368]
  PIN o[369]
    DIRECTION OUTPUT ;
    USE SIGNAL ;
    PORT
      LAYER M4 ;
        RECT  0 50.352 0.084 50.376 ;
    END
  END o[369]
  PIN o[36]
    DIRECTION OUTPUT ;
    USE SIGNAL ;
    PORT
      LAYER M4 ;
        RECT  0 29.904 0.084 29.928 ;
    END
  END o[36]
  PIN o[370]
    DIRECTION OUTPUT ;
    USE SIGNAL ;
    PORT
      LAYER M4 ;
        RECT  0 50.448 0.084 50.472 ;
    END
  END o[370]
  PIN o[371]
    DIRECTION OUTPUT ;
    USE SIGNAL ;
    PORT
      LAYER M4 ;
        RECT  0 50.544 0.084 50.568 ;
    END
  END o[371]
  PIN o[372]
    DIRECTION OUTPUT ;
    USE SIGNAL ;
    PORT
      LAYER M4 ;
        RECT  0 50.64 0.084 50.664 ;
    END
  END o[372]
  PIN o[373]
    DIRECTION OUTPUT ;
    USE SIGNAL ;
    PORT
      LAYER M4 ;
        RECT  0 50.736 0.084 50.76 ;
    END
  END o[373]
  PIN o[374]
    DIRECTION OUTPUT ;
    USE SIGNAL ;
    PORT
      LAYER M4 ;
        RECT  0 50.832 0.084 50.856 ;
    END
  END o[374]
  PIN o[375]
    DIRECTION OUTPUT ;
    USE SIGNAL ;
    PORT
      LAYER M4 ;
        RECT  0 50.928 0.084 50.952 ;
    END
  END o[375]
  PIN o[376]
    DIRECTION OUTPUT ;
    USE SIGNAL ;
    PORT
      LAYER M4 ;
        RECT  0 51.024 0.084 51.048 ;
    END
  END o[376]
  PIN o[377]
    DIRECTION OUTPUT ;
    USE SIGNAL ;
    PORT
      LAYER M4 ;
        RECT  0 51.12 0.084 51.144 ;
    END
  END o[377]
  PIN o[378]
    DIRECTION OUTPUT ;
    USE SIGNAL ;
    PORT
      LAYER M4 ;
        RECT  0 51.216 0.084 51.24 ;
    END
  END o[378]
  PIN o[379]
    DIRECTION OUTPUT ;
    USE SIGNAL ;
    PORT
      LAYER M4 ;
        RECT  0 51.312 0.084 51.336 ;
    END
  END o[379]
  PIN o[37]
    DIRECTION OUTPUT ;
    USE SIGNAL ;
    PORT
      LAYER M4 ;
        RECT  0 30 0.084 30.024 ;
    END
  END o[37]
  PIN o[380]
    DIRECTION OUTPUT ;
    USE SIGNAL ;
    PORT
      LAYER M4 ;
        RECT  0 51.408 0.084 51.432 ;
    END
  END o[380]
  PIN o[381]
    DIRECTION OUTPUT ;
    USE SIGNAL ;
    PORT
      LAYER M4 ;
        RECT  0 51.504 0.084 51.528 ;
    END
  END o[381]
  PIN o[382]
    DIRECTION OUTPUT ;
    USE SIGNAL ;
    PORT
      LAYER M4 ;
        RECT  0 51.6 0.084 51.624 ;
    END
  END o[382]
  PIN o[383]
    DIRECTION OUTPUT ;
    USE SIGNAL ;
    PORT
      LAYER M4 ;
        RECT  0 51.696 0.084 51.72 ;
    END
  END o[383]
  PIN o[384]
    DIRECTION OUTPUT ;
    USE SIGNAL ;
    PORT
      LAYER M4 ;
        RECT  0 61.008 0.084 61.032 ;
    END
  END o[384]
  PIN o[385]
    DIRECTION OUTPUT ;
    USE SIGNAL ;
    PORT
      LAYER M4 ;
        RECT  0 61.104 0.084 61.128 ;
    END
  END o[385]
  PIN o[386]
    DIRECTION OUTPUT ;
    USE SIGNAL ;
    PORT
      LAYER M4 ;
        RECT  0 61.2 0.084 61.224 ;
    END
  END o[386]
  PIN o[387]
    DIRECTION OUTPUT ;
    USE SIGNAL ;
    PORT
      LAYER M4 ;
        RECT  0 61.296 0.084 61.32 ;
    END
  END o[387]
  PIN o[388]
    DIRECTION OUTPUT ;
    USE SIGNAL ;
    PORT
      LAYER M4 ;
        RECT  0 61.392 0.084 61.416 ;
    END
  END o[388]
  PIN o[389]
    DIRECTION OUTPUT ;
    USE SIGNAL ;
    PORT
      LAYER M4 ;
        RECT  0 61.488 0.084 61.512 ;
    END
  END o[389]
  PIN o[38]
    DIRECTION OUTPUT ;
    USE SIGNAL ;
    PORT
      LAYER M4 ;
        RECT  0 30.096 0.084 30.12 ;
    END
  END o[38]
  PIN o[390]
    DIRECTION OUTPUT ;
    USE SIGNAL ;
    PORT
      LAYER M4 ;
        RECT  0 61.584 0.084 61.608 ;
    END
  END o[390]
  PIN o[391]
    DIRECTION OUTPUT ;
    USE SIGNAL ;
    PORT
      LAYER M4 ;
        RECT  0 61.68 0.084 61.704 ;
    END
  END o[391]
  PIN o[392]
    DIRECTION OUTPUT ;
    USE SIGNAL ;
    PORT
      LAYER M4 ;
        RECT  0 61.776 0.084 61.8 ;
    END
  END o[392]
  PIN o[393]
    DIRECTION OUTPUT ;
    USE SIGNAL ;
    PORT
      LAYER M4 ;
        RECT  0 61.872 0.084 61.896 ;
    END
  END o[393]
  PIN o[394]
    DIRECTION OUTPUT ;
    USE SIGNAL ;
    PORT
      LAYER M4 ;
        RECT  0 61.968 0.084 61.992 ;
    END
  END o[394]
  PIN o[395]
    DIRECTION OUTPUT ;
    USE SIGNAL ;
    PORT
      LAYER M4 ;
        RECT  0 62.064 0.084 62.088 ;
    END
  END o[395]
  PIN o[396]
    DIRECTION OUTPUT ;
    USE SIGNAL ;
    PORT
      LAYER M4 ;
        RECT  0 62.16 0.084 62.184 ;
    END
  END o[396]
  PIN o[397]
    DIRECTION OUTPUT ;
    USE SIGNAL ;
    PORT
      LAYER M4 ;
        RECT  0 62.256 0.084 62.28 ;
    END
  END o[397]
  PIN o[398]
    DIRECTION OUTPUT ;
    USE SIGNAL ;
    PORT
      LAYER M4 ;
        RECT  0 62.352 0.084 62.376 ;
    END
  END o[398]
  PIN o[399]
    DIRECTION OUTPUT ;
    USE SIGNAL ;
    PORT
      LAYER M4 ;
        RECT  0 62.448 0.084 62.472 ;
    END
  END o[399]
  PIN o[39]
    DIRECTION OUTPUT ;
    USE SIGNAL ;
    PORT
      LAYER M4 ;
        RECT  0 30.192 0.084 30.216 ;
    END
  END o[39]
  PIN o[3]
    DIRECTION OUTPUT ;
    USE SIGNAL ;
    PORT
      LAYER M4 ;
        RECT  0 7.536 0.084 7.56 ;
    END
  END o[3]
  PIN o[400]
    DIRECTION OUTPUT ;
    USE SIGNAL ;
    PORT
      LAYER M4 ;
        RECT  0 62.544 0.084 62.568 ;
    END
  END o[400]
  PIN o[401]
    DIRECTION OUTPUT ;
    USE SIGNAL ;
    PORT
      LAYER M4 ;
        RECT  0 62.64 0.084 62.664 ;
    END
  END o[401]
  PIN o[402]
    DIRECTION OUTPUT ;
    USE SIGNAL ;
    PORT
      LAYER M4 ;
        RECT  0 62.736 0.084 62.76 ;
    END
  END o[402]
  PIN o[403]
    DIRECTION OUTPUT ;
    USE SIGNAL ;
    PORT
      LAYER M4 ;
        RECT  0 62.832 0.084 62.856 ;
    END
  END o[403]
  PIN o[404]
    DIRECTION OUTPUT ;
    USE SIGNAL ;
    PORT
      LAYER M4 ;
        RECT  0 62.928 0.084 62.952 ;
    END
  END o[404]
  PIN o[405]
    DIRECTION OUTPUT ;
    USE SIGNAL ;
    PORT
      LAYER M4 ;
        RECT  0 63.024 0.084 63.048 ;
    END
  END o[405]
  PIN o[406]
    DIRECTION OUTPUT ;
    USE SIGNAL ;
    PORT
      LAYER M4 ;
        RECT  0 63.12 0.084 63.144 ;
    END
  END o[406]
  PIN o[407]
    DIRECTION OUTPUT ;
    USE SIGNAL ;
    PORT
      LAYER M4 ;
        RECT  0 63.216 0.084 63.24 ;
    END
  END o[407]
  PIN o[408]
    DIRECTION OUTPUT ;
    USE SIGNAL ;
    PORT
      LAYER M4 ;
        RECT  0 63.312 0.084 63.336 ;
    END
  END o[408]
  PIN o[409]
    DIRECTION OUTPUT ;
    USE SIGNAL ;
    PORT
      LAYER M4 ;
        RECT  0 63.408 0.084 63.432 ;
    END
  END o[409]
  PIN o[40]
    DIRECTION OUTPUT ;
    USE SIGNAL ;
    PORT
      LAYER M4 ;
        RECT  0 30.288 0.084 30.312 ;
    END
  END o[40]
  PIN o[410]
    DIRECTION OUTPUT ;
    USE SIGNAL ;
    PORT
      LAYER M4 ;
        RECT  0 63.504 0.084 63.528 ;
    END
  END o[410]
  PIN o[411]
    DIRECTION OUTPUT ;
    USE SIGNAL ;
    PORT
      LAYER M4 ;
        RECT  0 63.6 0.084 63.624 ;
    END
  END o[411]
  PIN o[412]
    DIRECTION OUTPUT ;
    USE SIGNAL ;
    PORT
      LAYER M4 ;
        RECT  0 63.696 0.084 63.72 ;
    END
  END o[412]
  PIN o[413]
    DIRECTION OUTPUT ;
    USE SIGNAL ;
    PORT
      LAYER M4 ;
        RECT  0 63.792 0.084 63.816 ;
    END
  END o[413]
  PIN o[414]
    DIRECTION OUTPUT ;
    USE SIGNAL ;
    PORT
      LAYER M4 ;
        RECT  0 63.888 0.084 63.912 ;
    END
  END o[414]
  PIN o[415]
    DIRECTION OUTPUT ;
    USE SIGNAL ;
    PORT
      LAYER M4 ;
        RECT  0 63.984 0.084 64.008 ;
    END
  END o[415]
  PIN o[416]
    DIRECTION OUTPUT ;
    USE SIGNAL ;
    PORT
      LAYER M4 ;
        RECT  0 54.864 0.084 54.888 ;
    END
  END o[416]
  PIN o[417]
    DIRECTION OUTPUT ;
    USE SIGNAL ;
    PORT
      LAYER M4 ;
        RECT  0 54.96 0.084 54.984 ;
    END
  END o[417]
  PIN o[418]
    DIRECTION OUTPUT ;
    USE SIGNAL ;
    PORT
      LAYER M4 ;
        RECT  0 55.056 0.084 55.08 ;
    END
  END o[418]
  PIN o[419]
    DIRECTION OUTPUT ;
    USE SIGNAL ;
    PORT
      LAYER M4 ;
        RECT  0 55.152 0.084 55.176 ;
    END
  END o[419]
  PIN o[41]
    DIRECTION OUTPUT ;
    USE SIGNAL ;
    PORT
      LAYER M4 ;
        RECT  0 30.384 0.084 30.408 ;
    END
  END o[41]
  PIN o[420]
    DIRECTION OUTPUT ;
    USE SIGNAL ;
    PORT
      LAYER M4 ;
        RECT  0 55.248 0.084 55.272 ;
    END
  END o[420]
  PIN o[421]
    DIRECTION OUTPUT ;
    USE SIGNAL ;
    PORT
      LAYER M4 ;
        RECT  0 55.344 0.084 55.368 ;
    END
  END o[421]
  PIN o[422]
    DIRECTION OUTPUT ;
    USE SIGNAL ;
    PORT
      LAYER M4 ;
        RECT  0 55.44 0.084 55.464 ;
    END
  END o[422]
  PIN o[423]
    DIRECTION OUTPUT ;
    USE SIGNAL ;
    PORT
      LAYER M4 ;
        RECT  0 55.536 0.084 55.56 ;
    END
  END o[423]
  PIN o[424]
    DIRECTION OUTPUT ;
    USE SIGNAL ;
    PORT
      LAYER M4 ;
        RECT  0 55.632 0.084 55.656 ;
    END
  END o[424]
  PIN o[425]
    DIRECTION OUTPUT ;
    USE SIGNAL ;
    PORT
      LAYER M4 ;
        RECT  0 55.728 0.084 55.752 ;
    END
  END o[425]
  PIN o[426]
    DIRECTION OUTPUT ;
    USE SIGNAL ;
    PORT
      LAYER M4 ;
        RECT  0 55.824 0.084 55.848 ;
    END
  END o[426]
  PIN o[427]
    DIRECTION OUTPUT ;
    USE SIGNAL ;
    PORT
      LAYER M4 ;
        RECT  0 55.92 0.084 55.944 ;
    END
  END o[427]
  PIN o[428]
    DIRECTION OUTPUT ;
    USE SIGNAL ;
    PORT
      LAYER M4 ;
        RECT  0 56.016 0.084 56.04 ;
    END
  END o[428]
  PIN o[429]
    DIRECTION OUTPUT ;
    USE SIGNAL ;
    PORT
      LAYER M4 ;
        RECT  0 56.112 0.084 56.136 ;
    END
  END o[429]
  PIN o[42]
    DIRECTION OUTPUT ;
    USE SIGNAL ;
    PORT
      LAYER M4 ;
        RECT  0 30.48 0.084 30.504 ;
    END
  END o[42]
  PIN o[430]
    DIRECTION OUTPUT ;
    USE SIGNAL ;
    PORT
      LAYER M4 ;
        RECT  0 56.208 0.084 56.232 ;
    END
  END o[430]
  PIN o[431]
    DIRECTION OUTPUT ;
    USE SIGNAL ;
    PORT
      LAYER M4 ;
        RECT  0 56.304 0.084 56.328 ;
    END
  END o[431]
  PIN o[432]
    DIRECTION OUTPUT ;
    USE SIGNAL ;
    PORT
      LAYER M4 ;
        RECT  0 56.4 0.084 56.424 ;
    END
  END o[432]
  PIN o[433]
    DIRECTION OUTPUT ;
    USE SIGNAL ;
    PORT
      LAYER M4 ;
        RECT  0 56.496 0.084 56.52 ;
    END
  END o[433]
  PIN o[434]
    DIRECTION OUTPUT ;
    USE SIGNAL ;
    PORT
      LAYER M4 ;
        RECT  0 56.592 0.084 56.616 ;
    END
  END o[434]
  PIN o[435]
    DIRECTION OUTPUT ;
    USE SIGNAL ;
    PORT
      LAYER M4 ;
        RECT  0 56.688 0.084 56.712 ;
    END
  END o[435]
  PIN o[436]
    DIRECTION OUTPUT ;
    USE SIGNAL ;
    PORT
      LAYER M4 ;
        RECT  0 56.784 0.084 56.808 ;
    END
  END o[436]
  PIN o[437]
    DIRECTION OUTPUT ;
    USE SIGNAL ;
    PORT
      LAYER M4 ;
        RECT  0 56.88 0.084 56.904 ;
    END
  END o[437]
  PIN o[438]
    DIRECTION OUTPUT ;
    USE SIGNAL ;
    PORT
      LAYER M4 ;
        RECT  0 56.976 0.084 57 ;
    END
  END o[438]
  PIN o[439]
    DIRECTION OUTPUT ;
    USE SIGNAL ;
    PORT
      LAYER M4 ;
        RECT  0 57.072 0.084 57.096 ;
    END
  END o[439]
  PIN o[43]
    DIRECTION OUTPUT ;
    USE SIGNAL ;
    PORT
      LAYER M4 ;
        RECT  0 30.576 0.084 30.6 ;
    END
  END o[43]
  PIN o[440]
    DIRECTION OUTPUT ;
    USE SIGNAL ;
    PORT
      LAYER M4 ;
        RECT  0 57.168 0.084 57.192 ;
    END
  END o[440]
  PIN o[441]
    DIRECTION OUTPUT ;
    USE SIGNAL ;
    PORT
      LAYER M4 ;
        RECT  0 57.264 0.084 57.288 ;
    END
  END o[441]
  PIN o[442]
    DIRECTION OUTPUT ;
    USE SIGNAL ;
    PORT
      LAYER M4 ;
        RECT  0 57.36 0.084 57.384 ;
    END
  END o[442]
  PIN o[443]
    DIRECTION OUTPUT ;
    USE SIGNAL ;
    PORT
      LAYER M4 ;
        RECT  0 57.456 0.084 57.48 ;
    END
  END o[443]
  PIN o[444]
    DIRECTION OUTPUT ;
    USE SIGNAL ;
    PORT
      LAYER M4 ;
        RECT  0 57.552 0.084 57.576 ;
    END
  END o[444]
  PIN o[445]
    DIRECTION OUTPUT ;
    USE SIGNAL ;
    PORT
      LAYER M4 ;
        RECT  0 57.648 0.084 57.672 ;
    END
  END o[445]
  PIN o[446]
    DIRECTION OUTPUT ;
    USE SIGNAL ;
    PORT
      LAYER M4 ;
        RECT  0 57.744 0.084 57.768 ;
    END
  END o[446]
  PIN o[447]
    DIRECTION OUTPUT ;
    USE SIGNAL ;
    PORT
      LAYER M4 ;
        RECT  0 57.84 0.084 57.864 ;
    END
  END o[447]
  PIN o[448]
    DIRECTION OUTPUT ;
    USE SIGNAL ;
    PORT
      LAYER M4 ;
        RECT  0 51.792 0.084 51.816 ;
    END
  END o[448]
  PIN o[449]
    DIRECTION OUTPUT ;
    USE SIGNAL ;
    PORT
      LAYER M4 ;
        RECT  0 51.888 0.084 51.912 ;
    END
  END o[449]
  PIN o[44]
    DIRECTION OUTPUT ;
    USE SIGNAL ;
    PORT
      LAYER M4 ;
        RECT  0 30.672 0.084 30.696 ;
    END
  END o[44]
  PIN o[450]
    DIRECTION OUTPUT ;
    USE SIGNAL ;
    PORT
      LAYER M4 ;
        RECT  0 51.984 0.084 52.008 ;
    END
  END o[450]
  PIN o[451]
    DIRECTION OUTPUT ;
    USE SIGNAL ;
    PORT
      LAYER M4 ;
        RECT  0 52.08 0.084 52.104 ;
    END
  END o[451]
  PIN o[452]
    DIRECTION OUTPUT ;
    USE SIGNAL ;
    PORT
      LAYER M4 ;
        RECT  0 52.176 0.084 52.2 ;
    END
  END o[452]
  PIN o[453]
    DIRECTION OUTPUT ;
    USE SIGNAL ;
    PORT
      LAYER M4 ;
        RECT  0 52.272 0.084 52.296 ;
    END
  END o[453]
  PIN o[454]
    DIRECTION OUTPUT ;
    USE SIGNAL ;
    PORT
      LAYER M4 ;
        RECT  0 52.368 0.084 52.392 ;
    END
  END o[454]
  PIN o[455]
    DIRECTION OUTPUT ;
    USE SIGNAL ;
    PORT
      LAYER M4 ;
        RECT  0 52.464 0.084 52.488 ;
    END
  END o[455]
  PIN o[456]
    DIRECTION OUTPUT ;
    USE SIGNAL ;
    PORT
      LAYER M4 ;
        RECT  0 52.56 0.084 52.584 ;
    END
  END o[456]
  PIN o[457]
    DIRECTION OUTPUT ;
    USE SIGNAL ;
    PORT
      LAYER M4 ;
        RECT  0 52.656 0.084 52.68 ;
    END
  END o[457]
  PIN o[458]
    DIRECTION OUTPUT ;
    USE SIGNAL ;
    PORT
      LAYER M4 ;
        RECT  0 52.752 0.084 52.776 ;
    END
  END o[458]
  PIN o[459]
    DIRECTION OUTPUT ;
    USE SIGNAL ;
    PORT
      LAYER M4 ;
        RECT  0 52.848 0.084 52.872 ;
    END
  END o[459]
  PIN o[45]
    DIRECTION OUTPUT ;
    USE SIGNAL ;
    PORT
      LAYER M4 ;
        RECT  0 30.768 0.084 30.792 ;
    END
  END o[45]
  PIN o[460]
    DIRECTION OUTPUT ;
    USE SIGNAL ;
    PORT
      LAYER M4 ;
        RECT  0 52.944 0.084 52.968 ;
    END
  END o[460]
  PIN o[461]
    DIRECTION OUTPUT ;
    USE SIGNAL ;
    PORT
      LAYER M4 ;
        RECT  0 53.04 0.084 53.064 ;
    END
  END o[461]
  PIN o[462]
    DIRECTION OUTPUT ;
    USE SIGNAL ;
    PORT
      LAYER M4 ;
        RECT  0 53.136 0.084 53.16 ;
    END
  END o[462]
  PIN o[463]
    DIRECTION OUTPUT ;
    USE SIGNAL ;
    PORT
      LAYER M4 ;
        RECT  0 53.232 0.084 53.256 ;
    END
  END o[463]
  PIN o[464]
    DIRECTION OUTPUT ;
    USE SIGNAL ;
    PORT
      LAYER M4 ;
        RECT  0 53.328 0.084 53.352 ;
    END
  END o[464]
  PIN o[465]
    DIRECTION OUTPUT ;
    USE SIGNAL ;
    PORT
      LAYER M4 ;
        RECT  0 53.424 0.084 53.448 ;
    END
  END o[465]
  PIN o[466]
    DIRECTION OUTPUT ;
    USE SIGNAL ;
    PORT
      LAYER M4 ;
        RECT  0 53.52 0.084 53.544 ;
    END
  END o[466]
  PIN o[467]
    DIRECTION OUTPUT ;
    USE SIGNAL ;
    PORT
      LAYER M4 ;
        RECT  0 53.616 0.084 53.64 ;
    END
  END o[467]
  PIN o[468]
    DIRECTION OUTPUT ;
    USE SIGNAL ;
    PORT
      LAYER M4 ;
        RECT  0 53.712 0.084 53.736 ;
    END
  END o[468]
  PIN o[469]
    DIRECTION OUTPUT ;
    USE SIGNAL ;
    PORT
      LAYER M4 ;
        RECT  0 53.808 0.084 53.832 ;
    END
  END o[469]
  PIN o[46]
    DIRECTION OUTPUT ;
    USE SIGNAL ;
    PORT
      LAYER M4 ;
        RECT  0 30.864 0.084 30.888 ;
    END
  END o[46]
  PIN o[470]
    DIRECTION OUTPUT ;
    USE SIGNAL ;
    PORT
      LAYER M4 ;
        RECT  0 53.904 0.084 53.928 ;
    END
  END o[470]
  PIN o[471]
    DIRECTION OUTPUT ;
    USE SIGNAL ;
    PORT
      LAYER M4 ;
        RECT  0 54 0.084 54.024 ;
    END
  END o[471]
  PIN o[472]
    DIRECTION OUTPUT ;
    USE SIGNAL ;
    PORT
      LAYER M4 ;
        RECT  0 54.096 0.084 54.12 ;
    END
  END o[472]
  PIN o[473]
    DIRECTION OUTPUT ;
    USE SIGNAL ;
    PORT
      LAYER M4 ;
        RECT  0 54.192 0.084 54.216 ;
    END
  END o[473]
  PIN o[474]
    DIRECTION OUTPUT ;
    USE SIGNAL ;
    PORT
      LAYER M4 ;
        RECT  0 54.288 0.084 54.312 ;
    END
  END o[474]
  PIN o[475]
    DIRECTION OUTPUT ;
    USE SIGNAL ;
    PORT
      LAYER M4 ;
        RECT  0 54.384 0.084 54.408 ;
    END
  END o[475]
  PIN o[476]
    DIRECTION OUTPUT ;
    USE SIGNAL ;
    PORT
      LAYER M4 ;
        RECT  0 54.48 0.084 54.504 ;
    END
  END o[476]
  PIN o[477]
    DIRECTION OUTPUT ;
    USE SIGNAL ;
    PORT
      LAYER M4 ;
        RECT  0 54.576 0.084 54.6 ;
    END
  END o[477]
  PIN o[478]
    DIRECTION OUTPUT ;
    USE SIGNAL ;
    PORT
      LAYER M4 ;
        RECT  0 54.672 0.084 54.696 ;
    END
  END o[478]
  PIN o[479]
    DIRECTION OUTPUT ;
    USE SIGNAL ;
    PORT
      LAYER M4 ;
        RECT  0 54.768 0.084 54.792 ;
    END
  END o[479]
  PIN o[47]
    DIRECTION OUTPUT ;
    USE SIGNAL ;
    PORT
      LAYER M4 ;
        RECT  0 30.96 0.084 30.984 ;
    END
  END o[47]
  PIN o[480]
    DIRECTION OUTPUT ;
    USE SIGNAL ;
    PORT
      LAYER M4 ;
        RECT  0 22.608 0.084 22.632 ;
    END
  END o[480]
  PIN o[481]
    DIRECTION OUTPUT ;
    USE SIGNAL ;
    PORT
      LAYER M4 ;
        RECT  0 22.704 0.084 22.728 ;
    END
  END o[481]
  PIN o[482]
    DIRECTION OUTPUT ;
    USE SIGNAL ;
    PORT
      LAYER M4 ;
        RECT  0 22.8 0.084 22.824 ;
    END
  END o[482]
  PIN o[483]
    DIRECTION OUTPUT ;
    USE SIGNAL ;
    PORT
      LAYER M4 ;
        RECT  0 22.896 0.084 22.92 ;
    END
  END o[483]
  PIN o[484]
    DIRECTION OUTPUT ;
    USE SIGNAL ;
    PORT
      LAYER M4 ;
        RECT  0 22.992 0.084 23.016 ;
    END
  END o[484]
  PIN o[485]
    DIRECTION OUTPUT ;
    USE SIGNAL ;
    PORT
      LAYER M4 ;
        RECT  0 23.088 0.084 23.112 ;
    END
  END o[485]
  PIN o[486]
    DIRECTION OUTPUT ;
    USE SIGNAL ;
    PORT
      LAYER M4 ;
        RECT  0 23.184 0.084 23.208 ;
    END
  END o[486]
  PIN o[487]
    DIRECTION OUTPUT ;
    USE SIGNAL ;
    PORT
      LAYER M4 ;
        RECT  0 23.28 0.084 23.304 ;
    END
  END o[487]
  PIN o[488]
    DIRECTION OUTPUT ;
    USE SIGNAL ;
    PORT
      LAYER M4 ;
        RECT  0 23.376 0.084 23.4 ;
    END
  END o[488]
  PIN o[489]
    DIRECTION OUTPUT ;
    USE SIGNAL ;
    PORT
      LAYER M4 ;
        RECT  0 23.472 0.084 23.496 ;
    END
  END o[489]
  PIN o[48]
    DIRECTION OUTPUT ;
    USE SIGNAL ;
    PORT
      LAYER M4 ;
        RECT  0 31.056 0.084 31.08 ;
    END
  END o[48]
  PIN o[490]
    DIRECTION OUTPUT ;
    USE SIGNAL ;
    PORT
      LAYER M4 ;
        RECT  0 23.568 0.084 23.592 ;
    END
  END o[490]
  PIN o[491]
    DIRECTION OUTPUT ;
    USE SIGNAL ;
    PORT
      LAYER M4 ;
        RECT  0 23.664 0.084 23.688 ;
    END
  END o[491]
  PIN o[492]
    DIRECTION OUTPUT ;
    USE SIGNAL ;
    PORT
      LAYER M4 ;
        RECT  0 23.76 0.084 23.784 ;
    END
  END o[492]
  PIN o[493]
    DIRECTION OUTPUT ;
    USE SIGNAL ;
    PORT
      LAYER M4 ;
        RECT  0 23.856 0.084 23.88 ;
    END
  END o[493]
  PIN o[494]
    DIRECTION OUTPUT ;
    USE SIGNAL ;
    PORT
      LAYER M4 ;
        RECT  0 23.952 0.084 23.976 ;
    END
  END o[494]
  PIN o[495]
    DIRECTION OUTPUT ;
    USE SIGNAL ;
    PORT
      LAYER M4 ;
        RECT  0 24.048 0.084 24.072 ;
    END
  END o[495]
  PIN o[496]
    DIRECTION OUTPUT ;
    USE SIGNAL ;
    PORT
      LAYER M4 ;
        RECT  0 24.144 0.084 24.168 ;
    END
  END o[496]
  PIN o[497]
    DIRECTION OUTPUT ;
    USE SIGNAL ;
    PORT
      LAYER M4 ;
        RECT  0 24.24 0.084 24.264 ;
    END
  END o[497]
  PIN o[498]
    DIRECTION OUTPUT ;
    USE SIGNAL ;
    PORT
      LAYER M4 ;
        RECT  0 24.336 0.084 24.36 ;
    END
  END o[498]
  PIN o[499]
    DIRECTION OUTPUT ;
    USE SIGNAL ;
    PORT
      LAYER M4 ;
        RECT  0 24.432 0.084 24.456 ;
    END
  END o[499]
  PIN o[49]
    DIRECTION OUTPUT ;
    USE SIGNAL ;
    PORT
      LAYER M4 ;
        RECT  0 31.152 0.084 31.176 ;
    END
  END o[49]
  PIN o[4]
    DIRECTION OUTPUT ;
    USE SIGNAL ;
    PORT
      LAYER M4 ;
        RECT  0 7.632 0.084 7.656 ;
    END
  END o[4]
  PIN o[500]
    DIRECTION OUTPUT ;
    USE SIGNAL ;
    PORT
      LAYER M4 ;
        RECT  0 24.528 0.084 24.552 ;
    END
  END o[500]
  PIN o[501]
    DIRECTION OUTPUT ;
    USE SIGNAL ;
    PORT
      LAYER M4 ;
        RECT  0 24.624 0.084 24.648 ;
    END
  END o[501]
  PIN o[502]
    DIRECTION OUTPUT ;
    USE SIGNAL ;
    PORT
      LAYER M4 ;
        RECT  0 24.72 0.084 24.744 ;
    END
  END o[502]
  PIN o[503]
    DIRECTION OUTPUT ;
    USE SIGNAL ;
    PORT
      LAYER M4 ;
        RECT  0 24.816 0.084 24.84 ;
    END
  END o[503]
  PIN o[504]
    DIRECTION OUTPUT ;
    USE SIGNAL ;
    PORT
      LAYER M4 ;
        RECT  0 24.912 0.084 24.936 ;
    END
  END o[504]
  PIN o[505]
    DIRECTION OUTPUT ;
    USE SIGNAL ;
    PORT
      LAYER M4 ;
        RECT  0 25.008 0.084 25.032 ;
    END
  END o[505]
  PIN o[506]
    DIRECTION OUTPUT ;
    USE SIGNAL ;
    PORT
      LAYER M4 ;
        RECT  0 25.104 0.084 25.128 ;
    END
  END o[506]
  PIN o[507]
    DIRECTION OUTPUT ;
    USE SIGNAL ;
    PORT
      LAYER M4 ;
        RECT  0 25.2 0.084 25.224 ;
    END
  END o[507]
  PIN o[508]
    DIRECTION OUTPUT ;
    USE SIGNAL ;
    PORT
      LAYER M4 ;
        RECT  0 25.296 0.084 25.32 ;
    END
  END o[508]
  PIN o[509]
    DIRECTION OUTPUT ;
    USE SIGNAL ;
    PORT
      LAYER M4 ;
        RECT  0 25.392 0.084 25.416 ;
    END
  END o[509]
  PIN o[50]
    DIRECTION OUTPUT ;
    USE SIGNAL ;
    PORT
      LAYER M4 ;
        RECT  0 31.248 0.084 31.272 ;
    END
  END o[50]
  PIN o[510]
    DIRECTION OUTPUT ;
    USE SIGNAL ;
    PORT
      LAYER M4 ;
        RECT  0 25.488 0.084 25.512 ;
    END
  END o[510]
  PIN o[511]
    DIRECTION OUTPUT ;
    USE SIGNAL ;
    PORT
      LAYER M4 ;
        RECT  0 25.584 0.084 25.608 ;
    END
  END o[511]
  PIN o[512]
    DIRECTION OUTPUT ;
    USE SIGNAL ;
    PORT
      LAYER M4 ;
        RECT  0 13.392 0.084 13.416 ;
    END
  END o[512]
  PIN o[513]
    DIRECTION OUTPUT ;
    USE SIGNAL ;
    PORT
      LAYER M4 ;
        RECT  0 13.488 0.084 13.512 ;
    END
  END o[513]
  PIN o[514]
    DIRECTION OUTPUT ;
    USE SIGNAL ;
    PORT
      LAYER M4 ;
        RECT  0 13.584 0.084 13.608 ;
    END
  END o[514]
  PIN o[515]
    DIRECTION OUTPUT ;
    USE SIGNAL ;
    PORT
      LAYER M4 ;
        RECT  0 13.68 0.084 13.704 ;
    END
  END o[515]
  PIN o[516]
    DIRECTION OUTPUT ;
    USE SIGNAL ;
    PORT
      LAYER M4 ;
        RECT  0 13.776 0.084 13.8 ;
    END
  END o[516]
  PIN o[517]
    DIRECTION OUTPUT ;
    USE SIGNAL ;
    PORT
      LAYER M4 ;
        RECT  0 13.872 0.084 13.896 ;
    END
  END o[517]
  PIN o[518]
    DIRECTION OUTPUT ;
    USE SIGNAL ;
    PORT
      LAYER M4 ;
        RECT  0 13.968 0.084 13.992 ;
    END
  END o[518]
  PIN o[519]
    DIRECTION OUTPUT ;
    USE SIGNAL ;
    PORT
      LAYER M4 ;
        RECT  0 14.064 0.084 14.088 ;
    END
  END o[519]
  PIN o[51]
    DIRECTION OUTPUT ;
    USE SIGNAL ;
    PORT
      LAYER M4 ;
        RECT  0 31.344 0.084 31.368 ;
    END
  END o[51]
  PIN o[520]
    DIRECTION OUTPUT ;
    USE SIGNAL ;
    PORT
      LAYER M4 ;
        RECT  0 14.16 0.084 14.184 ;
    END
  END o[520]
  PIN o[521]
    DIRECTION OUTPUT ;
    USE SIGNAL ;
    PORT
      LAYER M4 ;
        RECT  0 14.256 0.084 14.28 ;
    END
  END o[521]
  PIN o[522]
    DIRECTION OUTPUT ;
    USE SIGNAL ;
    PORT
      LAYER M4 ;
        RECT  0 14.352 0.084 14.376 ;
    END
  END o[522]
  PIN o[523]
    DIRECTION OUTPUT ;
    USE SIGNAL ;
    PORT
      LAYER M4 ;
        RECT  0 14.448 0.084 14.472 ;
    END
  END o[523]
  PIN o[524]
    DIRECTION OUTPUT ;
    USE SIGNAL ;
    PORT
      LAYER M4 ;
        RECT  0 14.544 0.084 14.568 ;
    END
  END o[524]
  PIN o[525]
    DIRECTION OUTPUT ;
    USE SIGNAL ;
    PORT
      LAYER M4 ;
        RECT  0 14.64 0.084 14.664 ;
    END
  END o[525]
  PIN o[526]
    DIRECTION OUTPUT ;
    USE SIGNAL ;
    PORT
      LAYER M4 ;
        RECT  0 14.736 0.084 14.76 ;
    END
  END o[526]
  PIN o[527]
    DIRECTION OUTPUT ;
    USE SIGNAL ;
    PORT
      LAYER M4 ;
        RECT  0 14.832 0.084 14.856 ;
    END
  END o[527]
  PIN o[528]
    DIRECTION OUTPUT ;
    USE SIGNAL ;
    PORT
      LAYER M4 ;
        RECT  0 14.928 0.084 14.952 ;
    END
  END o[528]
  PIN o[529]
    DIRECTION OUTPUT ;
    USE SIGNAL ;
    PORT
      LAYER M4 ;
        RECT  0 15.024 0.084 15.048 ;
    END
  END o[529]
  PIN o[52]
    DIRECTION OUTPUT ;
    USE SIGNAL ;
    PORT
      LAYER M4 ;
        RECT  0 31.44 0.084 31.464 ;
    END
  END o[52]
  PIN o[530]
    DIRECTION OUTPUT ;
    USE SIGNAL ;
    PORT
      LAYER M4 ;
        RECT  0 15.12 0.084 15.144 ;
    END
  END o[530]
  PIN o[531]
    DIRECTION OUTPUT ;
    USE SIGNAL ;
    PORT
      LAYER M4 ;
        RECT  0 15.216 0.084 15.24 ;
    END
  END o[531]
  PIN o[532]
    DIRECTION OUTPUT ;
    USE SIGNAL ;
    PORT
      LAYER M4 ;
        RECT  0 15.312 0.084 15.336 ;
    END
  END o[532]
  PIN o[533]
    DIRECTION OUTPUT ;
    USE SIGNAL ;
    PORT
      LAYER M4 ;
        RECT  0 15.408 0.084 15.432 ;
    END
  END o[533]
  PIN o[534]
    DIRECTION OUTPUT ;
    USE SIGNAL ;
    PORT
      LAYER M4 ;
        RECT  0 15.504 0.084 15.528 ;
    END
  END o[534]
  PIN o[535]
    DIRECTION OUTPUT ;
    USE SIGNAL ;
    PORT
      LAYER M4 ;
        RECT  0 15.6 0.084 15.624 ;
    END
  END o[535]
  PIN o[536]
    DIRECTION OUTPUT ;
    USE SIGNAL ;
    PORT
      LAYER M4 ;
        RECT  0 15.696 0.084 15.72 ;
    END
  END o[536]
  PIN o[537]
    DIRECTION OUTPUT ;
    USE SIGNAL ;
    PORT
      LAYER M4 ;
        RECT  0 15.792 0.084 15.816 ;
    END
  END o[537]
  PIN o[538]
    DIRECTION OUTPUT ;
    USE SIGNAL ;
    PORT
      LAYER M4 ;
        RECT  0 15.888 0.084 15.912 ;
    END
  END o[538]
  PIN o[539]
    DIRECTION OUTPUT ;
    USE SIGNAL ;
    PORT
      LAYER M4 ;
        RECT  0 15.984 0.084 16.008 ;
    END
  END o[539]
  PIN o[53]
    DIRECTION OUTPUT ;
    USE SIGNAL ;
    PORT
      LAYER M4 ;
        RECT  0 31.536 0.084 31.56 ;
    END
  END o[53]
  PIN o[540]
    DIRECTION OUTPUT ;
    USE SIGNAL ;
    PORT
      LAYER M4 ;
        RECT  0 16.08 0.084 16.104 ;
    END
  END o[540]
  PIN o[541]
    DIRECTION OUTPUT ;
    USE SIGNAL ;
    PORT
      LAYER M4 ;
        RECT  0 16.176 0.084 16.2 ;
    END
  END o[541]
  PIN o[542]
    DIRECTION OUTPUT ;
    USE SIGNAL ;
    PORT
      LAYER M4 ;
        RECT  0 16.272 0.084 16.296 ;
    END
  END o[542]
  PIN o[543]
    DIRECTION OUTPUT ;
    USE SIGNAL ;
    PORT
      LAYER M4 ;
        RECT  0 16.368 0.084 16.392 ;
    END
  END o[543]
  PIN o[544]
    DIRECTION OUTPUT ;
    USE SIGNAL ;
    PORT
      LAYER M4 ;
        RECT  0 10.32 0.084 10.344 ;
    END
  END o[544]
  PIN o[545]
    DIRECTION OUTPUT ;
    USE SIGNAL ;
    PORT
      LAYER M4 ;
        RECT  0 10.416 0.084 10.44 ;
    END
  END o[545]
  PIN o[546]
    DIRECTION OUTPUT ;
    USE SIGNAL ;
    PORT
      LAYER M4 ;
        RECT  0 10.512 0.084 10.536 ;
    END
  END o[546]
  PIN o[547]
    DIRECTION OUTPUT ;
    USE SIGNAL ;
    PORT
      LAYER M4 ;
        RECT  0 10.608 0.084 10.632 ;
    END
  END o[547]
  PIN o[548]
    DIRECTION OUTPUT ;
    USE SIGNAL ;
    PORT
      LAYER M4 ;
        RECT  0 10.704 0.084 10.728 ;
    END
  END o[548]
  PIN o[549]
    DIRECTION OUTPUT ;
    USE SIGNAL ;
    PORT
      LAYER M4 ;
        RECT  0 10.8 0.084 10.824 ;
    END
  END o[549]
  PIN o[54]
    DIRECTION OUTPUT ;
    USE SIGNAL ;
    PORT
      LAYER M4 ;
        RECT  0 31.632 0.084 31.656 ;
    END
  END o[54]
  PIN o[550]
    DIRECTION OUTPUT ;
    USE SIGNAL ;
    PORT
      LAYER M4 ;
        RECT  0 10.896 0.084 10.92 ;
    END
  END o[550]
  PIN o[551]
    DIRECTION OUTPUT ;
    USE SIGNAL ;
    PORT
      LAYER M4 ;
        RECT  0 10.992 0.084 11.016 ;
    END
  END o[551]
  PIN o[552]
    DIRECTION OUTPUT ;
    USE SIGNAL ;
    PORT
      LAYER M4 ;
        RECT  0 11.088 0.084 11.112 ;
    END
  END o[552]
  PIN o[553]
    DIRECTION OUTPUT ;
    USE SIGNAL ;
    PORT
      LAYER M4 ;
        RECT  0 11.184 0.084 11.208 ;
    END
  END o[553]
  PIN o[554]
    DIRECTION OUTPUT ;
    USE SIGNAL ;
    PORT
      LAYER M4 ;
        RECT  0 11.28 0.084 11.304 ;
    END
  END o[554]
  PIN o[555]
    DIRECTION OUTPUT ;
    USE SIGNAL ;
    PORT
      LAYER M4 ;
        RECT  0 11.376 0.084 11.4 ;
    END
  END o[555]
  PIN o[556]
    DIRECTION OUTPUT ;
    USE SIGNAL ;
    PORT
      LAYER M4 ;
        RECT  0 11.472 0.084 11.496 ;
    END
  END o[556]
  PIN o[557]
    DIRECTION OUTPUT ;
    USE SIGNAL ;
    PORT
      LAYER M4 ;
        RECT  0 11.568 0.084 11.592 ;
    END
  END o[557]
  PIN o[558]
    DIRECTION OUTPUT ;
    USE SIGNAL ;
    PORT
      LAYER M4 ;
        RECT  0 11.664 0.084 11.688 ;
    END
  END o[558]
  PIN o[559]
    DIRECTION OUTPUT ;
    USE SIGNAL ;
    PORT
      LAYER M4 ;
        RECT  0 11.76 0.084 11.784 ;
    END
  END o[559]
  PIN o[55]
    DIRECTION OUTPUT ;
    USE SIGNAL ;
    PORT
      LAYER M4 ;
        RECT  0 31.728 0.084 31.752 ;
    END
  END o[55]
  PIN o[560]
    DIRECTION OUTPUT ;
    USE SIGNAL ;
    PORT
      LAYER M4 ;
        RECT  0 11.856 0.084 11.88 ;
    END
  END o[560]
  PIN o[561]
    DIRECTION OUTPUT ;
    USE SIGNAL ;
    PORT
      LAYER M4 ;
        RECT  0 11.952 0.084 11.976 ;
    END
  END o[561]
  PIN o[562]
    DIRECTION OUTPUT ;
    USE SIGNAL ;
    PORT
      LAYER M4 ;
        RECT  0 12.048 0.084 12.072 ;
    END
  END o[562]
  PIN o[563]
    DIRECTION OUTPUT ;
    USE SIGNAL ;
    PORT
      LAYER M4 ;
        RECT  0 12.144 0.084 12.168 ;
    END
  END o[563]
  PIN o[564]
    DIRECTION OUTPUT ;
    USE SIGNAL ;
    PORT
      LAYER M4 ;
        RECT  0 12.24 0.084 12.264 ;
    END
  END o[564]
  PIN o[565]
    DIRECTION OUTPUT ;
    USE SIGNAL ;
    PORT
      LAYER M4 ;
        RECT  0 12.336 0.084 12.36 ;
    END
  END o[565]
  PIN o[566]
    DIRECTION OUTPUT ;
    USE SIGNAL ;
    PORT
      LAYER M4 ;
        RECT  0 12.432 0.084 12.456 ;
    END
  END o[566]
  PIN o[567]
    DIRECTION OUTPUT ;
    USE SIGNAL ;
    PORT
      LAYER M4 ;
        RECT  0 12.528 0.084 12.552 ;
    END
  END o[567]
  PIN o[568]
    DIRECTION OUTPUT ;
    USE SIGNAL ;
    PORT
      LAYER M4 ;
        RECT  0 12.624 0.084 12.648 ;
    END
  END o[568]
  PIN o[569]
    DIRECTION OUTPUT ;
    USE SIGNAL ;
    PORT
      LAYER M4 ;
        RECT  0 12.72 0.084 12.744 ;
    END
  END o[569]
  PIN o[56]
    DIRECTION OUTPUT ;
    USE SIGNAL ;
    PORT
      LAYER M4 ;
        RECT  0 31.824 0.084 31.848 ;
    END
  END o[56]
  PIN o[570]
    DIRECTION OUTPUT ;
    USE SIGNAL ;
    PORT
      LAYER M4 ;
        RECT  0 12.816 0.084 12.84 ;
    END
  END o[570]
  PIN o[571]
    DIRECTION OUTPUT ;
    USE SIGNAL ;
    PORT
      LAYER M4 ;
        RECT  0 12.912 0.084 12.936 ;
    END
  END o[571]
  PIN o[572]
    DIRECTION OUTPUT ;
    USE SIGNAL ;
    PORT
      LAYER M4 ;
        RECT  0 13.008 0.084 13.032 ;
    END
  END o[572]
  PIN o[573]
    DIRECTION OUTPUT ;
    USE SIGNAL ;
    PORT
      LAYER M4 ;
        RECT  0 13.104 0.084 13.128 ;
    END
  END o[573]
  PIN o[574]
    DIRECTION OUTPUT ;
    USE SIGNAL ;
    PORT
      LAYER M4 ;
        RECT  0 13.2 0.084 13.224 ;
    END
  END o[574]
  PIN o[575]
    DIRECTION OUTPUT ;
    USE SIGNAL ;
    PORT
      LAYER M4 ;
        RECT  0 13.296 0.084 13.32 ;
    END
  END o[575]
  PIN o[576]
    DIRECTION OUTPUT ;
    USE SIGNAL ;
    PORT
      LAYER M4 ;
        RECT  0 3.408 0.084 3.432 ;
    END
  END o[576]
  PIN o[577]
    DIRECTION OUTPUT ;
    USE SIGNAL ;
    PORT
      LAYER M4 ;
        RECT  0 3.504 0.084 3.528 ;
    END
  END o[577]
  PIN o[578]
    DIRECTION OUTPUT ;
    USE SIGNAL ;
    PORT
      LAYER M4 ;
        RECT  0 3.6 0.084 3.624 ;
    END
  END o[578]
  PIN o[579]
    DIRECTION OUTPUT ;
    USE SIGNAL ;
    PORT
      LAYER M4 ;
        RECT  0 3.696 0.084 3.72 ;
    END
  END o[579]
  PIN o[57]
    DIRECTION OUTPUT ;
    USE SIGNAL ;
    PORT
      LAYER M4 ;
        RECT  0 31.92 0.084 31.944 ;
    END
  END o[57]
  PIN o[580]
    DIRECTION OUTPUT ;
    USE SIGNAL ;
    PORT
      LAYER M4 ;
        RECT  0 3.792 0.084 3.816 ;
    END
  END o[580]
  PIN o[581]
    DIRECTION OUTPUT ;
    USE SIGNAL ;
    PORT
      LAYER M4 ;
        RECT  0 3.888 0.084 3.912 ;
    END
  END o[581]
  PIN o[582]
    DIRECTION OUTPUT ;
    USE SIGNAL ;
    PORT
      LAYER M4 ;
        RECT  0 3.984 0.084 4.008 ;
    END
  END o[582]
  PIN o[583]
    DIRECTION OUTPUT ;
    USE SIGNAL ;
    PORT
      LAYER M4 ;
        RECT  0 4.08 0.084 4.104 ;
    END
  END o[583]
  PIN o[584]
    DIRECTION OUTPUT ;
    USE SIGNAL ;
    PORT
      LAYER M4 ;
        RECT  0 4.176 0.084 4.2 ;
    END
  END o[584]
  PIN o[585]
    DIRECTION OUTPUT ;
    USE SIGNAL ;
    PORT
      LAYER M4 ;
        RECT  0 4.272 0.084 4.296 ;
    END
  END o[585]
  PIN o[586]
    DIRECTION OUTPUT ;
    USE SIGNAL ;
    PORT
      LAYER M4 ;
        RECT  0 4.368 0.084 4.392 ;
    END
  END o[586]
  PIN o[587]
    DIRECTION OUTPUT ;
    USE SIGNAL ;
    PORT
      LAYER M4 ;
        RECT  0 4.464 0.084 4.488 ;
    END
  END o[587]
  PIN o[588]
    DIRECTION OUTPUT ;
    USE SIGNAL ;
    PORT
      LAYER M4 ;
        RECT  0 4.56 0.084 4.584 ;
    END
  END o[588]
  PIN o[589]
    DIRECTION OUTPUT ;
    USE SIGNAL ;
    PORT
      LAYER M4 ;
        RECT  0 4.656 0.084 4.68 ;
    END
  END o[589]
  PIN o[58]
    DIRECTION OUTPUT ;
    USE SIGNAL ;
    PORT
      LAYER M4 ;
        RECT  0 32.016 0.084 32.04 ;
    END
  END o[58]
  PIN o[590]
    DIRECTION OUTPUT ;
    USE SIGNAL ;
    PORT
      LAYER M4 ;
        RECT  0 4.752 0.084 4.776 ;
    END
  END o[590]
  PIN o[591]
    DIRECTION OUTPUT ;
    USE SIGNAL ;
    PORT
      LAYER M4 ;
        RECT  0 4.848 0.084 4.872 ;
    END
  END o[591]
  PIN o[592]
    DIRECTION OUTPUT ;
    USE SIGNAL ;
    PORT
      LAYER M4 ;
        RECT  0 4.944 0.084 4.968 ;
    END
  END o[592]
  PIN o[593]
    DIRECTION OUTPUT ;
    USE SIGNAL ;
    PORT
      LAYER M4 ;
        RECT  0 5.04 0.084 5.064 ;
    END
  END o[593]
  PIN o[594]
    DIRECTION OUTPUT ;
    USE SIGNAL ;
    PORT
      LAYER M4 ;
        RECT  0 5.136 0.084 5.16 ;
    END
  END o[594]
  PIN o[595]
    DIRECTION OUTPUT ;
    USE SIGNAL ;
    PORT
      LAYER M4 ;
        RECT  0 5.232 0.084 5.256 ;
    END
  END o[595]
  PIN o[596]
    DIRECTION OUTPUT ;
    USE SIGNAL ;
    PORT
      LAYER M4 ;
        RECT  0 5.328 0.084 5.352 ;
    END
  END o[596]
  PIN o[597]
    DIRECTION OUTPUT ;
    USE SIGNAL ;
    PORT
      LAYER M4 ;
        RECT  0 5.424 0.084 5.448 ;
    END
  END o[597]
  PIN o[598]
    DIRECTION OUTPUT ;
    USE SIGNAL ;
    PORT
      LAYER M4 ;
        RECT  0 5.52 0.084 5.544 ;
    END
  END o[598]
  PIN o[599]
    DIRECTION OUTPUT ;
    USE SIGNAL ;
    PORT
      LAYER M4 ;
        RECT  0 5.616 0.084 5.64 ;
    END
  END o[599]
  PIN o[59]
    DIRECTION OUTPUT ;
    USE SIGNAL ;
    PORT
      LAYER M4 ;
        RECT  0 32.112 0.084 32.136 ;
    END
  END o[59]
  PIN o[5]
    DIRECTION OUTPUT ;
    USE SIGNAL ;
    PORT
      LAYER M4 ;
        RECT  0 7.728 0.084 7.752 ;
    END
  END o[5]
  PIN o[600]
    DIRECTION OUTPUT ;
    USE SIGNAL ;
    PORT
      LAYER M4 ;
        RECT  0 5.712 0.084 5.736 ;
    END
  END o[600]
  PIN o[601]
    DIRECTION OUTPUT ;
    USE SIGNAL ;
    PORT
      LAYER M4 ;
        RECT  0 5.808 0.084 5.832 ;
    END
  END o[601]
  PIN o[602]
    DIRECTION OUTPUT ;
    USE SIGNAL ;
    PORT
      LAYER M4 ;
        RECT  0 5.904 0.084 5.928 ;
    END
  END o[602]
  PIN o[603]
    DIRECTION OUTPUT ;
    USE SIGNAL ;
    PORT
      LAYER M4 ;
        RECT  0 6 0.084 6.024 ;
    END
  END o[603]
  PIN o[604]
    DIRECTION OUTPUT ;
    USE SIGNAL ;
    PORT
      LAYER M4 ;
        RECT  0 6.096 0.084 6.12 ;
    END
  END o[604]
  PIN o[605]
    DIRECTION OUTPUT ;
    USE SIGNAL ;
    PORT
      LAYER M4 ;
        RECT  0 6.192 0.084 6.216 ;
    END
  END o[605]
  PIN o[606]
    DIRECTION OUTPUT ;
    USE SIGNAL ;
    PORT
      LAYER M4 ;
        RECT  0 6.288 0.084 6.312 ;
    END
  END o[606]
  PIN o[607]
    DIRECTION OUTPUT ;
    USE SIGNAL ;
    PORT
      LAYER M4 ;
        RECT  0 6.384 0.084 6.408 ;
    END
  END o[607]
  PIN o[608]
    DIRECTION OUTPUT ;
    USE SIGNAL ;
    PORT
      LAYER M4 ;
        RECT  0 1.872 0.084 1.896 ;
    END
  END o[608]
  PIN o[609]
    DIRECTION OUTPUT ;
    USE SIGNAL ;
    PORT
      LAYER M4 ;
        RECT  0 1.968 0.084 1.992 ;
    END
  END o[609]
  PIN o[60]
    DIRECTION OUTPUT ;
    USE SIGNAL ;
    PORT
      LAYER M4 ;
        RECT  0 32.208 0.084 32.232 ;
    END
  END o[60]
  PIN o[610]
    DIRECTION OUTPUT ;
    USE SIGNAL ;
    PORT
      LAYER M4 ;
        RECT  0 2.064 0.084 2.088 ;
    END
  END o[610]
  PIN o[611]
    DIRECTION OUTPUT ;
    USE SIGNAL ;
    PORT
      LAYER M4 ;
        RECT  0 2.16 0.084 2.184 ;
    END
  END o[611]
  PIN o[612]
    DIRECTION OUTPUT ;
    USE SIGNAL ;
    PORT
      LAYER M4 ;
        RECT  0 2.256 0.084 2.28 ;
    END
  END o[612]
  PIN o[613]
    DIRECTION OUTPUT ;
    USE SIGNAL ;
    PORT
      LAYER M4 ;
        RECT  0 2.352 0.084 2.376 ;
    END
  END o[613]
  PIN o[614]
    DIRECTION OUTPUT ;
    USE SIGNAL ;
    PORT
      LAYER M4 ;
        RECT  0 2.448 0.084 2.472 ;
    END
  END o[614]
  PIN o[615]
    DIRECTION OUTPUT ;
    USE SIGNAL ;
    PORT
      LAYER M4 ;
        RECT  0 2.544 0.084 2.568 ;
    END
  END o[615]
  PIN o[616]
    DIRECTION OUTPUT ;
    USE SIGNAL ;
    PORT
      LAYER M4 ;
        RECT  0 2.64 0.084 2.664 ;
    END
  END o[616]
  PIN o[617]
    DIRECTION OUTPUT ;
    USE SIGNAL ;
    PORT
      LAYER M4 ;
        RECT  0 2.736 0.084 2.76 ;
    END
  END o[617]
  PIN o[618]
    DIRECTION OUTPUT ;
    USE SIGNAL ;
    PORT
      LAYER M4 ;
        RECT  0 2.832 0.084 2.856 ;
    END
  END o[618]
  PIN o[619]
    DIRECTION OUTPUT ;
    USE SIGNAL ;
    PORT
      LAYER M4 ;
        RECT  0 2.928 0.084 2.952 ;
    END
  END o[619]
  PIN o[61]
    DIRECTION OUTPUT ;
    USE SIGNAL ;
    PORT
      LAYER M4 ;
        RECT  0 32.304 0.084 32.328 ;
    END
  END o[61]
  PIN o[620]
    DIRECTION OUTPUT ;
    USE SIGNAL ;
    PORT
      LAYER M4 ;
        RECT  0 3.024 0.084 3.048 ;
    END
  END o[620]
  PIN o[621]
    DIRECTION OUTPUT ;
    USE SIGNAL ;
    PORT
      LAYER M4 ;
        RECT  0 3.12 0.084 3.144 ;
    END
  END o[621]
  PIN o[622]
    DIRECTION OUTPUT ;
    USE SIGNAL ;
    PORT
      LAYER M4 ;
        RECT  0 3.216 0.084 3.24 ;
    END
  END o[622]
  PIN o[623]
    DIRECTION OUTPUT ;
    USE SIGNAL ;
    PORT
      LAYER M4 ;
        RECT  0 3.312 0.084 3.336 ;
    END
  END o[623]
  PIN o[62]
    DIRECTION OUTPUT ;
    USE SIGNAL ;
    PORT
      LAYER M4 ;
        RECT  0 32.4 0.084 32.424 ;
    END
  END o[62]
  PIN o[63]
    DIRECTION OUTPUT ;
    USE SIGNAL ;
    PORT
      LAYER M4 ;
        RECT  0 32.496 0.084 32.52 ;
    END
  END o[63]
  PIN o[64]
    DIRECTION OUTPUT ;
    USE SIGNAL ;
    PORT
      LAYER M4 ;
        RECT  0 26.448 0.084 26.472 ;
    END
  END o[64]
  PIN o[65]
    DIRECTION OUTPUT ;
    USE SIGNAL ;
    PORT
      LAYER M4 ;
        RECT  0 26.544 0.084 26.568 ;
    END
  END o[65]
  PIN o[66]
    DIRECTION OUTPUT ;
    USE SIGNAL ;
    PORT
      LAYER M4 ;
        RECT  0 26.64 0.084 26.664 ;
    END
  END o[66]
  PIN o[67]
    DIRECTION OUTPUT ;
    USE SIGNAL ;
    PORT
      LAYER M4 ;
        RECT  0 26.736 0.084 26.76 ;
    END
  END o[67]
  PIN o[68]
    DIRECTION OUTPUT ;
    USE SIGNAL ;
    PORT
      LAYER M4 ;
        RECT  0 26.832 0.084 26.856 ;
    END
  END o[68]
  PIN o[69]
    DIRECTION OUTPUT ;
    USE SIGNAL ;
    PORT
      LAYER M4 ;
        RECT  0 26.928 0.084 26.952 ;
    END
  END o[69]
  PIN o[6]
    DIRECTION OUTPUT ;
    USE SIGNAL ;
    PORT
      LAYER M4 ;
        RECT  0 7.824 0.084 7.848 ;
    END
  END o[6]
  PIN o[70]
    DIRECTION OUTPUT ;
    USE SIGNAL ;
    PORT
      LAYER M4 ;
        RECT  0 27.024 0.084 27.048 ;
    END
  END o[70]
  PIN o[71]
    DIRECTION OUTPUT ;
    USE SIGNAL ;
    PORT
      LAYER M4 ;
        RECT  0 27.12 0.084 27.144 ;
    END
  END o[71]
  PIN o[72]
    DIRECTION OUTPUT ;
    USE SIGNAL ;
    PORT
      LAYER M4 ;
        RECT  0 27.216 0.084 27.24 ;
    END
  END o[72]
  PIN o[73]
    DIRECTION OUTPUT ;
    USE SIGNAL ;
    PORT
      LAYER M4 ;
        RECT  0 27.312 0.084 27.336 ;
    END
  END o[73]
  PIN o[74]
    DIRECTION OUTPUT ;
    USE SIGNAL ;
    PORT
      LAYER M4 ;
        RECT  0 27.408 0.084 27.432 ;
    END
  END o[74]
  PIN o[75]
    DIRECTION OUTPUT ;
    USE SIGNAL ;
    PORT
      LAYER M4 ;
        RECT  0 27.504 0.084 27.528 ;
    END
  END o[75]
  PIN o[76]
    DIRECTION OUTPUT ;
    USE SIGNAL ;
    PORT
      LAYER M4 ;
        RECT  0 27.6 0.084 27.624 ;
    END
  END o[76]
  PIN o[77]
    DIRECTION OUTPUT ;
    USE SIGNAL ;
    PORT
      LAYER M4 ;
        RECT  0 27.696 0.084 27.72 ;
    END
  END o[77]
  PIN o[78]
    DIRECTION OUTPUT ;
    USE SIGNAL ;
    PORT
      LAYER M4 ;
        RECT  0 27.792 0.084 27.816 ;
    END
  END o[78]
  PIN o[79]
    DIRECTION OUTPUT ;
    USE SIGNAL ;
    PORT
      LAYER M4 ;
        RECT  0 27.888 0.084 27.912 ;
    END
  END o[79]
  PIN o[7]
    DIRECTION OUTPUT ;
    USE SIGNAL ;
    PORT
      LAYER M4 ;
        RECT  0 7.92 0.084 7.944 ;
    END
  END o[7]
  PIN o[80]
    DIRECTION OUTPUT ;
    USE SIGNAL ;
    PORT
      LAYER M4 ;
        RECT  0 27.984 0.084 28.008 ;
    END
  END o[80]
  PIN o[81]
    DIRECTION OUTPUT ;
    USE SIGNAL ;
    PORT
      LAYER M4 ;
        RECT  0 28.08 0.084 28.104 ;
    END
  END o[81]
  PIN o[82]
    DIRECTION OUTPUT ;
    USE SIGNAL ;
    PORT
      LAYER M4 ;
        RECT  0 28.176 0.084 28.2 ;
    END
  END o[82]
  PIN o[83]
    DIRECTION OUTPUT ;
    USE SIGNAL ;
    PORT
      LAYER M4 ;
        RECT  0 28.272 0.084 28.296 ;
    END
  END o[83]
  PIN o[84]
    DIRECTION OUTPUT ;
    USE SIGNAL ;
    PORT
      LAYER M4 ;
        RECT  0 28.368 0.084 28.392 ;
    END
  END o[84]
  PIN o[85]
    DIRECTION OUTPUT ;
    USE SIGNAL ;
    PORT
      LAYER M4 ;
        RECT  0 28.464 0.084 28.488 ;
    END
  END o[85]
  PIN o[86]
    DIRECTION OUTPUT ;
    USE SIGNAL ;
    PORT
      LAYER M4 ;
        RECT  0 28.56 0.084 28.584 ;
    END
  END o[86]
  PIN o[87]
    DIRECTION OUTPUT ;
    USE SIGNAL ;
    PORT
      LAYER M4 ;
        RECT  0 28.656 0.084 28.68 ;
    END
  END o[87]
  PIN o[88]
    DIRECTION OUTPUT ;
    USE SIGNAL ;
    PORT
      LAYER M4 ;
        RECT  0 28.752 0.084 28.776 ;
    END
  END o[88]
  PIN o[89]
    DIRECTION OUTPUT ;
    USE SIGNAL ;
    PORT
      LAYER M4 ;
        RECT  0 28.848 0.084 28.872 ;
    END
  END o[89]
  PIN o[8]
    DIRECTION OUTPUT ;
    USE SIGNAL ;
    PORT
      LAYER M4 ;
        RECT  0 8.016 0.084 8.04 ;
    END
  END o[8]
  PIN o[90]
    DIRECTION OUTPUT ;
    USE SIGNAL ;
    PORT
      LAYER M4 ;
        RECT  0 28.944 0.084 28.968 ;
    END
  END o[90]
  PIN o[91]
    DIRECTION OUTPUT ;
    USE SIGNAL ;
    PORT
      LAYER M4 ;
        RECT  0 29.04 0.084 29.064 ;
    END
  END o[91]
  PIN o[92]
    DIRECTION OUTPUT ;
    USE SIGNAL ;
    PORT
      LAYER M4 ;
        RECT  0 29.136 0.084 29.16 ;
    END
  END o[92]
  PIN o[93]
    DIRECTION OUTPUT ;
    USE SIGNAL ;
    PORT
      LAYER M4 ;
        RECT  0 29.232 0.084 29.256 ;
    END
  END o[93]
  PIN o[94]
    DIRECTION OUTPUT ;
    USE SIGNAL ;
    PORT
      LAYER M4 ;
        RECT  0 29.328 0.084 29.352 ;
    END
  END o[94]
  PIN o[95]
    DIRECTION OUTPUT ;
    USE SIGNAL ;
    PORT
      LAYER M4 ;
        RECT  0 29.424 0.084 29.448 ;
    END
  END o[95]
  PIN o[96]
    DIRECTION OUTPUT ;
    USE SIGNAL ;
    PORT
      LAYER M4 ;
        RECT  0 35.664 0.084 35.688 ;
    END
  END o[96]
  PIN o[97]
    DIRECTION OUTPUT ;
    USE SIGNAL ;
    PORT
      LAYER M4 ;
        RECT  0 35.76 0.084 35.784 ;
    END
  END o[97]
  PIN o[98]
    DIRECTION OUTPUT ;
    USE SIGNAL ;
    PORT
      LAYER M4 ;
        RECT  0 35.856 0.084 35.88 ;
    END
  END o[98]
  PIN o[99]
    DIRECTION OUTPUT ;
    USE SIGNAL ;
    PORT
      LAYER M4 ;
        RECT  0 35.952 0.084 35.976 ;
    END
  END o[99]
  PIN o[9]
    DIRECTION OUTPUT ;
    USE SIGNAL ;
    PORT
      LAYER M4 ;
        RECT  0 8.112 0.084 8.136 ;
    END
  END o[9]
  PIN rs
    DIRECTION INPUT ;
    USE SIGNAL ;
    PORT
      LAYER M5 ;
        RECT  10.8 0 10.824 0.084 ;
    END
  END rs
  PIN VDD
    DIRECTION INOUT ;
    USE POWER ;
    PORT
      LAYER M5 ;
        RECT  18.792 2.151 18.912 62.649 ;
        RECT  16.092 2.151 16.212 62.649 ;
        RECT  13.392 2.151 13.512 62.649 ;
        RECT  10.692 2.151 10.812 62.649 ;
        RECT  7.992 2.151 8.112 62.649 ;
        RECT  5.292 2.151 5.412 62.649 ;
        RECT  2.592 2.151 2.712 62.649 ;
    END
  END VDD
  PIN VSS
    DIRECTION INOUT ;
    USE GROUND ;
    PORT
      LAYER M5 ;
        RECT  18.6 2.137 18.72 62.663 ;
        RECT  15.9 2.137 16.02 62.663 ;
        RECT  13.2 2.137 13.32 62.663 ;
        RECT  10.5 2.137 10.62 62.663 ;
        RECT  7.8 2.137 7.92 62.663 ;
        RECT  5.1 2.137 5.22 62.663 ;
        RECT  2.4 2.137 2.52 62.663 ;
    END
  END VSS
  OBS
    LAYER RVTN ;
     RECT  2.16 2.16 19.44 2.295 ;
     RECT  2.16 2.565 19.44 2.835 ;
     RECT  2.16 3.105 19.44 3.375 ;
     RECT  2.16 3.645 19.44 3.915 ;
     RECT  2.16 4.185 19.44 4.455 ;
     RECT  2.16 4.725 19.44 4.995 ;
     RECT  2.16 5.265 19.44 5.535 ;
     RECT  2.16 5.805 19.44 6.075 ;
     RECT  2.16 6.345 19.44 6.615 ;
     RECT  2.16 6.885 19.44 7.155 ;
     RECT  2.16 7.425 19.44 7.695 ;
     RECT  2.16 7.965 19.44 8.235 ;
     RECT  2.16 8.505 19.44 8.775 ;
     RECT  2.16 9.045 19.44 9.315 ;
     RECT  2.16 9.585 19.44 9.855 ;
     RECT  2.16 10.125 19.44 10.395 ;
     RECT  2.16 10.665 19.44 10.935 ;
     RECT  2.16 11.205 19.44 11.475 ;
     RECT  2.16 11.745 19.44 12.015 ;
     RECT  2.16 12.285 19.44 12.555 ;
     RECT  2.16 12.825 19.44 13.095 ;
     RECT  2.16 13.365 19.44 13.635 ;
     RECT  2.16 13.905 19.44 14.175 ;
     RECT  2.16 14.445 19.44 14.715 ;
     RECT  2.16 14.985 19.44 15.255 ;
     RECT  2.16 15.525 19.44 15.795 ;
     RECT  2.16 16.065 19.44 16.335 ;
     RECT  2.16 16.605 19.44 16.875 ;
     RECT  2.16 17.145 19.44 17.415 ;
     RECT  2.16 17.685 19.44 17.955 ;
     RECT  2.16 18.225 19.44 18.495 ;
     RECT  2.16 18.765 19.44 19.035 ;
     RECT  2.16 19.305 19.44 19.575 ;
     RECT  2.16 19.845 19.44 20.115 ;
     RECT  2.16 20.385 19.44 20.655 ;
     RECT  2.16 20.925 19.44 21.195 ;
     RECT  2.16 21.465 19.44 21.735 ;
     RECT  2.16 22.005 19.44 22.275 ;
     RECT  2.16 22.545 19.44 22.815 ;
     RECT  2.16 23.085 19.44 23.355 ;
     RECT  2.16 23.625 19.44 23.895 ;
     RECT  2.16 24.165 19.44 24.435 ;
     RECT  2.16 24.705 19.44 24.975 ;
     RECT  2.16 25.245 19.44 25.515 ;
     RECT  2.16 25.785 19.44 26.055 ;
     RECT  2.16 26.325 19.44 26.595 ;
     RECT  2.16 26.865 19.44 27.135 ;
     RECT  2.16 27.405 19.44 27.675 ;
     RECT  2.16 27.945 19.44 28.215 ;
     RECT  2.16 28.485 19.44 28.755 ;
     RECT  2.16 29.025 19.44 29.295 ;
     RECT  2.16 29.565 19.44 29.835 ;
     RECT  2.16 30.105 19.44 30.375 ;
     RECT  2.16 30.645 19.44 30.915 ;
     RECT  2.16 31.185 19.44 31.455 ;
     RECT  2.16 31.725 19.44 31.995 ;
     RECT  2.16 32.265 19.44 32.535 ;
     RECT  2.16 32.805 19.44 33.075 ;
     RECT  2.16 33.345 19.44 33.615 ;
     RECT  2.16 33.885 19.44 34.155 ;
     RECT  2.16 34.425 19.44 34.695 ;
     RECT  2.16 34.965 19.44 35.235 ;
     RECT  2.16 35.505 19.44 35.775 ;
     RECT  2.16 36.045 19.44 36.315 ;
     RECT  2.16 36.585 19.44 36.855 ;
     RECT  2.16 37.125 19.44 37.395 ;
     RECT  2.16 37.665 19.44 37.935 ;
     RECT  2.16 38.205 19.44 38.475 ;
     RECT  2.16 38.745 19.44 39.015 ;
     RECT  2.16 39.285 19.44 39.555 ;
     RECT  2.16 39.825 19.44 40.095 ;
     RECT  2.16 40.365 19.44 40.635 ;
     RECT  2.16 40.905 19.44 41.175 ;
     RECT  2.16 41.445 19.44 41.715 ;
     RECT  2.16 41.985 19.44 42.255 ;
     RECT  2.16 42.525 19.44 42.795 ;
     RECT  2.16 43.065 19.44 43.335 ;
     RECT  2.16 43.605 19.44 43.875 ;
     RECT  2.16 44.145 19.44 44.415 ;
     RECT  2.16 44.685 19.44 44.955 ;
     RECT  2.16 45.225 19.44 45.495 ;
     RECT  2.16 45.765 19.44 46.035 ;
     RECT  2.16 46.305 19.44 46.575 ;
     RECT  2.16 46.845 19.44 47.115 ;
     RECT  2.16 47.385 19.44 47.655 ;
     RECT  2.16 47.925 19.44 48.195 ;
     RECT  2.16 48.465 19.44 48.735 ;
     RECT  2.16 49.005 19.44 49.275 ;
     RECT  2.16 49.545 19.44 49.815 ;
     RECT  2.16 50.085 19.44 50.355 ;
     RECT  2.16 50.625 19.44 50.895 ;
     RECT  2.16 51.165 19.44 51.435 ;
     RECT  2.16 51.705 19.44 51.975 ;
     RECT  2.16 52.245 19.44 52.515 ;
     RECT  2.16 52.785 19.44 53.055 ;
     RECT  2.16 53.325 19.44 53.595 ;
     RECT  2.16 53.865 19.44 54.135 ;
     RECT  2.16 54.405 19.44 54.675 ;
     RECT  2.16 54.945 19.44 55.215 ;
     RECT  2.16 55.485 19.44 55.755 ;
     RECT  2.16 56.025 19.44 56.295 ;
     RECT  2.16 56.565 19.44 56.835 ;
     RECT  2.16 57.105 19.44 57.375 ;
     RECT  2.16 57.645 19.44 57.915 ;
     RECT  2.16 58.185 19.44 58.455 ;
     RECT  2.16 58.725 19.44 58.995 ;
     RECT  2.16 59.265 19.44 59.535 ;
     RECT  2.16 59.805 19.44 60.075 ;
     RECT  2.16 60.345 19.44 60.615 ;
     RECT  2.16 60.885 19.44 61.155 ;
     RECT  2.16 61.425 19.44 61.695 ;
     RECT  2.16 61.965 19.44 62.235 ;
     RECT  2.16 62.505 19.44 62.64 ;
    LAYER RVTP ;
     RECT  2.16 2.295 19.44 2.565 ;
     RECT  2.16 2.835 19.44 3.105 ;
     RECT  2.16 3.375 19.44 3.645 ;
     RECT  2.16 3.915 19.44 4.185 ;
     RECT  2.16 4.455 19.44 4.725 ;
     RECT  2.16 4.995 19.44 5.265 ;
     RECT  2.16 5.535 19.44 5.805 ;
     RECT  2.16 6.075 19.44 6.345 ;
     RECT  2.16 6.615 19.44 6.885 ;
     RECT  2.16 7.155 19.44 7.425 ;
     RECT  2.16 7.695 19.44 7.965 ;
     RECT  2.16 8.235 19.44 8.505 ;
     RECT  2.16 8.775 19.44 9.045 ;
     RECT  2.16 9.315 19.44 9.585 ;
     RECT  2.16 9.855 19.44 10.125 ;
     RECT  2.16 10.395 19.44 10.665 ;
     RECT  2.16 10.935 19.44 11.205 ;
     RECT  2.16 11.475 19.44 11.745 ;
     RECT  2.16 12.015 19.44 12.285 ;
     RECT  2.16 12.555 19.44 12.825 ;
     RECT  2.16 13.095 19.44 13.365 ;
     RECT  2.16 13.635 19.44 13.905 ;
     RECT  2.16 14.175 19.44 14.445 ;
     RECT  2.16 14.715 19.44 14.985 ;
     RECT  2.16 15.255 19.44 15.525 ;
     RECT  2.16 15.795 19.44 16.065 ;
     RECT  2.16 16.335 19.44 16.605 ;
     RECT  2.16 16.875 19.44 17.145 ;
     RECT  2.16 17.415 19.44 17.685 ;
     RECT  2.16 17.955 19.44 18.225 ;
     RECT  2.16 18.495 19.44 18.765 ;
     RECT  2.16 19.035 19.44 19.305 ;
     RECT  2.16 19.575 19.44 19.845 ;
     RECT  2.16 20.115 19.44 20.385 ;
     RECT  2.16 20.655 19.44 20.925 ;
     RECT  2.16 21.195 19.44 21.465 ;
     RECT  2.16 21.735 19.44 22.005 ;
     RECT  2.16 22.275 19.44 22.545 ;
     RECT  2.16 22.815 19.44 23.085 ;
     RECT  2.16 23.355 19.44 23.625 ;
     RECT  2.16 23.895 19.44 24.165 ;
     RECT  2.16 24.435 19.44 24.705 ;
     RECT  2.16 24.975 19.44 25.245 ;
     RECT  2.16 25.515 19.44 25.785 ;
     RECT  2.16 26.055 19.44 26.325 ;
     RECT  2.16 26.595 19.44 26.865 ;
     RECT  2.16 27.135 19.44 27.405 ;
     RECT  2.16 27.675 19.44 27.945 ;
     RECT  2.16 28.215 19.44 28.485 ;
     RECT  2.16 28.755 19.44 29.025 ;
     RECT  2.16 29.295 19.44 29.565 ;
     RECT  2.16 29.835 19.44 30.105 ;
     RECT  2.16 30.375 19.44 30.645 ;
     RECT  2.16 30.915 19.44 31.185 ;
     RECT  2.16 31.455 19.44 31.725 ;
     RECT  2.16 31.995 19.44 32.265 ;
     RECT  2.16 32.535 19.44 32.805 ;
     RECT  2.16 33.075 19.44 33.345 ;
     RECT  2.16 33.615 19.44 33.885 ;
     RECT  2.16 34.155 19.44 34.425 ;
     RECT  2.16 34.695 19.44 34.965 ;
     RECT  2.16 35.235 19.44 35.505 ;
     RECT  2.16 35.775 19.44 36.045 ;
     RECT  2.16 36.315 19.44 36.585 ;
     RECT  2.16 36.855 19.44 37.125 ;
     RECT  2.16 37.395 19.44 37.665 ;
     RECT  2.16 37.935 19.44 38.205 ;
     RECT  2.16 38.475 19.44 38.745 ;
     RECT  2.16 39.015 19.44 39.285 ;
     RECT  2.16 39.555 19.44 39.825 ;
     RECT  2.16 40.095 19.44 40.365 ;
     RECT  2.16 40.635 19.44 40.905 ;
     RECT  2.16 41.175 19.44 41.445 ;
     RECT  2.16 41.715 19.44 41.985 ;
     RECT  2.16 42.255 19.44 42.525 ;
     RECT  2.16 42.795 19.44 43.065 ;
     RECT  2.16 43.335 19.44 43.605 ;
     RECT  2.16 43.875 19.44 44.145 ;
     RECT  2.16 44.415 19.44 44.685 ;
     RECT  2.16 44.955 19.44 45.225 ;
     RECT  2.16 45.495 19.44 45.765 ;
     RECT  2.16 46.035 19.44 46.305 ;
     RECT  2.16 46.575 19.44 46.845 ;
     RECT  2.16 47.115 19.44 47.385 ;
     RECT  2.16 47.655 19.44 47.925 ;
     RECT  2.16 48.195 19.44 48.465 ;
     RECT  2.16 48.735 19.44 49.005 ;
     RECT  2.16 49.275 19.44 49.545 ;
     RECT  2.16 49.815 19.44 50.085 ;
     RECT  2.16 50.355 19.44 50.625 ;
     RECT  2.16 50.895 19.44 51.165 ;
     RECT  2.16 51.435 19.44 51.705 ;
     RECT  2.16 51.975 19.44 52.245 ;
     RECT  2.16 52.515 19.44 52.785 ;
     RECT  2.16 53.055 19.44 53.325 ;
     RECT  2.16 53.595 19.44 53.865 ;
     RECT  2.16 54.135 19.44 54.405 ;
     RECT  2.16 54.675 19.44 54.945 ;
     RECT  2.16 55.215 19.44 55.485 ;
     RECT  2.16 55.755 19.44 56.025 ;
     RECT  2.16 56.295 19.44 56.565 ;
     RECT  2.16 56.835 19.44 57.105 ;
     RECT  2.16 57.375 19.44 57.645 ;
     RECT  2.16 57.915 19.44 58.185 ;
     RECT  2.16 58.455 19.44 58.725 ;
     RECT  2.16 58.995 19.44 59.265 ;
     RECT  2.16 59.535 19.44 59.805 ;
     RECT  2.16 60.075 19.44 60.345 ;
     RECT  2.16 60.615 19.44 60.885 ;
     RECT  2.16 61.155 19.44 61.425 ;
     RECT  2.16 61.695 19.44 61.965 ;
     RECT  2.16 62.235 19.44 62.505 ;
    LAYER M1 ;
     RECT  2.16 2.151 19.44 62.649 ;
    LAYER M2 ;
     RECT  0.067 42.03 0.103 42.048 ;
     RECT  0.031 60.93 0.103 60.948 ;
     RECT  0.103 60.93 0.131 61.488 ;
     RECT  0.103 52.254 0.139 52.272 ;
     RECT  0.103 2.304 0.203 2.322 ;
     RECT  0.103 24.444 0.203 24.462 ;
     RECT  0.103 28.116 0.203 28.134 ;
     RECT  0.103 39.996 0.203 40.59 ;
     RECT  0.103 41.571 0.203 42.048 ;
     RECT  0.103 54.486 0.203 54.504 ;
     RECT  0.103 17.928 0.211 17.946 ;
     RECT  0.103 19.314 0.211 19.332 ;
     RECT  0.103 30.582 0.211 30.906 ;
     RECT  0.103 4.77 0.239 4.788 ;
     RECT  0.103 12.834 0.239 12.852 ;
     RECT  0.211 17.928 0.239 19.332 ;
     RECT  0.103 21.906 0.239 22.536 ;
     RECT  0.103 29.268 0.239 29.286 ;
     RECT  0.103 34.74 0.239 35.226 ;
     RECT  0.103 43.542 0.239 43.56 ;
     RECT  0.103 50.481 0.283 50.499 ;
     RECT  0.239 18.576 0.311 19.332 ;
     RECT  0.103 55.8 0.311 55.818 ;
     RECT  0.103 3.384 0.319 3.402 ;
     RECT  0.103 11.754 0.347 11.772 ;
     RECT  0.103 16.344 0.347 16.434 ;
     RECT  0.311 18.846 0.347 19.332 ;
     RECT  0.283 50.436 0.347 50.499 ;
     RECT  0.139 52.056 0.347 52.272 ;
     RECT  0.103 14.958 0.383 14.976 ;
     RECT  0.211 30.582 0.383 30.978 ;
     RECT  0.319 2.916 0.419 3.402 ;
     RECT  0.347 50.436 0.419 50.454 ;
     RECT  0.103 7.326 0.499 7.344 ;
     RECT  0.499 7.326 0.535 7.452 ;
     RECT  0.103 46.746 0.535 46.764 ;
     RECT  0.203 40.374 0.571 40.59 ;
     RECT  0.571 40.374 0.635 41.004 ;
     RECT  0.635 40.986 1.147 41.004 ;
     RECT  0.203 41.76 1.147 41.814 ;
     RECT  0.067 44.658 1.147 44.676 ;
     RECT  0.383 30.96 1.175 30.978 ;
     RECT  1.147 44.586 1.175 44.676 ;
     RECT  0.535 54.576 1.183 54.594 ;
     RECT  1.183 48.978 1.319 48.996 ;
     RECT  1.147 50.166 1.327 50.184 ;
     RECT  1.183 54.576 1.355 55.242 ;
     RECT  1.471 63.09 1.607 63.108 ;
     RECT  0.211 23.67 1.687 23.688 ;
     RECT  1.687 23.67 1.723 24.264 ;
     RECT  1.147 25.866 1.723 25.884 ;
     RECT  1.183 27.576 1.723 27.594 ;
     RECT  1.183 43.506 1.723 43.524 ;
     RECT  1.175 44.586 1.723 44.64 ;
     RECT  1.327 50.058 1.723 50.184 ;
     RECT  1.327 51.786 1.723 51.804 ;
     RECT  1.355 54.576 1.723 55.206 ;
     RECT  1.723 25.488 1.759 25.884 ;
     RECT  1.147 40.986 1.759 41.814 ;
     RECT  1.687 52.758 1.759 52.776 ;
     RECT  1.723 53.874 1.759 55.206 ;
     RECT  0.131 61.47 1.759 61.488 ;
     RECT  1.759 25.254 1.795 25.884 ;
     RECT  1.759 40.806 1.795 41.814 ;
     RECT  1.723 27.576 1.903 28.134 ;
     RECT  1.759 29.106 1.903 29.124 ;
     RECT  1.723 43.506 1.975 44.64 ;
     RECT  1.327 45.576 1.975 45.594 ;
     RECT  1.975 57.726 2.047 57.744 ;
     RECT  1.759 61.164 2.083 61.488 ;
     RECT  1.795 25.254 2.119 26.046 ;
     RECT  1.795 40.806 2.119 42.444 ;
     RECT  1.759 52.758 2.119 55.206 ;
     RECT  2.047 57.726 2.119 58.104 ;
     RECT  1.723 23.364 2.155 24.264 ;
     RECT  0.419 3.384 2.16 3.402 ;
     RECT  0.535 6.624 2.16 7.452 ;
     RECT  0.535 8.244 2.16 8.262 ;
     RECT  1.327 11.286 2.16 11.304 ;
     RECT  1.687 12.366 2.16 12.384 ;
     RECT  0.347 16.416 2.16 16.434 ;
     RECT  2.155 22.986 2.16 24.264 ;
     RECT  2.119 25.254 2.16 26.316 ;
     RECT  1.903 27.576 2.16 29.124 ;
     RECT  0.103 32.472 2.16 32.49 ;
     RECT  0.211 37.098 2.16 37.116 ;
     RECT  1.723 39.186 2.16 39.204 ;
     RECT  2.119 40.338 2.16 42.444 ;
     RECT  1.975 43.506 2.16 45.594 ;
     RECT  0.535 46.746 2.16 47.178 ;
     RECT  1.723 49.284 2.16 50.184 ;
     RECT  1.723 51.336 2.16 51.804 ;
     RECT  2.119 52.758 2.16 55.584 ;
     RECT  2.119 57.726 2.16 58.374 ;
     RECT  2.083 60.966 2.16 61.488 ;
     RECT  2.16 2.151 2.299 62.649 ;
     RECT  2.299 1.926 2.911 62.649 ;
     RECT  2.911 1.926 3.163 62.694 ;
     RECT  3.163 1.926 3.523 63.072 ;
     RECT  3.523 1.926 3.847 63.108 ;
     RECT  3.847 1.926 4.063 63.306 ;
     RECT  4.063 1.836 8.015 63.306 ;
     RECT  8.015 1.836 9.275 63.072 ;
     RECT  9.275 1.836 10.219 63.036 ;
     RECT  10.219 1.8 12.335 63.036 ;
     RECT  12.335 1.8 12.803 63 ;
     RECT  12.803 1.8 13.055 62.766 ;
     RECT  13.055 1.8 13.919 62.73 ;
     RECT  13.919 1.8 17.231 62.694 ;
     RECT  17.231 1.836 19.139 62.694 ;
     RECT  19.139 1.881 19.895 62.694 ;
     RECT  19.895 1.926 19.931 62.694 ;
     RECT  19.931 23.328 20.291 62.694 ;
     RECT  19.931 5.778 20.327 22.419 ;
     RECT  20.291 23.328 20.399 38.466 ;
     RECT  20.327 5.778 20.435 13.626 ;
     RECT  20.399 23.328 20.435 29.556 ;
     RECT  20.399 30.348 20.435 38.466 ;
     RECT  20.291 39.366 20.435 62.694 ;
     RECT  19.931 1.926 20.471 4.986 ;
     RECT  20.327 14.418 20.471 22.419 ;
     RECT  20.435 5.778 20.507 13.086 ;
     RECT  20.471 14.526 20.507 22.419 ;
     RECT  20.435 23.328 20.507 28.044 ;
     RECT  20.435 28.8 20.507 29.286 ;
     RECT  20.435 30.42 20.507 38.466 ;
     RECT  20.435 39.366 20.507 40.662 ;
     RECT  20.435 44.46 20.507 53.892 ;
     RECT  20.435 54.756 20.507 57.906 ;
     RECT  20.435 58.806 20.507 62.694 ;
     RECT  20.507 14.994 20.543 16.164 ;
     RECT  20.507 17.658 20.543 19.566 ;
     RECT  20.507 21.906 20.543 22.419 ;
     RECT  20.507 24.678 20.543 28.044 ;
     RECT  20.507 34.2 20.543 37.152 ;
     RECT  20.507 37.98 20.543 37.998 ;
     RECT  20.507 40.374 20.543 40.662 ;
     RECT  20.507 53.406 20.543 53.892 ;
     RECT  20.507 54.756 20.543 57.636 ;
     RECT  20.507 58.806 20.543 58.824 ;
     RECT  20.471 1.962 20.579 4.986 ;
     RECT  20.507 49.752 20.579 52.542 ;
     RECT  20.543 56.61 20.579 57.636 ;
     RECT  20.507 9.864 21.407 13.086 ;
     RECT  20.507 5.778 21.443 7.524 ;
     RECT  20.543 24.678 21.443 27.936 ;
     RECT  20.543 34.2 21.443 36.954 ;
     RECT  20.435 41.454 21.443 43.668 ;
     RECT  20.579 51.516 21.443 52.542 ;
     RECT  20.579 2.574 21.479 4.986 ;
     RECT  20.543 16.074 21.479 16.164 ;
     RECT  20.543 17.658 21.479 17.784 ;
     RECT  20.543 18.846 21.479 19.566 ;
     RECT  20.507 20.628 21.479 20.718 ;
     RECT  21.443 24.678 21.479 26.118 ;
     RECT  21.443 26.874 21.479 27.666 ;
     RECT  20.507 30.726 21.479 32.094 ;
     RECT  21.443 34.2 21.479 34.254 ;
     RECT  21.443 35.01 21.479 36.954 ;
     RECT  21.443 41.454 21.479 43.632 ;
     RECT  20.507 44.46 21.479 48.564 ;
     RECT  20.579 49.752 21.479 50.184 ;
     RECT  20.543 53.406 21.479 53.424 ;
     RECT  20.579 57.42 21.479 57.636 ;
     RECT  20.507 60.156 21.479 62.694 ;
     RECT  21.479 2.574 21.515 3.474 ;
     RECT  21.479 4.464 21.515 4.986 ;
     RECT  21.443 6.048 21.515 7.524 ;
     RECT  20.507 8.28 21.515 9.108 ;
     RECT  21.407 9.864 21.515 11.232 ;
     RECT  21.407 12.258 21.515 13.086 ;
     RECT  20.543 14.994 21.515 15.318 ;
     RECT  21.479 16.074 21.515 16.092 ;
     RECT  21.479 17.658 21.515 17.676 ;
     RECT  21.479 19.548 21.515 19.566 ;
     RECT  21.479 20.628 21.515 20.646 ;
     RECT  20.543 21.978 21.515 21.996 ;
     RECT  20.507 23.868 21.515 23.886 ;
     RECT  21.479 24.678 21.515 24.696 ;
     RECT  21.479 25.83 21.515 25.848 ;
     RECT  21.479 27.18 21.515 27.666 ;
     RECT  20.507 28.8 21.515 29.124 ;
     RECT  21.479 30.726 21.515 31.716 ;
     RECT  20.507 32.886 21.515 32.904 ;
     RECT  21.479 34.2 21.515 34.218 ;
     RECT  21.479 35.01 21.515 36.504 ;
     RECT  20.507 39.366 21.515 39.384 ;
     RECT  20.543 40.374 21.515 40.392 ;
     RECT  21.479 42.066 21.515 43.398 ;
     RECT  21.479 44.46 21.515 45.216 ;
     RECT  21.479 46.35 21.515 46.368 ;
     RECT  21.479 47.394 21.515 48.528 ;
     RECT  21.479 50.166 21.515 50.184 ;
     RECT  21.443 51.516 21.515 51.534 ;
     RECT  21.443 52.524 21.515 52.542 ;
     RECT  20.543 54.756 21.515 55.782 ;
     RECT  20.579 56.61 21.515 56.628 ;
     RECT  21.479 57.618 21.515 57.636 ;
     RECT  21.479 60.156 21.515 62.226 ;
    LAYER M3 ;
     RECT  20.484 0.811 20.502 0.907 ;
     RECT  18.396 1.099 18.414 1.195 ;
     RECT  19.908 0.907 20.502 1.387 ;
     RECT  19.872 1.387 20.502 1.579 ;
     RECT  17.64 1.483 17.658 1.675 ;
     RECT  18.396 1.195 18.594 1.675 ;
     RECT  17.64 1.675 18.594 1.795 ;
     RECT  10.224 1.795 10.242 1.831 ;
     RECT  17.208 1.795 18.594 1.831 ;
     RECT  19.836 1.579 20.502 1.831 ;
     RECT  14.904 1.831 14.922 1.876 ;
     RECT  17.208 1.831 20.502 1.876 ;
     RECT  2.376 1.867 2.394 1.921 ;
     RECT  4.068 1.831 4.086 1.957 ;
     RECT  9.144 1.921 9.162 1.957 ;
     RECT  16.992 1.876 20.502 1.957 ;
     RECT  2.304 1.921 2.394 1.963 ;
     RECT  5.076 1.921 5.094 1.993 ;
     RECT  7.02 1.876 7.038 1.993 ;
     RECT  2.304 1.963 2.574 2.011 ;
     RECT  3.744 1.957 4.086 2.011 ;
     RECT  6.732 1.993 7.038 2.029 ;
     RECT  11.088 1.723 11.106 2.065 ;
     RECT  16.128 1.957 16.146 2.101 ;
     RECT  16.992 1.957 20.574 2.101 ;
     RECT  6.732 2.029 7.542 2.143 ;
     RECT  9.936 1.831 10.242 2.143 ;
     RECT  11.088 2.065 11.718 2.143 ;
     RECT  16.128 2.101 20.574 2.143 ;
     RECT  15.915 2.143 20.574 2.189 ;
     RECT  2.304 2.011 4.086 2.227 ;
     RECT  5.076 1.993 5.562 2.227 ;
     RECT  6.732 2.143 7.905 2.263 ;
     RECT  0.324 2.155 0.342 2.284 ;
     RECT  8.82 1.957 9.162 2.299 ;
     RECT  6.444 2.263 7.905 2.335 ;
     RECT  8.676 2.299 9.162 2.335 ;
     RECT  9.936 2.143 11.718 2.335 ;
     RECT  21.492 0.715 21.51 2.347 ;
     RECT  14.868 1.876 14.922 2.371 ;
     RECT  2.304 2.227 5.562 2.395 ;
     RECT  6.444 2.335 11.718 2.395 ;
     RECT  13.215 2.143 13.305 2.413 ;
     RECT  13.215 2.413 13.497 2.461 ;
     RECT  14.508 2.371 15.102 2.461 ;
     RECT  0.108 2.284 0.342 2.477 ;
     RECT  0.18 2.477 0.342 2.525 ;
     RECT  2.304 2.395 11.718 2.533 ;
     RECT  15.915 2.189 20.538 2.669 ;
     RECT  1.26 2.587 1.278 2.765 ;
     RECT  0.324 2.525 0.342 2.875 ;
     RECT  2.304 2.533 11.79 2.875 ;
     RECT  0.324 2.875 0.414 2.939 ;
     RECT  15.915 2.669 20.502 2.939 ;
     RECT  13.215 2.461 15.102 3.073 ;
     RECT  15.915 2.939 19.89 3.073 ;
     RECT  21.456 2.347 21.51 3.307 ;
     RECT  0.324 2.939 0.342 3.341 ;
     RECT  1.152 3.115 1.17 3.389 ;
     RECT  21.42 3.307 21.51 3.403 ;
     RECT  21.384 3.403 21.51 3.595 ;
     RECT  13.215 3.073 19.89 3.685 ;
     RECT  0.108 3.379 0.162 3.725 ;
     RECT  12.996 3.685 19.89 3.787 ;
     RECT  12.996 3.787 19.926 3.883 ;
     RECT  2.304 2.875 12.006 4.153 ;
     RECT  2.304 4.153 12.258 4.189 ;
     RECT  12.996 3.883 20.43 4.189 ;
     RECT  21.348 3.595 21.51 4.253 ;
     RECT  2.304 4.189 20.43 4.267 ;
     RECT  21.384 4.253 21.51 4.289 ;
     RECT  0.144 3.725 0.162 4.363 ;
     RECT  2.268 4.267 20.43 4.363 ;
     RECT  0.144 4.363 0.342 4.747 ;
     RECT  0.144 4.747 0.414 4.765 ;
     RECT  2.268 4.363 20.538 4.793 ;
     RECT  2.268 4.793 20.502 4.973 ;
     RECT  0.108 4.765 0.414 5.021 ;
     RECT  0.108 5.021 0.378 5.069 ;
     RECT  21.492 4.289 21.51 5.131 ;
     RECT  2.268 4.973 19.926 5.224 ;
     RECT  2.196 5.224 19.926 5.261 ;
     RECT  0.252 5.069 0.378 5.803 ;
     RECT  2.304 5.261 19.926 5.995 ;
     RECT  0.144 5.803 0.378 6.077 ;
     RECT  0.252 6.077 0.378 6.125 ;
     RECT  0.36 6.125 0.378 6.221 ;
     RECT  2.304 5.995 20.43 6.377 ;
     RECT  21.42 5.131 21.51 6.379 ;
     RECT  20.448 6.571 20.502 6.961 ;
     RECT  20.448 6.961 20.538 7.181 ;
     RECT  21.384 6.379 21.51 7.187 ;
     RECT  20.448 7.181 20.502 7.243 ;
     RECT  0.54 6.619 0.558 7.321 ;
     RECT  21.42 7.187 21.51 7.421 ;
     RECT  0.108 7.321 0.558 7.469 ;
     RECT  2.304 6.377 19.422 7.531 ;
     RECT  20.196 7.243 20.502 7.531 ;
     RECT  2.304 7.531 20.502 7.691 ;
     RECT  0.144 7.469 0.558 7.949 ;
     RECT  2.304 7.691 20.43 8.587 ;
     RECT  0.504 7.949 0.558 8.621 ;
     RECT  21.492 7.421 21.51 8.875 ;
     RECT  21.456 8.875 21.51 9.077 ;
     RECT  0.144 8.683 0.162 9.451 ;
     RECT  0.144 9.451 0.342 9.965 ;
     RECT  1.152 9.883 1.17 10.061 ;
     RECT  1.332 10.123 1.35 10.219 ;
     RECT  2.304 8.587 20.502 10.219 ;
     RECT  21.492 9.077 21.51 10.603 ;
     RECT  21.456 10.603 21.51 10.795 ;
     RECT  1.332 10.219 20.502 10.939 ;
     RECT  21.42 10.795 21.51 10.987 ;
     RECT  0.144 9.965 0.162 11.227 ;
     RECT  21.384 10.987 21.51 11.371 ;
     RECT  0.144 11.227 0.234 11.563 ;
     RECT  0.144 11.563 0.342 11.659 ;
     RECT  1.152 10.939 20.502 11.659 ;
     RECT  0.108 11.659 0.342 11.777 ;
     RECT  0.144 11.777 0.342 11.789 ;
     RECT  21.348 11.371 21.51 11.849 ;
     RECT  0.18 11.789 0.342 12.139 ;
     RECT  0.18 12.139 0.378 12.269 ;
     RECT  1.152 11.659 20.538 12.389 ;
     RECT  2.34 12.389 20.538 12.461 ;
     RECT  2.34 12.461 19.17 12.479 ;
     RECT  0.18 12.269 0.342 12.811 ;
     RECT  0.108 12.811 0.342 12.845 ;
     RECT  1.152 12.389 1.278 12.845 ;
     RECT  0.108 12.845 0.234 12.857 ;
     RECT  0.144 12.857 0.234 12.893 ;
     RECT  19.908 12.461 20.538 12.941 ;
     RECT  21.492 11.849 21.51 13.133 ;
     RECT  2.34 12.479 19.134 13.135 ;
     RECT  19.908 12.941 20.43 13.291 ;
     RECT  2.304 13.135 19.134 13.387 ;
     RECT  19.872 13.291 20.43 13.387 ;
     RECT  2.304 13.387 20.43 14.059 ;
     RECT  2.268 14.059 20.43 14.155 ;
     RECT  2.268 14.155 20.502 14.279 ;
     RECT  2.304 14.279 20.502 14.549 ;
     RECT  0.144 12.893 0.162 14.827 ;
     RECT  0.144 14.827 0.342 14.923 ;
     RECT  0.108 14.923 0.342 14.953 ;
     RECT  0.108 14.953 0.378 14.981 ;
     RECT  0.144 14.981 0.378 15.053 ;
     RECT  0.144 15.053 0.234 15.293 ;
     RECT  2.304 14.549 20.43 15.307 ;
     RECT  2.304 15.307 20.538 15.592 ;
     RECT  2.268 15.592 20.538 15.593 ;
     RECT  2.268 15.593 20.502 15.629 ;
     RECT  2.304 15.629 20.502 15.791 ;
     RECT  2.304 15.791 19.098 15.899 ;
     RECT  21.492 14.635 21.51 15.979 ;
     RECT  1.26 15.883 1.278 16.027 ;
     RECT  21.456 15.979 21.51 16.097 ;
     RECT  21.456 16.097 21.474 16.169 ;
     RECT  0.144 15.293 0.162 16.171 ;
     RECT  0.144 16.171 0.342 16.267 ;
     RECT  1.152 16.027 1.278 16.301 ;
     RECT  19.872 15.791 20.502 16.555 ;
     RECT  0.108 16.267 0.342 16.685 ;
     RECT  1.152 16.301 1.242 16.973 ;
     RECT  19.836 16.555 20.502 16.979 ;
     RECT  1.152 16.973 1.17 17.117 ;
     RECT  2.304 15.899 19.062 17.221 ;
     RECT  0.324 16.685 0.342 17.227 ;
     RECT  0.324 17.227 0.45 17.405 ;
     RECT  0.324 17.405 0.378 17.453 ;
     RECT  0.324 17.453 0.342 17.467 ;
     RECT  20.196 16.979 20.502 17.483 ;
     RECT  21.492 17.419 21.51 17.611 ;
     RECT  21.456 17.611 21.51 17.681 ;
     RECT  2.304 17.221 19.422 17.707 ;
     RECT  20.196 17.483 20.43 17.707 ;
     RECT  21.456 17.681 21.474 17.789 ;
     RECT  0.144 17.467 0.342 17.899 ;
     RECT  0.108 17.899 0.342 17.951 ;
     RECT  2.304 17.707 20.43 17.959 ;
     RECT  2.196 17.959 20.43 18.221 ;
     RECT  0.144 17.951 0.342 18.283 ;
     RECT  2.304 18.221 20.43 18.301 ;
     RECT  2.304 18.301 20.538 18.413 ;
     RECT  2.304 18.413 20.502 18.419 ;
     RECT  0.144 18.283 0.45 18.461 ;
     RECT  0.144 18.461 0.378 18.509 ;
     RECT  21.492 18.667 21.51 18.763 ;
     RECT  21.456 18.763 21.51 18.869 ;
     RECT  2.34 18.419 20.502 19.031 ;
     RECT  19.8 19.031 20.502 19.103 ;
     RECT  0.144 18.509 0.342 19.243 ;
     RECT  19.8 19.103 20.466 19.301 ;
     RECT  0.108 19.243 0.342 19.337 ;
     RECT  0.144 19.337 0.342 19.373 ;
     RECT  21.492 18.869 21.51 19.571 ;
     RECT  2.34 19.031 19.062 19.723 ;
     RECT  20.196 19.301 20.466 19.885 ;
     RECT  2.304 19.723 19.062 19.915 ;
     RECT  2.268 19.915 19.062 20.011 ;
     RECT  2.232 20.011 19.062 20.107 ;
     RECT  20.196 19.885 20.502 20.107 ;
     RECT  2.232 20.107 20.502 20.237 ;
     RECT  21.492 20.491 21.51 20.587 ;
     RECT  0.144 19.373 0.162 20.635 ;
     RECT  21.456 20.587 21.51 20.651 ;
     RECT  19.908 20.237 20.502 20.659 ;
     RECT  19.908 20.659 20.538 20.717 ;
     RECT  21.456 20.651 21.474 20.723 ;
     RECT  0.144 20.635 0.234 20.909 ;
     RECT  2.232 20.237 19.062 20.971 ;
     RECT  19.908 20.717 20.502 20.971 ;
     RECT  0.144 20.909 0.162 21.643 ;
     RECT  2.232 20.971 20.502 21.787 ;
     RECT  0.144 21.643 0.342 21.901 ;
     RECT  2.196 21.787 20.502 21.901 ;
     RECT  21.492 21.835 21.51 22.001 ;
     RECT  2.196 21.901 20.538 22.027 ;
     RECT  2.16 22.027 20.538 22.123 ;
     RECT  1.692 22.123 20.538 22.459 ;
     RECT  0.108 21.901 0.342 22.541 ;
     RECT  1.152 22.459 20.538 22.925 ;
     RECT  1.152 22.925 20.502 23.351 ;
     RECT  0.144 22.541 0.234 23.357 ;
     RECT  0.216 23.357 0.234 23.467 ;
     RECT  1.152 23.351 20.25 23.501 ;
     RECT  0.216 23.467 0.342 24.139 ;
     RECT  19.8 23.501 20.25 24.139 ;
     RECT  21.492 23.563 21.51 24.427 ;
     RECT  0.144 24.139 0.342 24.439 ;
     RECT  0.108 24.439 0.342 24.461 ;
     RECT  1.152 23.501 19.062 24.523 ;
     RECT  19.8 24.139 20.502 24.523 ;
     RECT  0.108 24.461 0.198 24.653 ;
     RECT  0.144 24.653 0.198 24.701 ;
     RECT  1.152 24.523 20.502 24.737 ;
     RECT  19.8 24.737 20.502 24.773 ;
     RECT  21.456 24.427 21.51 25.276 ;
     RECT  19.908 24.773 20.502 25.483 ;
     RECT  0.144 24.701 0.162 25.565 ;
     RECT  19.908 25.483 20.538 25.889 ;
     RECT  1.152 24.737 19.062 26.051 ;
     RECT  15.915 26.051 19.062 26.059 ;
     RECT  19.908 25.889 20.502 26.059 ;
     RECT  21.42 25.276 21.51 26.539 ;
     RECT  15.915 26.059 20.502 26.591 ;
     RECT  21.384 26.539 21.51 26.635 ;
     RECT  20.484 26.591 20.502 26.731 ;
     RECT  21.312 26.635 21.51 26.731 ;
     RECT  20.484 26.731 21.51 26.789 ;
     RECT  21.348 26.789 21.51 26.861 ;
     RECT  0.144 26.587 0.162 26.875 ;
     RECT  15.915 26.591 19.422 26.957 ;
     RECT  21.384 26.861 21.51 27.131 ;
     RECT  1.152 26.051 15.174 27.341 ;
     RECT  15.915 26.957 19.17 27.389 ;
     RECT  20.484 26.789 20.538 27.403 ;
     RECT  0.144 26.875 0.234 27.595 ;
     RECT  21.42 27.131 21.51 27.671 ;
     RECT  19.908 27.403 20.538 27.691 ;
     RECT  0.144 27.595 0.342 27.725 ;
     RECT  21.42 27.671 21.438 27.941 ;
     RECT  0.144 27.725 0.198 28.108 ;
     RECT  15.915 27.389 19.098 28.171 ;
     RECT  19.872 27.691 20.538 28.171 ;
     RECT  0.108 28.108 0.198 28.205 ;
     RECT  1.188 27.341 15.174 28.267 ;
     RECT  15.915 28.171 20.538 28.397 ;
     RECT  0.144 28.205 0.198 28.843 ;
     RECT  1.152 28.267 15.174 28.973 ;
     RECT  15.915 28.397 20.502 29.093 ;
     RECT  1.764 28.973 15.174 29.129 ;
     RECT  21.492 28.555 21.51 29.129 ;
     RECT  0.144 28.843 0.234 29.131 ;
     RECT  0.144 29.131 0.342 29.227 ;
     RECT  0.108 29.227 0.342 29.291 ;
     RECT  0.144 29.291 0.342 29.597 ;
     RECT  19.836 29.093 20.502 30.137 ;
     RECT  21.492 30.091 21.51 30.379 ;
     RECT  2.304 29.129 15.174 30.451 ;
     RECT  15.915 29.093 19.026 30.451 ;
     RECT  0.18 29.597 0.342 30.568 ;
     RECT  2.304 30.451 19.062 30.569 ;
     RECT  21.456 30.379 21.51 30.571 ;
     RECT  0.108 30.568 0.342 30.577 ;
     RECT  21.42 30.571 21.51 30.667 ;
     RECT  2.304 30.569 19.026 30.713 ;
     RECT  2.304 30.713 15.174 30.749 ;
     RECT  21.384 30.667 21.51 30.763 ;
     RECT  0.108 30.577 0.378 30.911 ;
     RECT  20.196 30.137 20.502 30.955 ;
     RECT  1.152 30.763 1.17 30.983 ;
     RECT  19.908 30.955 20.502 31.051 ;
     RECT  21.348 30.763 21.51 31.081 ;
     RECT  0.18 30.911 0.378 31.133 ;
     RECT  0.216 31.133 0.378 31.181 ;
     RECT  2.304 30.749 12.474 31.289 ;
     RECT  21.312 31.081 21.51 31.289 ;
     RECT  15.915 30.713 19.026 31.435 ;
     RECT  19.872 31.051 20.502 31.435 ;
     RECT  0.216 31.181 0.342 31.469 ;
     RECT  21.456 31.289 21.51 31.721 ;
     RECT  0.216 31.469 0.27 31.853 ;
     RECT  15.915 31.435 20.502 31.963 ;
     RECT  15.915 31.963 20.538 32.045 ;
     RECT  21.456 31.721 21.474 32.099 ;
     RECT  15.915 32.045 20.502 32.237 ;
     RECT  1.26 32.011 1.278 32.299 ;
     RECT  2.304 31.289 12.366 32.341 ;
     RECT  13.215 30.749 15.174 32.341 ;
     RECT  15.915 32.237 19.026 32.341 ;
     RECT  19.836 32.237 20.502 32.369 ;
     RECT  0.144 31.963 0.162 32.429 ;
     RECT  2.304 32.341 19.026 32.573 ;
     RECT  1.152 32.299 1.278 32.861 ;
     RECT  1.26 32.861 1.278 32.909 ;
     RECT  21.492 32.587 21.51 32.909 ;
     RECT  13.215 32.573 19.026 32.999 ;
     RECT  0.108 32.467 0.126 33.005 ;
     RECT  19.836 32.369 20.43 33.259 ;
     RECT  15.915 32.999 19.026 33.421 ;
     RECT  19.836 33.259 20.502 33.421 ;
     RECT  15.915 33.421 20.502 33.485 ;
     RECT  2.304 32.573 12.366 33.499 ;
     RECT  2.268 33.499 12.366 33.889 ;
     RECT  13.215 32.999 15.174 33.889 ;
     RECT  2.268 33.889 15.174 33.979 ;
     RECT  19.872 33.485 20.502 33.989 ;
     RECT  0.144 33.307 0.234 34.027 ;
     RECT  21.492 33.739 21.51 34.027 ;
     RECT  2.232 33.979 15.174 34.187 ;
     RECT  2.232 34.187 12.366 34.259 ;
     RECT  15.915 33.485 19.134 34.315 ;
     RECT  19.872 33.989 20.43 34.315 ;
     RECT  2.268 34.259 12.366 34.349 ;
     RECT  0.144 34.027 0.342 34.699 ;
     RECT  21.456 34.027 21.51 34.699 ;
     RECT  15.915 34.315 20.43 34.891 ;
     RECT  21.42 34.699 21.51 34.961 ;
     RECT  15.915 34.891 20.502 35.069 ;
     RECT  0.108 34.699 0.342 35.231 ;
     RECT  21.456 34.961 21.51 35.303 ;
     RECT  0.144 35.231 0.342 35.419 ;
     RECT  0.144 35.419 0.378 35.467 ;
     RECT  1.152 34.507 1.17 35.467 ;
     RECT  0.144 35.467 1.17 35.563 ;
     RECT  0.144 35.563 1.386 35.741 ;
     RECT  0.216 35.741 1.386 35.789 ;
     RECT  0.216 35.789 0.378 35.885 ;
     RECT  1.152 35.789 1.386 35.885 ;
     RECT  15.915 35.069 20.214 36.139 ;
     RECT  1.296 35.885 1.386 36.269 ;
     RECT  15.915 36.139 20.538 36.311 ;
     RECT  1.368 36.269 1.386 36.317 ;
     RECT  21.492 35.303 21.51 36.508 ;
     RECT  21.456 36.508 21.51 36.509 ;
     RECT  0.216 35.885 0.342 36.715 ;
     RECT  13.215 34.187 15.174 36.763 ;
     RECT  0.216 36.715 0.378 36.811 ;
     RECT  0.18 36.811 0.378 36.845 ;
     RECT  21.456 36.509 21.474 36.959 ;
     RECT  15.915 36.311 18.897 37.093 ;
     RECT  1.152 37.051 1.17 37.229 ;
     RECT  13.104 36.763 15.174 37.229 ;
     RECT  0.18 36.845 0.342 37.435 ;
     RECT  2.304 34.349 12.366 37.531 ;
     RECT  15.915 37.093 19.026 37.561 ;
     RECT  15.915 37.561 19.098 37.867 ;
     RECT  19.836 36.311 20.538 37.867 ;
     RECT  0.144 37.435 0.342 37.949 ;
     RECT  15.915 37.867 20.538 38.003 ;
     RECT  15.915 38.003 20.502 38.471 ;
     RECT  0.324 37.949 0.342 38.827 ;
     RECT  0.144 38.827 0.342 39.115 ;
     RECT  1.728 37.531 12.366 39.245 ;
     RECT  0.144 39.115 0.594 39.547 ;
     RECT  1.728 39.245 12.33 39.547 ;
     RECT  0.144 39.547 12.33 39.587 ;
     RECT  15.915 38.471 20.286 39.595 ;
     RECT  0.144 39.587 11.934 39.869 ;
     RECT  0.144 39.869 0.63 39.979 ;
     RECT  15.915 39.595 20.502 39.979 ;
     RECT  0.108 39.979 0.63 40.595 ;
     RECT  13.215 37.229 15.174 40.639 ;
     RECT  15.915 39.979 20.538 40.639 ;
     RECT  13.215 40.639 20.538 40.901 ;
     RECT  0.216 40.595 0.63 41.035 ;
     RECT  1.728 39.869 11.934 41.035 ;
     RECT  21.492 39.307 21.51 41.131 ;
     RECT  0.216 41.035 11.934 41.179 ;
     RECT  0.216 41.179 12.006 41.279 ;
     RECT  0.216 41.279 11.934 41.323 ;
     RECT  21.456 41.131 21.51 41.419 ;
     RECT  21.42 41.419 21.51 41.707 ;
     RECT  0.108 41.323 11.934 41.819 ;
     RECT  15.915 40.901 20.538 41.819 ;
     RECT  21.276 41.707 21.51 41.947 ;
     RECT  0.108 41.819 0.414 41.981 ;
     RECT  0.108 41.981 0.198 42.025 ;
     RECT  0.072 42.025 0.198 42.053 ;
     RECT  21.24 41.947 21.51 42.125 ;
     RECT  1.152 41.819 11.934 42.223 ;
     RECT  21.276 42.125 21.51 42.251 ;
     RECT  21.312 42.251 21.51 42.287 ;
     RECT  13.215 40.901 15.102 42.493 ;
     RECT  1.152 42.223 12.258 42.701 ;
     RECT  1.188 42.701 12.258 42.835 ;
     RECT  1.188 42.835 12.402 42.961 ;
     RECT  13.215 42.493 15.138 42.961 ;
     RECT  15.915 41.819 20.502 43.133 ;
     RECT  0.072 42.053 0.162 43.147 ;
     RECT  1.188 42.961 15.138 43.267 ;
     RECT  15.915 43.133 20.43 43.267 ;
     RECT  0.072 43.147 0.234 43.435 ;
     RECT  21.456 42.287 21.51 43.435 ;
     RECT  21.42 43.435 21.51 43.673 ;
     RECT  1.188 43.267 20.43 43.675 ;
     RECT  0.072 43.435 0.342 43.853 ;
     RECT  1.152 43.675 20.43 43.871 ;
     RECT  1.152 43.871 20.322 44.141 ;
     RECT  0.072 43.853 0.162 44.681 ;
     RECT  1.152 44.141 20.286 44.681 ;
     RECT  0.108 44.681 0.162 44.765 ;
     RECT  1.26 44.681 20.286 44.875 ;
     RECT  0.108 44.765 0.126 44.909 ;
     RECT  1.26 44.875 20.322 45.149 ;
     RECT  21.492 43.673 21.51 45.163 ;
     RECT  21.456 45.163 21.51 45.259 ;
     RECT  21.42 45.259 21.51 45.643 ;
     RECT  2.268 45.149 20.322 45.773 ;
     RECT  12.564 45.773 20.322 45.797 ;
     RECT  0.144 45.787 0.162 45.835 ;
     RECT  2.268 45.773 11.754 45.869 ;
     RECT  13.032 45.797 20.322 45.931 ;
     RECT  0.144 45.835 0.45 46.013 ;
     RECT  0.144 46.013 0.342 46.027 ;
     RECT  1.26 45.149 1.35 46.109 ;
     RECT  21.384 45.643 21.51 46.315 ;
     RECT  13.032 45.931 20.43 46.409 ;
     RECT  15.915 46.409 20.43 46.411 ;
     RECT  13.032 46.409 15.102 46.615 ;
     RECT  2.268 45.869 11.286 46.651 ;
     RECT  21.348 46.315 21.51 46.732 ;
     RECT  0.108 46.027 0.342 46.769 ;
     RECT  21.384 46.732 21.51 46.913 ;
     RECT  2.232 46.651 11.286 47.035 ;
     RECT  0.144 46.769 0.342 47.069 ;
     RECT  2.232 47.035 11.394 47.131 ;
     RECT  0.324 47.069 0.342 47.155 ;
     RECT  1.26 46.109 1.278 47.155 ;
     RECT  2.196 47.131 11.394 47.183 ;
     RECT  2.232 47.183 11.394 47.323 ;
     RECT  12.528 46.615 15.102 47.381 ;
     RECT  2.232 47.323 11.718 47.389 ;
     RECT  0.324 47.155 1.278 47.405 ;
     RECT  21.42 46.913 21.51 47.489 ;
     RECT  2.232 47.389 11.754 47.623 ;
     RECT  1.152 47.405 1.278 47.755 ;
     RECT  0.324 47.405 0.342 47.885 ;
     RECT  1.152 47.755 1.35 48.043 ;
     RECT  2.232 47.623 12.258 48.043 ;
     RECT  1.152 48.043 12.258 48.163 ;
     RECT  13.068 47.381 15.102 48.163 ;
     RECT  21.492 47.489 21.51 48.235 ;
     RECT  1.152 48.163 15.102 48.433 ;
     RECT  21.456 48.235 21.51 48.533 ;
     RECT  21.456 48.533 21.474 48.569 ;
     RECT  21.348 49.003 21.366 49.181 ;
     RECT  0.324 49.099 0.342 49.195 ;
     RECT  0.144 49.195 0.342 49.229 ;
     RECT  15.915 46.411 20.502 49.235 ;
     RECT  21.456 49.291 21.474 49.775 ;
     RECT  15.915 49.235 20.43 50.059 ;
     RECT  1.152 48.433 15.138 50.089 ;
     RECT  21.492 49.963 21.51 50.189 ;
     RECT  0.144 49.229 0.162 50.251 ;
     RECT  0.144 50.251 0.342 50.347 ;
     RECT  0.108 50.347 0.342 50.395 ;
     RECT  1.152 50.089 15.174 50.395 ;
     RECT  15.915 50.059 20.538 50.395 ;
     RECT  1.152 50.395 20.538 50.429 ;
     RECT  0.108 50.395 0.414 50.459 ;
     RECT  0.108 50.459 0.342 50.504 ;
     RECT  1.188 50.429 20.538 50.539 ;
     RECT  1.188 50.539 20.574 50.621 ;
     RECT  1.332 50.621 20.574 50.827 ;
     RECT  0.18 50.504 0.342 50.861 ;
     RECT  0.18 50.861 0.306 51.307 ;
     RECT  1.332 50.827 20.61 51.355 ;
     RECT  1.188 51.355 20.61 51.499 ;
     RECT  21.492 51.115 21.51 51.539 ;
     RECT  1.152 51.499 20.61 51.677 ;
     RECT  1.188 51.677 20.61 51.773 ;
     RECT  1.332 51.773 20.538 51.809 ;
     RECT  0.144 51.307 0.306 51.883 ;
     RECT  21.42 51.595 21.438 51.971 ;
     RECT  1.692 51.809 20.538 52.007 ;
     RECT  0.144 51.883 0.342 52.171 ;
     RECT  0.108 52.171 0.342 52.277 ;
     RECT  0.144 52.277 0.342 52.301 ;
     RECT  0.144 52.301 0.198 52.397 ;
     RECT  21.456 52.459 21.51 52.547 ;
     RECT  21.456 52.547 21.474 52.795 ;
     RECT  21.42 52.795 21.474 52.973 ;
     RECT  0.144 52.397 0.162 53.309 ;
     RECT  1.692 52.007 20.502 53.323 ;
     RECT  1.26 53.323 20.502 53.371 ;
     RECT  21.456 52.973 21.474 53.429 ;
     RECT  0.216 53.707 0.342 53.837 ;
     RECT  1.152 53.371 20.502 53.869 ;
     RECT  1.152 53.869 20.538 54.029 ;
     RECT  1.152 54.029 20.43 54.131 ;
     RECT  0.216 53.837 0.234 54.283 ;
     RECT  0.144 54.283 0.234 54.481 ;
     RECT  0.108 54.481 0.234 54.571 ;
     RECT  1.152 54.131 20.394 54.571 ;
     RECT  21.492 54.475 21.51 54.571 ;
     RECT  0.108 54.571 20.394 54.605 ;
     RECT  0.18 54.605 20.394 54.671 ;
     RECT  21.456 54.571 21.51 54.977 ;
     RECT  0.18 54.671 20.322 55.211 ;
     RECT  0.18 55.211 1.35 55.247 ;
     RECT  0.18 55.247 1.314 55.277 ;
     RECT  2.124 55.211 20.322 55.435 ;
     RECT  2.124 55.435 20.43 55.589 ;
     RECT  0.18 55.277 0.378 55.757 ;
     RECT  0.18 55.757 0.342 55.795 ;
     RECT  0.108 55.795 0.342 55.853 ;
     RECT  2.304 55.589 20.43 56.011 ;
     RECT  2.304 56.011 20.538 56.395 ;
     RECT  2.304 56.395 20.574 56.867 ;
     RECT  1.152 56.059 1.278 56.909 ;
     RECT  21.492 54.977 21.51 56.971 ;
     RECT  0.144 55.853 0.342 57.005 ;
     RECT  1.152 56.909 1.17 57.005 ;
     RECT  2.304 56.867 20.538 57.137 ;
     RECT  21.456 56.971 21.51 57.307 ;
     RECT  0.144 57.005 0.234 57.437 ;
     RECT  0.216 57.437 0.234 57.485 ;
     RECT  21.42 57.307 21.51 57.581 ;
     RECT  21.492 57.581 21.51 57.641 ;
     RECT  1.26 57.643 1.278 57.721 ;
     RECT  2.304 57.137 20.502 57.721 ;
     RECT  1.26 57.721 20.502 57.835 ;
     RECT  1.152 57.835 20.502 57.869 ;
     RECT  1.152 57.869 1.17 58.157 ;
     RECT  0.324 57.739 0.342 58.219 ;
     RECT  0.324 58.219 0.414 58.315 ;
     RECT  0.252 58.315 0.414 58.492 ;
     RECT  0.18 58.492 0.414 58.541 ;
     RECT  0.18 58.541 0.198 58.795 ;
     RECT  1.98 57.869 20.502 58.801 ;
     RECT  1.98 58.801 20.538 58.925 ;
     RECT  0.144 58.795 0.198 59.371 ;
     RECT  1.98 58.925 20.502 59.567 ;
     RECT  1.152 59.275 1.17 59.693 ;
     RECT  1.98 59.567 19.386 59.801 ;
     RECT  1.98 59.801 19.314 59.999 ;
     RECT  1.98 59.999 19.278 60.235 ;
     RECT  21.492 59.659 21.51 60.331 ;
     RECT  21.456 60.331 21.51 60.412 ;
     RECT  0.144 59.371 0.342 60.427 ;
     RECT  1.764 60.235 19.278 60.571 ;
     RECT  0.144 60.427 0.45 60.605 ;
     RECT  0.144 60.605 0.378 60.653 ;
     RECT  1.368 60.571 19.278 60.667 ;
     RECT  21.42 60.412 21.51 60.811 ;
     RECT  1.152 60.667 19.278 60.845 ;
     RECT  0.144 60.653 0.342 60.859 ;
     RECT  1.368 60.845 19.278 60.941 ;
     RECT  0.036 60.859 0.342 60.953 ;
     RECT  21.384 60.811 21.51 60.989 ;
     RECT  1.692 60.941 19.278 61.003 ;
     RECT  20.304 59.567 20.502 61.003 ;
     RECT  1.692 61.003 20.502 61.421 ;
     RECT  0.108 60.953 0.342 61.579 ;
     RECT  1.692 61.421 19.386 61.723 ;
     RECT  21.492 60.989 21.51 61.762 ;
     RECT  1.152 61.723 19.386 61.997 ;
     RECT  20.484 61.421 20.502 62.005 ;
     RECT  0.108 61.579 0.414 62.045 ;
     RECT  21.456 61.762 21.51 62.231 ;
     RECT  0.108 62.045 0.342 62.285 ;
     RECT  1.98 61.997 19.386 62.311 ;
     RECT  1.98 62.311 19.422 62.381 ;
     RECT  1.98 62.381 18.954 62.429 ;
     RECT  1.98 62.429 18.705 62.501 ;
     RECT  1.152 61.997 1.17 62.525 ;
     RECT  1.98 62.501 16.542 62.525 ;
     RECT  1.98 62.525 14.058 62.537 ;
     RECT  14.832 62.525 16.542 62.537 ;
     RECT  17.28 62.501 18.705 62.537 ;
     RECT  20.484 62.005 20.574 62.545 ;
     RECT  19.944 62.545 20.574 62.573 ;
     RECT  1.98 62.537 13.986 62.609 ;
     RECT  15.228 62.537 16.542 62.609 ;
     RECT  19.944 62.573 20.502 62.609 ;
     RECT  11.844 62.609 13.986 62.657 ;
     RECT  15.228 62.609 16.005 62.657 ;
     RECT  17.568 62.537 18.705 62.657 ;
     RECT  19.944 62.609 19.962 62.669 ;
     RECT  11.844 62.657 13.086 62.699 ;
     RECT  13.824 62.657 13.986 62.699 ;
     RECT  15.228 62.657 15.318 62.699 ;
     RECT  17.568 62.657 18.594 62.699 ;
     RECT  21.456 62.231 21.474 62.699 ;
     RECT  13.896 62.699 13.914 62.735 ;
     RECT  12.132 62.699 13.086 62.765 ;
     RECT  18.252 62.699 18.594 62.765 ;
     RECT  12.132 62.765 13.05 62.771 ;
     RECT  1.98 62.609 10.674 62.807 ;
     RECT  1.224 62.731 1.242 62.827 ;
     RECT  1.98 62.807 10.134 62.827 ;
     RECT  18.576 62.765 18.594 62.861 ;
     RECT  12.132 62.771 12.798 62.879 ;
     RECT  1.224 62.827 10.134 62.969 ;
     RECT  0.144 62.285 0.162 63.005 ;
     RECT  12.312 62.879 12.798 63.005 ;
     RECT  12.312 63.005 12.33 63.041 ;
     RECT  1.224 62.969 9.666 63.077 ;
     RECT  1.224 63.077 8.55 63.101 ;
     RECT  1.224 63.101 6.102 63.149 ;
     RECT  1.224 63.149 5.85 63.194 ;
     RECT  6.876 63.101 8.55 63.197 ;
     RECT  1.224 63.194 4.626 63.239 ;
     RECT  5.832 63.194 5.85 63.239 ;
     RECT  1.224 63.239 4.194 63.245 ;
     RECT  1.98 63.245 4.194 63.293 ;
     RECT  7.02 63.197 8.55 63.293 ;
     RECT  7.02 63.293 8.01 63.311 ;
     RECT  3.492 63.293 4.194 63.389 ;
     RECT  9.648 63.077 9.666 63.389 ;
     RECT  1.98 63.293 2.142 63.437 ;
     RECT  3.564 63.389 4.194 63.437 ;
     RECT  1.98 63.437 2.07 63.629 ;
     RECT  2.052 63.629 2.07 63.725 ;
     RECT  7.02 63.311 7.578 63.821 ;
     RECT  4.176 63.437 4.194 63.917 ;
     RECT  7.56 63.821 7.578 64.013 ;
    LAYER M4 ;
     RECT  0.025 60.864 0.06 60.888 ;
     RECT  0.06 1.872 2.405 64.008 ;
     RECT  2.405 1.968 2.585 64.008 ;
     RECT  2.585 2.016 3.125 64.008 ;
     RECT  3.125 2.304 5.108 64.008 ;
     RECT  5.108 2.148 5.212 64.008 ;
     RECT  5.212 2.418 6.217 64.008 ;
     RECT  6.217 2.4 6.469 64.008 ;
     RECT  6.469 2.304 7.589 64.008 ;
     RECT  7.589 2.304 7.808 63.384 ;
     RECT  7.808 2.148 7.912 63.384 ;
     RECT  7.912 2.304 9.677 63.384 ;
     RECT  9.677 2.304 10.508 62.904 ;
     RECT  10.309 0.096 10.739 0.12 ;
     RECT  10.508 2.148 10.789 62.904 ;
     RECT  10.789 1.728 11.117 62.904 ;
     RECT  11.117 2.304 11.189 62.904 ;
     RECT  11.189 2.304 11.297 24.984 ;
     RECT  11.297 2.352 11.333 18.84 ;
     RECT  11.297 19.872 11.333 24.984 ;
     RECT  11.189 26.112 11.333 62.904 ;
     RECT  11.333 2.352 11.369 18.792 ;
     RECT  11.333 20.016 11.369 24.984 ;
     RECT  11.333 26.112 11.369 47.352 ;
     RECT  11.369 2.496 11.405 18.792 ;
     RECT  11.369 20.016 11.405 20.472 ;
     RECT  11.369 26.112 11.405 31.272 ;
     RECT  11.369 32.496 11.405 47.352 ;
     RECT  11.405 31.248 11.441 31.272 ;
     RECT  11.405 32.496 11.441 41.448 ;
     RECT  11.405 43.056 11.477 47.352 ;
     RECT  11.369 21.456 11.513 24.984 ;
     RECT  11.477 43.632 11.513 47.352 ;
     RECT  11.513 21.696 11.549 24.984 ;
     RECT  11.441 41.376 11.549 41.448 ;
     RECT  11.549 21.936 11.585 24.984 ;
     RECT  11.585 21.936 11.621 24.936 ;
     RECT  11.441 32.496 11.621 40.056 ;
     RECT  11.405 2.496 11.657 18.696 ;
     RECT  11.657 2.496 11.693 9.576 ;
     RECT  11.657 11.232 11.693 18.696 ;
     RECT  11.621 32.496 11.693 35.592 ;
     RECT  11.621 21.984 11.729 22.392 ;
     RECT  11.621 36.624 11.729 40.056 ;
     RECT  11.513 43.872 11.729 47.352 ;
     RECT  11.693 15.84 11.801 18.696 ;
     RECT  11.621 23.376 11.801 24.936 ;
     RECT  11.729 36.624 11.801 38.184 ;
     RECT  11.549 41.376 11.945 41.4 ;
     RECT  11.405 26.112 11.981 30.216 ;
     RECT  11.801 36.72 11.981 38.184 ;
     RECT  11.801 15.84 12.017 18.168 ;
     RECT  11.729 39.504 12.053 40.056 ;
     RECT  11.729 43.872 12.053 47.304 ;
     RECT  11.333 48.672 12.053 62.904 ;
     RECT  12.017 16.032 12.125 18.168 ;
     RECT  12.053 48.672 12.161 55.224 ;
     RECT  12.053 56.304 12.449 62.904 ;
     RECT  11.693 5.472 12.956 9.576 ;
     RECT  12.956 5.472 12.985 9.864 ;
     RECT  12.449 56.304 13.097 62.76 ;
     RECT  11.693 2.496 13.208 3.144 ;
     RECT  11.693 4.464 13.208 4.488 ;
     RECT  12.985 5.472 13.208 10.152 ;
     RECT  11.693 11.232 13.208 14.76 ;
     RECT  12.125 16.032 13.208 16.056 ;
     RECT  12.125 17.376 13.208 18.168 ;
     RECT  11.405 20.448 13.208 20.472 ;
     RECT  11.729 21.984 13.208 22.008 ;
     RECT  11.801 23.376 13.208 23.64 ;
     RECT  11.801 24.912 13.208 24.936 ;
     RECT  11.981 26.496 13.208 30.216 ;
     RECT  11.693 32.496 13.208 35.544 ;
     RECT  11.981 36.768 13.208 38.184 ;
     RECT  12.053 40.032 13.208 40.056 ;
     RECT  12.053 44.064 13.208 47.304 ;
     RECT  12.161 48.672 13.208 55.128 ;
     RECT  13.097 56.304 13.208 62.652 ;
     RECT  13.208 2.148 13.312 62.652 ;
     RECT  13.312 2.418 13.504 62.52 ;
     RECT  13.504 32.496 13.565 35.544 ;
     RECT  13.504 10.656 14.213 11.784 ;
     RECT  13.504 14.736 14.249 14.76 ;
     RECT  13.504 61.872 14.249 62.52 ;
     RECT  14.249 61.872 14.533 61.992 ;
     RECT  13.504 58.896 14.605 59.592 ;
     RECT  13.504 26.496 14.641 29.496 ;
     RECT  14.213 10.656 14.717 11.736 ;
     RECT  13.504 5.472 14.753 9.576 ;
     RECT  14.605 58.704 14.789 59.592 ;
     RECT  13.504 4.368 14.821 4.392 ;
     RECT  14.753 5.472 14.821 9.528 ;
     RECT  13.504 20.448 14.821 20.472 ;
     RECT  13.504 21.984 14.821 22.008 ;
     RECT  13.504 23.376 14.821 23.64 ;
     RECT  14.641 26.496 14.821 29.832 ;
     RECT  14.821 26.352 14.825 29.832 ;
     RECT  14.821 4.368 14.861 9.528 ;
     RECT  14.821 20.352 14.861 20.472 ;
     RECT  13.504 44.064 14.861 47.208 ;
     RECT  14.821 21.984 14.933 23.64 ;
     RECT  14.789 58.896 14.933 59.592 ;
     RECT  13.504 2.496 15.908 3.144 ;
     RECT  14.861 4.464 15.908 9.528 ;
     RECT  14.717 11.232 15.908 11.736 ;
     RECT  13.504 13.152 15.908 13.176 ;
     RECT  13.504 17.376 15.908 18.168 ;
     RECT  14.861 20.352 15.908 20.376 ;
     RECT  14.933 21.984 15.908 22.008 ;
     RECT  14.933 23.616 15.908 23.64 ;
     RECT  13.504 24.912 15.908 24.936 ;
     RECT  14.825 26.352 15.908 29.592 ;
     RECT  13.565 32.784 15.908 35.544 ;
     RECT  13.504 36.768 15.908 38.184 ;
     RECT  13.504 40.032 15.908 40.056 ;
     RECT  14.861 44.064 15.908 47.112 ;
     RECT  13.504 48.672 15.908 53.304 ;
     RECT  13.504 57.072 15.908 57.432 ;
     RECT  14.933 58.944 15.908 59.592 ;
     RECT  13.504 60.624 15.908 60.648 ;
     RECT  14.533 61.728 15.908 61.992 ;
     RECT  15.908 2.148 16.012 62.652 ;
     RECT  16.012 2.418 16.204 62.382 ;
     RECT  16.204 5.472 16.265 9.528 ;
     RECT  16.265 5.472 16.301 8.232 ;
     RECT  16.204 57.072 16.553 57.432 ;
     RECT  16.204 21.984 16.661 23.64 ;
     RECT  16.204 18.528 16.841 18.792 ;
     RECT  16.204 44.064 17.093 53.544 ;
     RECT  16.204 2.418 17.161 4.488 ;
     RECT  16.204 41.904 17.197 42.696 ;
     RECT  16.204 61.632 17.197 61.992 ;
     RECT  16.204 58.992 17.233 59.016 ;
     RECT  16.204 60 17.233 60.648 ;
     RECT  17.197 61.632 17.233 62.136 ;
     RECT  16.204 10.848 17.269 11.736 ;
     RECT  16.204 12.768 17.269 13.176 ;
     RECT  16.204 26.352 17.273 30.984 ;
     RECT  17.197 41.904 17.309 42.792 ;
     RECT  16.265 9.312 17.341 9.528 ;
     RECT  17.269 10.848 17.341 13.176 ;
     RECT  16.204 20.352 17.341 20.376 ;
     RECT  16.204 31.968 17.345 35.544 ;
     RECT  16.204 24.912 17.377 24.936 ;
     RECT  17.161 2.352 17.381 4.488 ;
     RECT  16.661 21.984 17.381 22.824 ;
     RECT  16.301 8.208 17.413 8.232 ;
     RECT  16.301 5.472 17.449 6.936 ;
     RECT  17.341 19.392 17.453 20.376 ;
     RECT  17.233 60 17.485 62.136 ;
     RECT  17.273 28.752 17.489 30.984 ;
     RECT  17.233 58.608 17.521 59.016 ;
     RECT  17.485 60 17.521 62.472 ;
     RECT  17.381 2.352 17.557 3.336 ;
     RECT  16.204 17.376 17.593 17.448 ;
     RECT  17.381 21.984 17.593 22.488 ;
     RECT  17.557 2.256 17.629 3.336 ;
     RECT  17.093 46.848 17.701 53.544 ;
     RECT  17.413 54.576 17.701 54.6 ;
     RECT  17.377 24.144 17.881 24.936 ;
     RECT  17.593 17.376 17.953 18.168 ;
     RECT  17.701 46.848 17.989 54.6 ;
     RECT  17.341 9.312 18.025 13.176 ;
     RECT  16.553 57.072 18.097 57.336 ;
     RECT  17.521 58.608 18.097 62.472 ;
     RECT  17.989 46.848 18.133 54.888 ;
     RECT  18.097 57.072 18.241 62.472 ;
     RECT  17.629 1.488 18.385 3.336 ;
     RECT  18.133 46.848 18.457 54.984 ;
     RECT  18.241 57.072 18.565 62.76 ;
     RECT  17.309 41.904 18.601 42.696 ;
     RECT  18.385 1.104 18.608 3.336 ;
     RECT  17.449 4.704 18.608 6.936 ;
     RECT  17.413 7.92 18.608 8.232 ;
     RECT  18.025 9.312 18.608 13.8 ;
     RECT  18.025 14.832 18.608 14.856 ;
     RECT  17.953 17.136 18.608 18.168 ;
     RECT  17.453 19.392 18.608 19.416 ;
     RECT  17.593 21.696 18.608 22.488 ;
     RECT  17.881 23.52 18.608 24.936 ;
     RECT  17.273 26.352 18.608 27.72 ;
     RECT  17.489 28.752 18.608 29.64 ;
     RECT  17.489 30.96 18.608 30.984 ;
     RECT  17.345 32.784 18.608 35.544 ;
     RECT  16.204 36.864 18.608 38.184 ;
     RECT  16.204 40.032 18.608 40.056 ;
     RECT  18.601 41.76 18.608 42.696 ;
     RECT  17.093 44.064 18.608 45.72 ;
     RECT  18.457 46.752 18.608 54.984 ;
     RECT  18.565 57.072 18.608 62.856 ;
     RECT  18.608 1.104 18.904 62.856 ;
     RECT  18.904 1.104 19.897 18.6 ;
     RECT  18.904 20.112 19.897 24.552 ;
     RECT  18.904 25.728 19.897 40.776 ;
     RECT  18.904 41.952 19.897 62.856 ;
     RECT  19.897 0.912 20.185 18.888 ;
     RECT  20.185 0.912 20.401 19.08 ;
     RECT  19.897 20.112 20.401 62.856 ;
     RECT  20.401 0.912 20.473 62.856 ;
     RECT  20.473 0.816 21.481 62.856 ;
     RECT  21.481 0.72 21.564 62.856 ;
    LAYER M5 ;
     RECT  10.704 0.016 10.824 0.085 ;
     RECT  10.32 0.085 10.824 1.763 ;
     RECT  2.4 2.137 2.52 2.151 ;
     RECT  5.1 2.137 5.22 2.151 ;
     RECT  7.8 2.137 7.92 2.151 ;
     RECT  13.2 2.137 13.32 2.151 ;
     RECT  15.9 2.137 16.02 2.151 ;
     RECT  18.6 2.137 18.72 2.151 ;
     RECT  1.152 2.293 1.176 2.627 ;
     RECT  10.32 1.763 10.812 2.869 ;
     RECT  10.32 2.869 11.16 3.155 ;
     RECT  7.8 2.151 8.112 3.301 ;
     RECT  7.8 3.301 9.048 3.443 ;
     RECT  3.84 3.061 3.864 3.539 ;
     RECT  9.12 3.925 9.144 4.259 ;
     RECT  5.1 2.151 5.412 4.261 ;
     RECT  0.144 2.005 0.168 5.173 ;
     RECT  10.32 3.155 10.812 5.461 ;
     RECT  0.144 5.173 0.216 5.555 ;
     RECT  0.192 5.555 0.216 5.651 ;
     RECT  5.1 4.261 6.072 5.653 ;
     RECT  5.1 5.653 6.792 5.797 ;
     RECT  7.8 3.443 8.112 5.797 ;
     RECT  5.1 5.797 8.112 5.987 ;
     RECT  7.8 5.987 8.112 6.805 ;
     RECT  5.1 5.987 6.168 8.197 ;
     RECT  7.8 6.805 8.232 8.197 ;
     RECT  5.1 8.197 8.232 9.253 ;
     RECT  5.1 9.253 8.328 9.493 ;
     RECT  4.128 9.493 8.328 9.635 ;
     RECT  4.128 9.635 8.232 9.683 ;
     RECT  13.2 2.151 13.512 9.829 ;
     RECT  13.008 9.829 13.512 10.163 ;
     RECT  2.4 2.151 2.712 10.597 ;
     RECT  5.1 9.683 8.232 10.645 ;
     RECT  9.36 5.461 10.812 11.029 ;
     RECT  5.1 10.645 8.28 11.173 ;
     RECT  9.36 11.029 11.304 11.173 ;
     RECT  1.248 10.981 1.272 11.221 ;
     RECT  2.4 10.597 2.856 11.221 ;
     RECT  5.1 11.173 11.304 11.411 ;
     RECT  1.248 11.221 2.856 11.507 ;
     RECT  1.248 11.507 1.272 11.509 ;
     RECT  1.152 11.509 1.272 11.795 ;
     RECT  2.4 11.507 2.856 11.941 ;
     RECT  4.08 11.317 4.104 11.941 ;
     RECT  1.152 11.795 1.176 11.987 ;
     RECT  9.36 11.411 11.304 12.085 ;
     RECT  2.4 11.941 4.104 12.229 ;
     RECT  5.1 11.411 8.28 12.229 ;
     RECT  2.4 12.229 8.28 12.661 ;
     RECT  9.36 12.085 11.64 12.661 ;
     RECT  0.144 12.517 0.168 12.803 ;
     RECT  2.4 12.661 11.64 12.899 ;
     RECT  4.992 12.899 11.64 13.091 ;
     RECT  9.12 13.091 11.64 13.141 ;
     RECT  13.2 10.163 13.512 13.141 ;
     RECT  9.12 13.141 13.512 13.331 ;
     RECT  2.4 12.899 3.768 13.763 ;
     RECT  9.12 13.331 11.64 13.811 ;
     RECT  3.744 13.763 3.768 13.955 ;
     RECT  4.992 13.091 8.112 14.003 ;
     RECT  9.36 13.811 11.64 14.243 ;
     RECT  0.24 15.013 0.264 15.395 ;
     RECT  2.4 13.763 2.712 15.781 ;
     RECT  3.984 15.589 4.008 15.781 ;
     RECT  2.4 15.781 4.008 15.971 ;
     RECT  5.1 14.003 8.112 15.973 ;
     RECT  2.4 15.971 3.384 16.019 ;
     RECT  5.1 15.973 8.232 16.019 ;
     RECT  5.1 16.019 6.168 16.069 ;
     RECT  4.896 16.069 6.168 16.211 ;
     RECT  7.584 16.019 8.232 16.355 ;
     RECT  1.152 16.309 1.176 16.499 ;
     RECT  7.8 16.355 8.232 16.645 ;
     RECT  9.36 14.243 10.812 16.645 ;
     RECT  5.1 16.211 6.168 16.981 ;
     RECT  2.4 16.019 3.24 17.027 ;
     RECT  0.144 16.837 0.168 17.123 ;
     RECT  7.8 16.645 10.812 17.123 ;
     RECT  0.24 17.413 0.264 17.603 ;
     RECT  7.8 17.123 8.232 18.085 ;
     RECT  2.4 17.027 2.904 18.131 ;
     RECT  5.1 16.981 6.456 18.131 ;
     RECT  0.144 18.229 0.168 18.803 ;
     RECT  5.1 18.131 6.312 18.947 ;
     RECT  2.4 18.131 2.808 19.141 ;
     RECT  2.4 19.141 2.904 19.379 ;
     RECT  2.4 19.379 2.808 20.387 ;
     RECT  7.68 18.085 8.232 20.677 ;
     RECT  5.1 18.947 6.072 21.349 ;
     RECT  7.536 20.677 8.232 21.349 ;
     RECT  5.1 21.349 8.232 21.491 ;
     RECT  5.1 21.491 8.112 21.683 ;
     RECT  0.144 21.733 0.168 21.923 ;
     RECT  2.4 20.387 2.712 21.925 ;
     RECT  2.4 21.925 3.576 22.115 ;
     RECT  5.1 21.683 6.072 22.693 ;
     RECT  7.44 21.683 8.112 22.693 ;
     RECT  15.9 2.151 16.212 22.693 ;
     RECT  15.9 22.693 17.112 22.835 ;
     RECT  9.36 17.123 10.812 23.173 ;
     RECT  9.36 23.173 10.92 23.747 ;
     RECT  2.4 22.115 2.712 23.845 ;
     RECT  0.144 23.605 0.168 23.891 ;
     RECT  2.304 23.845 2.712 24.325 ;
     RECT  2.304 24.325 3.576 24.707 ;
     RECT  1.152 24.613 1.176 24.947 ;
     RECT  2.4 24.707 3.576 24.995 ;
     RECT  9.36 23.747 10.812 26.099 ;
     RECT  5.1 22.693 8.112 26.819 ;
     RECT  9.984 26.099 10.812 26.821 ;
     RECT  9.984 26.821 11.208 27.107 ;
     RECT  2.4 24.995 2.712 27.349 ;
     RECT  9.984 27.107 10.92 27.395 ;
     RECT  2.304 27.349 2.712 27.827 ;
     RECT  10.32 27.395 10.92 28.117 ;
     RECT  2.4 27.827 2.712 28.213 ;
     RECT  2.4 28.213 2.808 28.403 ;
     RECT  5.1 26.819 6.072 28.597 ;
     RECT  4.272 28.597 6.072 28.837 ;
     RECT  1.248 28.741 1.272 28.979 ;
     RECT  4.176 28.837 6.072 29.027 ;
     RECT  10.32 28.117 11.208 29.075 ;
     RECT  10.32 29.075 10.812 29.125 ;
     RECT  10.224 29.125 10.812 29.507 ;
     RECT  2.4 28.403 2.712 29.557 ;
     RECT  5.1 29.027 6.072 29.557 ;
     RECT  2.4 29.557 3.672 29.747 ;
     RECT  0.144 29.797 0.168 29.987 ;
     RECT  5.1 29.557 6.312 30.371 ;
     RECT  21.36 30.853 21.384 30.995 ;
     RECT  0.24 30.901 0.264 31.187 ;
     RECT  2.4 29.747 2.712 31.237 ;
     RECT  7.344 26.819 8.112 31.619 ;
     RECT  0.144 31.429 0.168 31.715 ;
     RECT  2.304 31.237 2.712 31.717 ;
     RECT  2.304 31.717 3.528 32.051 ;
     RECT  2.4 32.051 3.528 32.293 ;
     RECT  10.32 29.507 10.812 32.581 ;
     RECT  2.4 32.293 3.816 32.675 ;
     RECT  10.32 32.581 11.4 32.819 ;
     RECT  2.4 32.675 3.528 32.963 ;
     RECT  7.44 31.619 8.112 33.733 ;
     RECT  7.44 33.733 8.52 33.973 ;
     RECT  0.144 33.973 0.168 34.163 ;
     RECT  10.32 32.819 10.812 34.165 ;
     RECT  7.344 33.973 8.52 34.211 ;
     RECT  2.4 32.963 2.712 34.693 ;
     RECT  7.8 34.211 8.52 34.885 ;
     RECT  9.744 34.165 10.812 34.885 ;
     RECT  2.4 34.693 3.528 34.933 ;
     RECT  2.4 34.933 3.816 35.221 ;
     RECT  2.256 35.221 3.816 35.459 ;
     RECT  1.248 35.509 1.272 35.843 ;
     RECT  5.1 30.371 6.072 35.845 ;
     RECT  7.8 34.885 10.812 35.939 ;
     RECT  7.8 35.939 9.144 35.987 ;
     RECT  5.1 35.845 6.264 36.181 ;
     RECT  2.4 35.459 3.816 36.229 ;
     RECT  10.272 35.939 10.812 36.323 ;
     RECT  2.4 36.229 3.864 36.371 ;
     RECT  3.84 36.371 3.864 36.515 ;
     RECT  5.1 36.181 6.504 36.517 ;
     RECT  7.8 35.987 8.52 36.517 ;
     RECT  5.1 36.517 8.52 36.707 ;
     RECT  2.4 36.371 2.808 37.043 ;
     RECT  10.368 36.323 10.812 37.381 ;
     RECT  10.368 37.381 11.16 37.573 ;
     RECT  9.696 37.573 11.16 38.003 ;
     RECT  9.792 38.003 11.16 38.149 ;
     RECT  9.792 38.149 11.352 38.291 ;
     RECT  0.144 37.381 0.168 38.771 ;
     RECT  9.792 38.291 11.112 39.781 ;
     RECT  2.4 37.043 2.712 40.261 ;
     RECT  5.1 36.707 6.504 40.261 ;
     RECT  2.304 40.261 6.504 40.403 ;
     RECT  2.4 40.403 6.504 40.691 ;
     RECT  9.744 39.781 11.112 40.883 ;
     RECT  0.144 40.837 0.168 41.027 ;
     RECT  2.4 40.691 3.672 41.027 ;
     RECT  10.224 40.883 11.112 41.363 ;
     RECT  4.992 40.691 6.504 41.507 ;
     RECT  7.8 36.707 8.52 41.557 ;
     RECT  4.992 41.507 6.072 41.651 ;
     RECT  2.4 41.027 2.712 42.085 ;
     RECT  2.304 42.085 2.712 42.275 ;
     RECT  2.4 42.275 2.712 43.333 ;
     RECT  5.1 41.651 6.072 43.333 ;
     RECT  4.272 43.333 6.072 43.475 ;
     RECT  2.4 43.333 2.808 43.813 ;
     RECT  0.144 43.669 0.168 43.859 ;
     RECT  2.4 43.813 3.672 44.243 ;
     RECT  5.1 43.475 6.072 44.483 ;
     RECT  10.5 41.363 11.112 45.685 ;
     RECT  10.5 45.685 11.736 45.875 ;
     RECT  7.8 41.557 8.952 46.645 ;
     RECT  10.5 45.875 11.112 46.645 ;
     RECT  2.4 44.243 2.712 46.789 ;
     RECT  2.304 46.789 2.712 47.075 ;
     RECT  2.4 47.075 2.712 47.077 ;
     RECT  0.144 46.501 0.168 47.891 ;
     RECT  2.4 47.077 3.672 48.661 ;
     RECT  2.4 48.661 3.72 49.043 ;
     RECT  2.4 49.043 3.672 50.291 ;
     RECT  2.4 50.291 3.576 50.771 ;
     RECT  7.8 46.645 11.112 50.821 ;
     RECT  7.8 50.821 11.928 51.107 ;
     RECT  2.4 50.771 3.528 51.925 ;
     RECT  2.4 51.925 3.816 52.405 ;
     RECT  5.1 44.483 5.412 52.405 ;
     RECT  0.192 52.261 0.216 52.451 ;
     RECT  7.8 51.107 11.112 52.453 ;
     RECT  2.304 52.405 5.412 52.547 ;
     RECT  7.8 52.453 11.832 52.835 ;
     RECT  6.624 52.597 6.648 52.933 ;
     RECT  7.8 52.835 11.112 52.933 ;
     RECT  6.624 52.933 11.112 53.219 ;
     RECT  6.624 53.219 6.648 53.461 ;
     RECT  0.144 53.557 0.168 53.843 ;
     RECT  1.296 54.421 1.32 54.565 ;
     RECT  6.48 53.461 6.648 54.613 ;
     RECT  7.68 53.219 11.112 54.613 ;
     RECT  1.152 54.565 1.32 54.659 ;
     RECT  1.152 54.659 1.176 54.707 ;
     RECT  6.48 54.613 11.112 54.755 ;
     RECT  2.4 52.547 5.412 54.803 ;
     RECT  6.48 54.755 6.504 54.949 ;
     RECT  6.432 54.949 6.504 55.139 ;
     RECT  7.68 54.755 11.112 55.283 ;
     RECT  9.36 55.283 11.112 55.331 ;
     RECT  2.4 54.803 4.008 55.379 ;
     RECT  10.5 55.331 11.112 55.429 ;
     RECT  3.984 55.379 4.008 55.475 ;
     RECT  0.24 55.717 0.264 55.859 ;
     RECT  6.48 55.139 6.504 55.955 ;
     RECT  2.4 55.379 2.712 56.869 ;
     RECT  10.5 55.429 11.16 56.869 ;
     RECT  2.4 56.869 3.048 56.917 ;
     RECT  2.4 56.917 3.72 57.013 ;
     RECT  5.1 54.803 5.412 57.013 ;
     RECT  7.68 55.283 8.376 57.061 ;
     RECT  9.36 55.331 9.384 57.061 ;
     RECT  10.368 56.869 11.16 57.061 ;
     RECT  7.68 57.061 9.384 57.109 ;
     RECT  10.368 57.061 11.4 57.109 ;
     RECT  7.68 57.109 11.4 57.203 ;
     RECT  9.36 57.203 11.16 57.251 ;
     RECT  10.368 57.251 11.16 57.299 ;
     RECT  7.68 57.203 8.376 57.395 ;
     RECT  21.456 57.253 21.48 57.587 ;
     RECT  10.5 57.299 11.16 57.635 ;
     RECT  2.4 57.013 5.412 57.827 ;
     RECT  7.68 57.395 8.112 58.405 ;
     RECT  9.36 57.251 9.384 58.405 ;
     RECT  7.68 58.405 9.384 58.451 ;
     RECT  0.144 57.589 0.168 58.595 ;
     RECT  2.4 57.827 3.528 58.835 ;
     RECT  2.4 58.835 3.384 59.315 ;
     RECT  7.8 58.451 9.384 59.411 ;
     RECT  0.192 59.461 0.216 59.651 ;
     RECT  7.8 59.411 9.144 59.939 ;
     RECT  2.4 59.315 3.336 59.989 ;
     RECT  2.208 59.989 3.336 60.371 ;
     RECT  0.24 60.613 0.264 60.803 ;
     RECT  2.4 60.371 3.336 60.901 ;
     RECT  4.512 57.827 5.412 60.901 ;
     RECT  1.248 60.805 1.272 60.947 ;
     RECT  7.8 59.939 8.376 61.331 ;
     RECT  0.144 61.189 0.168 61.379 ;
     RECT  2.4 60.901 5.412 61.859 ;
     RECT  3.792 61.859 5.412 62.003 ;
     RECT  2.4 61.859 2.712 62.053 ;
     RECT  10.5 57.635 11.112 62.435 ;
     RECT  7.8 61.331 8.112 62.533 ;
     RECT  3.888 62.003 5.412 62.627 ;
     RECT  2.304 62.053 2.712 62.649 ;
     RECT  6.864 62.533 8.112 62.649 ;
     RECT  10.5 62.435 10.812 62.649 ;
     RECT  13.2 13.331 13.512 62.649 ;
     RECT  15.9 22.835 16.212 62.649 ;
     RECT  18.6 2.151 18.912 62.649 ;
     RECT  2.304 62.649 2.52 62.663 ;
     RECT  6.864 62.649 7.92 62.663 ;
     RECT  10.5 62.649 10.62 62.663 ;
     RECT  13.2 62.649 13.32 62.663 ;
     RECT  15.9 62.649 16.02 62.663 ;
     RECT  18.6 62.649 18.72 62.663 ;
     RECT  6.864 62.663 6.888 62.677 ;
     RECT  4.704 62.627 5.412 62.723 ;
     RECT  6.768 62.677 6.888 62.723 ;
     RECT  2.304 62.663 2.328 62.867 ;
     RECT  6.768 62.723 6.792 62.963 ;
     RECT  5.088 62.723 5.412 63.109 ;
     RECT  5.088 63.109 5.592 63.251 ;
     RECT  5.088 63.251 5.112 63.443 ;
  END
END hbfd_rly_624_EW
END LIBRARY
